VERSION 5.8 ;
BUSBITCHARS "[]" ;
DIVIDERCHAR "/" ;
UNITS
    DATABASE MICRONS 1000 ;
END UNITS

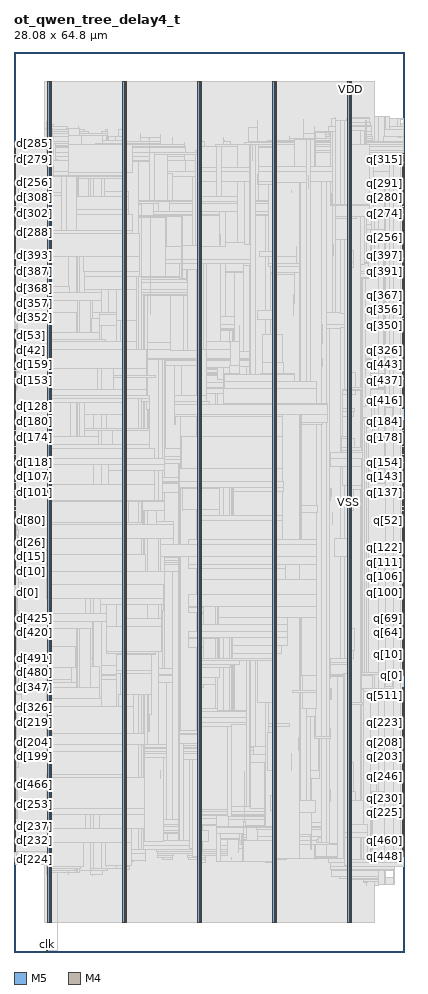
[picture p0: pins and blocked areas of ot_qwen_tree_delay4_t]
MACRO ot_qwen_tree_delay4_t
  FOREIGN ot_qwen_tree_delay4_t 0 0 ;
  CLASS BLOCK ;
  SIZE 28.08 BY 64.8 ;
  PIN clk
    DIRECTION INPUT ;
    USE SIGNAL ;
    PORT
      LAYER M5 ;
        RECT  2.352 0 2.376 0.084 ;
    END
    PORT
      LAYER M5 ;
        RECT  2.352 0.016 2.376 0.085 ;
    END
  END clk
  PIN d[0]
    DIRECTION INPUT ;
    USE SIGNAL ;
    PORT
      LAYER M4 ;
        RECT  0 26.448 0.084 26.472 ;
    END
  END d[0]
  PIN d[100]
    DIRECTION INPUT ;
    USE SIGNAL ;
    PORT
      LAYER M4 ;
        RECT  0 32.976 0.084 33 ;
    END
  END d[100]
  PIN d[101]
    DIRECTION INPUT ;
    USE SIGNAL ;
    PORT
      LAYER M4 ;
        RECT  0 33.072 0.084 33.096 ;
    END
  END d[101]
  PIN d[102]
    DIRECTION INPUT ;
    USE SIGNAL ;
    PORT
      LAYER M4 ;
        RECT  0 33.168 0.084 33.192 ;
    END
  END d[102]
  PIN d[103]
    DIRECTION INPUT ;
    USE SIGNAL ;
    PORT
      LAYER M4 ;
        RECT  0 33.264 0.084 33.288 ;
    END
  END d[103]
  PIN d[104]
    DIRECTION INPUT ;
    USE SIGNAL ;
    PORT
      LAYER M4 ;
        RECT  0 33.36 0.084 33.384 ;
    END
  END d[104]
  PIN d[105]
    DIRECTION INPUT ;
    USE SIGNAL ;
    PORT
      LAYER M4 ;
        RECT  0 33.456 0.084 33.48 ;
    END
  END d[105]
  PIN d[106]
    DIRECTION INPUT ;
    USE SIGNAL ;
    PORT
      LAYER M4 ;
        RECT  0 33.552 0.084 33.576 ;
    END
  END d[106]
  PIN d[107]
    DIRECTION INPUT ;
    USE SIGNAL ;
    PORT
      LAYER M4 ;
        RECT  0 33.648 0.084 33.672 ;
    END
  END d[107]
  PIN d[108]
    DIRECTION INPUT ;
    USE SIGNAL ;
    PORT
      LAYER M4 ;
        RECT  0 33.744 0.084 33.768 ;
    END
  END d[108]
  PIN d[109]
    DIRECTION INPUT ;
    USE SIGNAL ;
    PORT
      LAYER M4 ;
        RECT  0 33.84 0.084 33.864 ;
    END
  END d[109]
  PIN d[10]
    DIRECTION INPUT ;
    USE SIGNAL ;
    PORT
      LAYER M4 ;
        RECT  0 27.408 0.084 27.432 ;
    END
  END d[10]
  PIN d[110]
    DIRECTION INPUT ;
    USE SIGNAL ;
    PORT
      LAYER M4 ;
        RECT  0 33.936 0.084 33.96 ;
    END
  END d[110]
  PIN d[111]
    DIRECTION INPUT ;
    USE SIGNAL ;
    PORT
      LAYER M4 ;
        RECT  0 34.032 0.084 34.056 ;
    END
  END d[111]
  PIN d[112]
    DIRECTION INPUT ;
    USE SIGNAL ;
    PORT
      LAYER M4 ;
        RECT  0 34.128 0.084 34.152 ;
    END
  END d[112]
  PIN d[113]
    DIRECTION INPUT ;
    USE SIGNAL ;
    PORT
      LAYER M4 ;
        RECT  0 34.224 0.084 34.248 ;
    END
  END d[113]
  PIN d[114]
    DIRECTION INPUT ;
    USE SIGNAL ;
    PORT
      LAYER M4 ;
        RECT  0 34.32 0.084 34.344 ;
    END
  END d[114]
  PIN d[115]
    DIRECTION INPUT ;
    USE SIGNAL ;
    PORT
      LAYER M4 ;
        RECT  0 34.416 0.084 34.44 ;
    END
  END d[115]
  PIN d[116]
    DIRECTION INPUT ;
    USE SIGNAL ;
    PORT
      LAYER M4 ;
        RECT  0 34.512 0.084 34.536 ;
    END
  END d[116]
  PIN d[117]
    DIRECTION INPUT ;
    USE SIGNAL ;
    PORT
      LAYER M4 ;
        RECT  0 34.608 0.084 34.632 ;
    END
  END d[117]
  PIN d[118]
    DIRECTION INPUT ;
    USE SIGNAL ;
    PORT
      LAYER M4 ;
        RECT  0 34.704 0.084 34.728 ;
    END
  END d[118]
  PIN d[119]
    DIRECTION INPUT ;
    USE SIGNAL ;
    PORT
      LAYER M4 ;
        RECT  0 34.8 0.084 34.824 ;
    END
  END d[119]
  PIN d[11]
    DIRECTION INPUT ;
    USE SIGNAL ;
    PORT
      LAYER M4 ;
        RECT  0 27.504 0.084 27.528 ;
    END
  END d[11]
  PIN d[120]
    DIRECTION INPUT ;
    USE SIGNAL ;
    PORT
      LAYER M4 ;
        RECT  0 34.896 0.084 34.92 ;
    END
  END d[120]
  PIN d[121]
    DIRECTION INPUT ;
    USE SIGNAL ;
    PORT
      LAYER M4 ;
        RECT  0 34.992 0.084 35.016 ;
    END
  END d[121]
  PIN d[122]
    DIRECTION INPUT ;
    USE SIGNAL ;
    PORT
      LAYER M4 ;
        RECT  0 35.088 0.084 35.112 ;
    END
  END d[122]
  PIN d[123]
    DIRECTION INPUT ;
    USE SIGNAL ;
    PORT
      LAYER M4 ;
        RECT  0 35.184 0.084 35.208 ;
    END
  END d[123]
  PIN d[124]
    DIRECTION INPUT ;
    USE SIGNAL ;
    PORT
      LAYER M4 ;
        RECT  0 35.28 0.084 35.304 ;
    END
  END d[124]
  PIN d[125]
    DIRECTION INPUT ;
    USE SIGNAL ;
    PORT
      LAYER M4 ;
        RECT  0 35.376 0.084 35.4 ;
    END
  END d[125]
  PIN d[126]
    DIRECTION INPUT ;
    USE SIGNAL ;
    PORT
      LAYER M4 ;
        RECT  0 35.472 0.084 35.496 ;
    END
  END d[126]
  PIN d[127]
    DIRECTION INPUT ;
    USE SIGNAL ;
    PORT
      LAYER M4 ;
        RECT  0 35.568 0.084 35.592 ;
    END
  END d[127]
  PIN d[128]
    DIRECTION INPUT ;
    USE SIGNAL ;
    PORT
      LAYER M4 ;
        RECT  0 38.736 0.084 38.76 ;
    END
  END d[128]
  PIN d[129]
    DIRECTION INPUT ;
    USE SIGNAL ;
    PORT
      LAYER M4 ;
        RECT  0 38.832 0.084 38.856 ;
    END
  END d[129]
  PIN d[12]
    DIRECTION INPUT ;
    USE SIGNAL ;
    PORT
      LAYER M4 ;
        RECT  0 27.6 0.084 27.624 ;
    END
  END d[12]
  PIN d[130]
    DIRECTION INPUT ;
    USE SIGNAL ;
    PORT
      LAYER M4 ;
        RECT  0 38.928 0.084 38.952 ;
    END
  END d[130]
  PIN d[131]
    DIRECTION INPUT ;
    USE SIGNAL ;
    PORT
      LAYER M4 ;
        RECT  0 39.024 0.084 39.048 ;
    END
  END d[131]
  PIN d[132]
    DIRECTION INPUT ;
    USE SIGNAL ;
    PORT
      LAYER M4 ;
        RECT  0 39.12 0.084 39.144 ;
    END
  END d[132]
  PIN d[133]
    DIRECTION INPUT ;
    USE SIGNAL ;
    PORT
      LAYER M4 ;
        RECT  0 39.216 0.084 39.24 ;
    END
  END d[133]
  PIN d[134]
    DIRECTION INPUT ;
    USE SIGNAL ;
    PORT
      LAYER M4 ;
        RECT  0 39.312 0.084 39.336 ;
    END
  END d[134]
  PIN d[135]
    DIRECTION INPUT ;
    USE SIGNAL ;
    PORT
      LAYER M4 ;
        RECT  0 39.408 0.084 39.432 ;
    END
  END d[135]
  PIN d[136]
    DIRECTION INPUT ;
    USE SIGNAL ;
    PORT
      LAYER M4 ;
        RECT  0 39.504 0.084 39.528 ;
    END
  END d[136]
  PIN d[137]
    DIRECTION INPUT ;
    USE SIGNAL ;
    PORT
      LAYER M4 ;
        RECT  0 39.6 0.084 39.624 ;
    END
  END d[137]
  PIN d[138]
    DIRECTION INPUT ;
    USE SIGNAL ;
    PORT
      LAYER M4 ;
        RECT  0 39.696 0.084 39.72 ;
    END
  END d[138]
  PIN d[139]
    DIRECTION INPUT ;
    USE SIGNAL ;
    PORT
      LAYER M4 ;
        RECT  0 39.792 0.084 39.816 ;
    END
  END d[139]
  PIN d[13]
    DIRECTION INPUT ;
    USE SIGNAL ;
    PORT
      LAYER M4 ;
        RECT  0 27.696 0.084 27.72 ;
    END
  END d[13]
  PIN d[140]
    DIRECTION INPUT ;
    USE SIGNAL ;
    PORT
      LAYER M4 ;
        RECT  0 39.888 0.084 39.912 ;
    END
  END d[140]
  PIN d[141]
    DIRECTION INPUT ;
    USE SIGNAL ;
    PORT
      LAYER M4 ;
        RECT  0 39.984 0.084 40.008 ;
    END
  END d[141]
  PIN d[142]
    DIRECTION INPUT ;
    USE SIGNAL ;
    PORT
      LAYER M4 ;
        RECT  0 40.08 0.084 40.104 ;
    END
  END d[142]
  PIN d[143]
    DIRECTION INPUT ;
    USE SIGNAL ;
    PORT
      LAYER M4 ;
        RECT  0 40.176 0.084 40.2 ;
    END
  END d[143]
  PIN d[144]
    DIRECTION INPUT ;
    USE SIGNAL ;
    PORT
      LAYER M4 ;
        RECT  0 40.272 0.084 40.296 ;
    END
  END d[144]
  PIN d[145]
    DIRECTION INPUT ;
    USE SIGNAL ;
    PORT
      LAYER M4 ;
        RECT  0 40.368 0.084 40.392 ;
    END
  END d[145]
  PIN d[146]
    DIRECTION INPUT ;
    USE SIGNAL ;
    PORT
      LAYER M4 ;
        RECT  0 40.464 0.084 40.488 ;
    END
  END d[146]
  PIN d[147]
    DIRECTION INPUT ;
    USE SIGNAL ;
    PORT
      LAYER M4 ;
        RECT  0 40.56 0.084 40.584 ;
    END
  END d[147]
  PIN d[148]
    DIRECTION INPUT ;
    USE SIGNAL ;
    PORT
      LAYER M4 ;
        RECT  0 40.656 0.084 40.68 ;
    END
  END d[148]
  PIN d[149]
    DIRECTION INPUT ;
    USE SIGNAL ;
    PORT
      LAYER M4 ;
        RECT  0 40.752 0.084 40.776 ;
    END
  END d[149]
  PIN d[14]
    DIRECTION INPUT ;
    USE SIGNAL ;
    PORT
      LAYER M4 ;
        RECT  0 27.792 0.084 27.816 ;
    END
  END d[14]
  PIN d[150]
    DIRECTION INPUT ;
    USE SIGNAL ;
    PORT
      LAYER M4 ;
        RECT  0 40.848 0.084 40.872 ;
    END
  END d[150]
  PIN d[151]
    DIRECTION INPUT ;
    USE SIGNAL ;
    PORT
      LAYER M4 ;
        RECT  0 40.944 0.084 40.968 ;
    END
  END d[151]
  PIN d[152]
    DIRECTION INPUT ;
    USE SIGNAL ;
    PORT
      LAYER M4 ;
        RECT  0 41.04 0.084 41.064 ;
    END
  END d[152]
  PIN d[153]
    DIRECTION INPUT ;
    USE SIGNAL ;
    PORT
      LAYER M4 ;
        RECT  0 41.136 0.084 41.16 ;
    END
  END d[153]
  PIN d[154]
    DIRECTION INPUT ;
    USE SIGNAL ;
    PORT
      LAYER M4 ;
        RECT  0 41.232 0.084 41.256 ;
    END
  END d[154]
  PIN d[155]
    DIRECTION INPUT ;
    USE SIGNAL ;
    PORT
      LAYER M4 ;
        RECT  0 41.328 0.084 41.352 ;
    END
  END d[155]
  PIN d[156]
    DIRECTION INPUT ;
    USE SIGNAL ;
    PORT
      LAYER M4 ;
        RECT  0 41.424 0.084 41.448 ;
    END
  END d[156]
  PIN d[157]
    DIRECTION INPUT ;
    USE SIGNAL ;
    PORT
      LAYER M4 ;
        RECT  0 41.52 0.084 41.544 ;
    END
  END d[157]
  PIN d[158]
    DIRECTION INPUT ;
    USE SIGNAL ;
    PORT
      LAYER M4 ;
        RECT  0 41.616 0.084 41.64 ;
    END
  END d[158]
  PIN d[159]
    DIRECTION INPUT ;
    USE SIGNAL ;
    PORT
      LAYER M4 ;
        RECT  0 41.712 0.084 41.736 ;
    END
  END d[159]
  PIN d[15]
    DIRECTION INPUT ;
    USE SIGNAL ;
    PORT
      LAYER M4 ;
        RECT  0 27.888 0.084 27.912 ;
    END
  END d[15]
  PIN d[160]
    DIRECTION INPUT ;
    USE SIGNAL ;
    PORT
      LAYER M4 ;
        RECT  0 35.664 0.084 35.688 ;
    END
  END d[160]
  PIN d[161]
    DIRECTION INPUT ;
    USE SIGNAL ;
    PORT
      LAYER M4 ;
        RECT  0 35.76 0.084 35.784 ;
    END
  END d[161]
  PIN d[162]
    DIRECTION INPUT ;
    USE SIGNAL ;
    PORT
      LAYER M4 ;
        RECT  0 35.856 0.084 35.88 ;
    END
  END d[162]
  PIN d[163]
    DIRECTION INPUT ;
    USE SIGNAL ;
    PORT
      LAYER M4 ;
        RECT  0 35.952 0.084 35.976 ;
    END
  END d[163]
  PIN d[164]
    DIRECTION INPUT ;
    USE SIGNAL ;
    PORT
      LAYER M4 ;
        RECT  0 36.048 0.084 36.072 ;
    END
  END d[164]
  PIN d[165]
    DIRECTION INPUT ;
    USE SIGNAL ;
    PORT
      LAYER M4 ;
        RECT  0 36.144 0.084 36.168 ;
    END
  END d[165]
  PIN d[166]
    DIRECTION INPUT ;
    USE SIGNAL ;
    PORT
      LAYER M4 ;
        RECT  0 36.24 0.084 36.264 ;
    END
  END d[166]
  PIN d[167]
    DIRECTION INPUT ;
    USE SIGNAL ;
    PORT
      LAYER M4 ;
        RECT  0 36.336 0.084 36.36 ;
    END
  END d[167]
  PIN d[168]
    DIRECTION INPUT ;
    USE SIGNAL ;
    PORT
      LAYER M4 ;
        RECT  0 36.432 0.084 36.456 ;
    END
  END d[168]
  PIN d[169]
    DIRECTION INPUT ;
    USE SIGNAL ;
    PORT
      LAYER M4 ;
        RECT  0 36.528 0.084 36.552 ;
    END
  END d[169]
  PIN d[16]
    DIRECTION INPUT ;
    USE SIGNAL ;
    PORT
      LAYER M4 ;
        RECT  0 27.984 0.084 28.008 ;
    END
  END d[16]
  PIN d[170]
    DIRECTION INPUT ;
    USE SIGNAL ;
    PORT
      LAYER M4 ;
        RECT  0 36.624 0.084 36.648 ;
    END
  END d[170]
  PIN d[171]
    DIRECTION INPUT ;
    USE SIGNAL ;
    PORT
      LAYER M4 ;
        RECT  0 36.72 0.084 36.744 ;
    END
  END d[171]
  PIN d[172]
    DIRECTION INPUT ;
    USE SIGNAL ;
    PORT
      LAYER M4 ;
        RECT  0 36.816 0.084 36.84 ;
    END
  END d[172]
  PIN d[173]
    DIRECTION INPUT ;
    USE SIGNAL ;
    PORT
      LAYER M4 ;
        RECT  0 36.912 0.084 36.936 ;
    END
  END d[173]
  PIN d[174]
    DIRECTION INPUT ;
    USE SIGNAL ;
    PORT
      LAYER M4 ;
        RECT  0 37.008 0.084 37.032 ;
    END
  END d[174]
  PIN d[175]
    DIRECTION INPUT ;
    USE SIGNAL ;
    PORT
      LAYER M4 ;
        RECT  0 37.104 0.084 37.128 ;
    END
  END d[175]
  PIN d[176]
    DIRECTION INPUT ;
    USE SIGNAL ;
    PORT
      LAYER M4 ;
        RECT  0 37.2 0.084 37.224 ;
    END
  END d[176]
  PIN d[177]
    DIRECTION INPUT ;
    USE SIGNAL ;
    PORT
      LAYER M4 ;
        RECT  0 37.296 0.084 37.32 ;
    END
  END d[177]
  PIN d[178]
    DIRECTION INPUT ;
    USE SIGNAL ;
    PORT
      LAYER M4 ;
        RECT  0 37.392 0.084 37.416 ;
    END
  END d[178]
  PIN d[179]
    DIRECTION INPUT ;
    USE SIGNAL ;
    PORT
      LAYER M4 ;
        RECT  0 37.488 0.084 37.512 ;
    END
  END d[179]
  PIN d[17]
    DIRECTION INPUT ;
    USE SIGNAL ;
    PORT
      LAYER M4 ;
        RECT  0 28.08 0.084 28.104 ;
    END
  END d[17]
  PIN d[180]
    DIRECTION INPUT ;
    USE SIGNAL ;
    PORT
      LAYER M4 ;
        RECT  0 37.584 0.084 37.608 ;
    END
  END d[180]
  PIN d[181]
    DIRECTION INPUT ;
    USE SIGNAL ;
    PORT
      LAYER M4 ;
        RECT  0 37.68 0.084 37.704 ;
    END
  END d[181]
  PIN d[182]
    DIRECTION INPUT ;
    USE SIGNAL ;
    PORT
      LAYER M4 ;
        RECT  0 37.776 0.084 37.8 ;
    END
  END d[182]
  PIN d[183]
    DIRECTION INPUT ;
    USE SIGNAL ;
    PORT
      LAYER M4 ;
        RECT  0 37.872 0.084 37.896 ;
    END
  END d[183]
  PIN d[184]
    DIRECTION INPUT ;
    USE SIGNAL ;
    PORT
      LAYER M4 ;
        RECT  0 37.968 0.084 37.992 ;
    END
  END d[184]
  PIN d[185]
    DIRECTION INPUT ;
    USE SIGNAL ;
    PORT
      LAYER M4 ;
        RECT  0 38.064 0.084 38.088 ;
    END
  END d[185]
  PIN d[186]
    DIRECTION INPUT ;
    USE SIGNAL ;
    PORT
      LAYER M4 ;
        RECT  0 38.16 0.084 38.184 ;
    END
  END d[186]
  PIN d[187]
    DIRECTION INPUT ;
    USE SIGNAL ;
    PORT
      LAYER M4 ;
        RECT  0 38.256 0.084 38.28 ;
    END
  END d[187]
  PIN d[188]
    DIRECTION INPUT ;
    USE SIGNAL ;
    PORT
      LAYER M4 ;
        RECT  0 38.352 0.084 38.376 ;
    END
  END d[188]
  PIN d[189]
    DIRECTION INPUT ;
    USE SIGNAL ;
    PORT
      LAYER M4 ;
        RECT  0 38.448 0.084 38.472 ;
    END
  END d[189]
  PIN d[18]
    DIRECTION INPUT ;
    USE SIGNAL ;
    PORT
      LAYER M4 ;
        RECT  0 28.176 0.084 28.2 ;
    END
  END d[18]
  PIN d[190]
    DIRECTION INPUT ;
    USE SIGNAL ;
    PORT
      LAYER M4 ;
        RECT  0 38.544 0.084 38.568 ;
    END
  END d[190]
  PIN d[191]
    DIRECTION INPUT ;
    USE SIGNAL ;
    PORT
      LAYER M4 ;
        RECT  0 38.64 0.084 38.664 ;
    END
  END d[191]
  PIN d[192]
    DIRECTION INPUT ;
    USE SIGNAL ;
    PORT
      LAYER M4 ;
        RECT  0 13.392 0.084 13.416 ;
    END
  END d[192]
  PIN d[193]
    DIRECTION INPUT ;
    USE SIGNAL ;
    PORT
      LAYER M4 ;
        RECT  0 13.488 0.084 13.512 ;
    END
  END d[193]
  PIN d[194]
    DIRECTION INPUT ;
    USE SIGNAL ;
    PORT
      LAYER M4 ;
        RECT  0 13.584 0.084 13.608 ;
    END
  END d[194]
  PIN d[195]
    DIRECTION INPUT ;
    USE SIGNAL ;
    PORT
      LAYER M4 ;
        RECT  0 13.68 0.084 13.704 ;
    END
  END d[195]
  PIN d[196]
    DIRECTION INPUT ;
    USE SIGNAL ;
    PORT
      LAYER M4 ;
        RECT  0 13.776 0.084 13.8 ;
    END
  END d[196]
  PIN d[197]
    DIRECTION INPUT ;
    USE SIGNAL ;
    PORT
      LAYER M4 ;
        RECT  0 13.872 0.084 13.896 ;
    END
  END d[197]
  PIN d[198]
    DIRECTION INPUT ;
    USE SIGNAL ;
    PORT
      LAYER M4 ;
        RECT  0 13.968 0.084 13.992 ;
    END
  END d[198]
  PIN d[199]
    DIRECTION INPUT ;
    USE SIGNAL ;
    PORT
      LAYER M4 ;
        RECT  0 14.064 0.084 14.088 ;
    END
  END d[199]
  PIN d[19]
    DIRECTION INPUT ;
    USE SIGNAL ;
    PORT
      LAYER M4 ;
        RECT  0 28.272 0.084 28.296 ;
    END
  END d[19]
  PIN d[1]
    DIRECTION INPUT ;
    USE SIGNAL ;
    PORT
      LAYER M4 ;
        RECT  0 26.544 0.084 26.568 ;
    END
  END d[1]
  PIN d[200]
    DIRECTION INPUT ;
    USE SIGNAL ;
    PORT
      LAYER M4 ;
        RECT  0 14.16 0.084 14.184 ;
    END
  END d[200]
  PIN d[201]
    DIRECTION INPUT ;
    USE SIGNAL ;
    PORT
      LAYER M4 ;
        RECT  0 14.256 0.084 14.28 ;
    END
  END d[201]
  PIN d[202]
    DIRECTION INPUT ;
    USE SIGNAL ;
    PORT
      LAYER M4 ;
        RECT  0 14.352 0.084 14.376 ;
    END
  END d[202]
  PIN d[203]
    DIRECTION INPUT ;
    USE SIGNAL ;
    PORT
      LAYER M4 ;
        RECT  0 14.448 0.084 14.472 ;
    END
  END d[203]
  PIN d[204]
    DIRECTION INPUT ;
    USE SIGNAL ;
    PORT
      LAYER M4 ;
        RECT  0 14.544 0.084 14.568 ;
    END
  END d[204]
  PIN d[205]
    DIRECTION INPUT ;
    USE SIGNAL ;
    PORT
      LAYER M4 ;
        RECT  0 14.64 0.084 14.664 ;
    END
  END d[205]
  PIN d[206]
    DIRECTION INPUT ;
    USE SIGNAL ;
    PORT
      LAYER M4 ;
        RECT  0 14.736 0.084 14.76 ;
    END
  END d[206]
  PIN d[207]
    DIRECTION INPUT ;
    USE SIGNAL ;
    PORT
      LAYER M4 ;
        RECT  0 14.832 0.084 14.856 ;
    END
  END d[207]
  PIN d[208]
    DIRECTION INPUT ;
    USE SIGNAL ;
    PORT
      LAYER M4 ;
        RECT  0 14.928 0.084 14.952 ;
    END
  END d[208]
  PIN d[209]
    DIRECTION INPUT ;
    USE SIGNAL ;
    PORT
      LAYER M4 ;
        RECT  0 15.024 0.084 15.048 ;
    END
  END d[209]
  PIN d[20]
    DIRECTION INPUT ;
    USE SIGNAL ;
    PORT
      LAYER M4 ;
        RECT  0 28.368 0.084 28.392 ;
    END
  END d[20]
  PIN d[210]
    DIRECTION INPUT ;
    USE SIGNAL ;
    PORT
      LAYER M4 ;
        RECT  0 15.12 0.084 15.144 ;
    END
  END d[210]
  PIN d[211]
    DIRECTION INPUT ;
    USE SIGNAL ;
    PORT
      LAYER M4 ;
        RECT  0 15.216 0.084 15.24 ;
    END
  END d[211]
  PIN d[212]
    DIRECTION INPUT ;
    USE SIGNAL ;
    PORT
      LAYER M4 ;
        RECT  0 15.312 0.084 15.336 ;
    END
  END d[212]
  PIN d[213]
    DIRECTION INPUT ;
    USE SIGNAL ;
    PORT
      LAYER M4 ;
        RECT  0 15.408 0.084 15.432 ;
    END
  END d[213]
  PIN d[214]
    DIRECTION INPUT ;
    USE SIGNAL ;
    PORT
      LAYER M4 ;
        RECT  0 15.504 0.084 15.528 ;
    END
  END d[214]
  PIN d[215]
    DIRECTION INPUT ;
    USE SIGNAL ;
    PORT
      LAYER M4 ;
        RECT  0 15.6 0.084 15.624 ;
    END
  END d[215]
  PIN d[216]
    DIRECTION INPUT ;
    USE SIGNAL ;
    PORT
      LAYER M4 ;
        RECT  0 15.696 0.084 15.72 ;
    END
  END d[216]
  PIN d[217]
    DIRECTION INPUT ;
    USE SIGNAL ;
    PORT
      LAYER M4 ;
        RECT  0 15.792 0.084 15.816 ;
    END
  END d[217]
  PIN d[218]
    DIRECTION INPUT ;
    USE SIGNAL ;
    PORT
      LAYER M4 ;
        RECT  0 15.888 0.084 15.912 ;
    END
  END d[218]
  PIN d[219]
    DIRECTION INPUT ;
    USE SIGNAL ;
    PORT
      LAYER M4 ;
        RECT  0 15.984 0.084 16.008 ;
    END
  END d[219]
  PIN d[21]
    DIRECTION INPUT ;
    USE SIGNAL ;
    PORT
      LAYER M4 ;
        RECT  0 28.464 0.084 28.488 ;
    END
  END d[21]
  PIN d[220]
    DIRECTION INPUT ;
    USE SIGNAL ;
    PORT
      LAYER M4 ;
        RECT  0 16.08 0.084 16.104 ;
    END
  END d[220]
  PIN d[221]
    DIRECTION INPUT ;
    USE SIGNAL ;
    PORT
      LAYER M4 ;
        RECT  0 16.176 0.084 16.2 ;
    END
  END d[221]
  PIN d[222]
    DIRECTION INPUT ;
    USE SIGNAL ;
    PORT
      LAYER M4 ;
        RECT  0 16.272 0.084 16.296 ;
    END
  END d[222]
  PIN d[223]
    DIRECTION INPUT ;
    USE SIGNAL ;
    PORT
      LAYER M4 ;
        RECT  0 16.368 0.084 16.392 ;
    END
  END d[223]
  PIN d[224]
    DIRECTION INPUT ;
    USE SIGNAL ;
    PORT
      LAYER M4 ;
        RECT  0 7.248 0.084 7.272 ;
    END
  END d[224]
  PIN d[225]
    DIRECTION INPUT ;
    USE SIGNAL ;
    PORT
      LAYER M4 ;
        RECT  0 7.344 0.084 7.368 ;
    END
  END d[225]
  PIN d[226]
    DIRECTION INPUT ;
    USE SIGNAL ;
    PORT
      LAYER M4 ;
        RECT  0 7.44 0.084 7.464 ;
    END
  END d[226]
  PIN d[227]
    DIRECTION INPUT ;
    USE SIGNAL ;
    PORT
      LAYER M4 ;
        RECT  0 7.536 0.084 7.56 ;
    END
  END d[227]
  PIN d[228]
    DIRECTION INPUT ;
    USE SIGNAL ;
    PORT
      LAYER M4 ;
        RECT  0 7.632 0.084 7.656 ;
    END
  END d[228]
  PIN d[229]
    DIRECTION INPUT ;
    USE SIGNAL ;
    PORT
      LAYER M4 ;
        RECT  0 7.728 0.084 7.752 ;
    END
  END d[229]
  PIN d[22]
    DIRECTION INPUT ;
    USE SIGNAL ;
    PORT
      LAYER M4 ;
        RECT  0 28.56 0.084 28.584 ;
    END
  END d[22]
  PIN d[230]
    DIRECTION INPUT ;
    USE SIGNAL ;
    PORT
      LAYER M4 ;
        RECT  0 7.824 0.084 7.848 ;
    END
  END d[230]
  PIN d[231]
    DIRECTION INPUT ;
    USE SIGNAL ;
    PORT
      LAYER M4 ;
        RECT  0 7.92 0.084 7.944 ;
    END
  END d[231]
  PIN d[232]
    DIRECTION INPUT ;
    USE SIGNAL ;
    PORT
      LAYER M4 ;
        RECT  0 8.016 0.084 8.04 ;
    END
  END d[232]
  PIN d[233]
    DIRECTION INPUT ;
    USE SIGNAL ;
    PORT
      LAYER M4 ;
        RECT  0 8.112 0.084 8.136 ;
    END
  END d[233]
  PIN d[234]
    DIRECTION INPUT ;
    USE SIGNAL ;
    PORT
      LAYER M4 ;
        RECT  0 8.208 0.084 8.232 ;
    END
  END d[234]
  PIN d[235]
    DIRECTION INPUT ;
    USE SIGNAL ;
    PORT
      LAYER M4 ;
        RECT  0 8.304 0.084 8.328 ;
    END
  END d[235]
  PIN d[236]
    DIRECTION INPUT ;
    USE SIGNAL ;
    PORT
      LAYER M4 ;
        RECT  0 8.4 0.084 8.424 ;
    END
  END d[236]
  PIN d[237]
    DIRECTION INPUT ;
    USE SIGNAL ;
    PORT
      LAYER M4 ;
        RECT  0 8.496 0.084 8.52 ;
    END
  END d[237]
  PIN d[238]
    DIRECTION INPUT ;
    USE SIGNAL ;
    PORT
      LAYER M4 ;
        RECT  0 8.592 0.084 8.616 ;
    END
  END d[238]
  PIN d[239]
    DIRECTION INPUT ;
    USE SIGNAL ;
    PORT
      LAYER M4 ;
        RECT  0 8.688 0.084 8.712 ;
    END
  END d[239]
  PIN d[23]
    DIRECTION INPUT ;
    USE SIGNAL ;
    PORT
      LAYER M4 ;
        RECT  0 28.656 0.084 28.68 ;
    END
  END d[23]
  PIN d[240]
    DIRECTION INPUT ;
    USE SIGNAL ;
    PORT
      LAYER M4 ;
        RECT  0 8.784 0.084 8.808 ;
    END
  END d[240]
  PIN d[241]
    DIRECTION INPUT ;
    USE SIGNAL ;
    PORT
      LAYER M4 ;
        RECT  0 8.88 0.084 8.904 ;
    END
  END d[241]
  PIN d[242]
    DIRECTION INPUT ;
    USE SIGNAL ;
    PORT
      LAYER M4 ;
        RECT  0 8.976 0.084 9 ;
    END
  END d[242]
  PIN d[243]
    DIRECTION INPUT ;
    USE SIGNAL ;
    PORT
      LAYER M4 ;
        RECT  0 9.072 0.084 9.096 ;
    END
  END d[243]
  PIN d[244]
    DIRECTION INPUT ;
    USE SIGNAL ;
    PORT
      LAYER M4 ;
        RECT  0 9.168 0.084 9.192 ;
    END
  END d[244]
  PIN d[245]
    DIRECTION INPUT ;
    USE SIGNAL ;
    PORT
      LAYER M4 ;
        RECT  0 9.264 0.084 9.288 ;
    END
  END d[245]
  PIN d[246]
    DIRECTION INPUT ;
    USE SIGNAL ;
    PORT
      LAYER M4 ;
        RECT  0 9.36 0.084 9.384 ;
    END
  END d[246]
  PIN d[247]
    DIRECTION INPUT ;
    USE SIGNAL ;
    PORT
      LAYER M4 ;
        RECT  0 9.456 0.084 9.48 ;
    END
  END d[247]
  PIN d[248]
    DIRECTION INPUT ;
    USE SIGNAL ;
    PORT
      LAYER M4 ;
        RECT  0 9.552 0.084 9.576 ;
    END
  END d[248]
  PIN d[249]
    DIRECTION INPUT ;
    USE SIGNAL ;
    PORT
      LAYER M4 ;
        RECT  0 9.648 0.084 9.672 ;
    END
  END d[249]
  PIN d[24]
    DIRECTION INPUT ;
    USE SIGNAL ;
    PORT
      LAYER M4 ;
        RECT  0 28.752 0.084 28.776 ;
    END
  END d[24]
  PIN d[250]
    DIRECTION INPUT ;
    USE SIGNAL ;
    PORT
      LAYER M4 ;
        RECT  0 9.744 0.084 9.768 ;
    END
  END d[250]
  PIN d[251]
    DIRECTION INPUT ;
    USE SIGNAL ;
    PORT
      LAYER M4 ;
        RECT  0 9.84 0.084 9.864 ;
    END
  END d[251]
  PIN d[252]
    DIRECTION INPUT ;
    USE SIGNAL ;
    PORT
      LAYER M4 ;
        RECT  0 9.936 0.084 9.96 ;
    END
  END d[252]
  PIN d[253]
    DIRECTION INPUT ;
    USE SIGNAL ;
    PORT
      LAYER M4 ;
        RECT  0 10.032 0.084 10.056 ;
    END
  END d[253]
  PIN d[254]
    DIRECTION INPUT ;
    USE SIGNAL ;
    PORT
      LAYER M4 ;
        RECT  0 10.128 0.084 10.152 ;
    END
  END d[254]
  PIN d[255]
    DIRECTION INPUT ;
    USE SIGNAL ;
    PORT
      LAYER M4 ;
        RECT  0 10.224 0.084 10.248 ;
    END
  END d[255]
  PIN d[256]
    DIRECTION INPUT ;
    USE SIGNAL ;
    PORT
      LAYER M4 ;
        RECT  0 54.864 0.084 54.888 ;
    END
  END d[256]
  PIN d[257]
    DIRECTION INPUT ;
    USE SIGNAL ;
    PORT
      LAYER M4 ;
        RECT  0 54.96 0.084 54.984 ;
    END
  END d[257]
  PIN d[258]
    DIRECTION INPUT ;
    USE SIGNAL ;
    PORT
      LAYER M4 ;
        RECT  0 55.056 0.084 55.08 ;
    END
  END d[258]
  PIN d[259]
    DIRECTION INPUT ;
    USE SIGNAL ;
    PORT
      LAYER M4 ;
        RECT  0 55.152 0.084 55.176 ;
    END
  END d[259]
  PIN d[25]
    DIRECTION INPUT ;
    USE SIGNAL ;
    PORT
      LAYER M4 ;
        RECT  0 28.848 0.084 28.872 ;
    END
  END d[25]
  PIN d[260]
    DIRECTION INPUT ;
    USE SIGNAL ;
    PORT
      LAYER M4 ;
        RECT  0 55.248 0.084 55.272 ;
    END
  END d[260]
  PIN d[261]
    DIRECTION INPUT ;
    USE SIGNAL ;
    PORT
      LAYER M4 ;
        RECT  0 55.344 0.084 55.368 ;
    END
  END d[261]
  PIN d[262]
    DIRECTION INPUT ;
    USE SIGNAL ;
    PORT
      LAYER M4 ;
        RECT  0 55.44 0.084 55.464 ;
    END
  END d[262]
  PIN d[263]
    DIRECTION INPUT ;
    USE SIGNAL ;
    PORT
      LAYER M4 ;
        RECT  0 55.536 0.084 55.56 ;
    END
  END d[263]
  PIN d[264]
    DIRECTION INPUT ;
    USE SIGNAL ;
    PORT
      LAYER M4 ;
        RECT  0 55.632 0.084 55.656 ;
    END
  END d[264]
  PIN d[265]
    DIRECTION INPUT ;
    USE SIGNAL ;
    PORT
      LAYER M4 ;
        RECT  0 55.728 0.084 55.752 ;
    END
  END d[265]
  PIN d[266]
    DIRECTION INPUT ;
    USE SIGNAL ;
    PORT
      LAYER M4 ;
        RECT  0 55.824 0.084 55.848 ;
    END
  END d[266]
  PIN d[267]
    DIRECTION INPUT ;
    USE SIGNAL ;
    PORT
      LAYER M4 ;
        RECT  0 55.92 0.084 55.944 ;
    END
  END d[267]
  PIN d[268]
    DIRECTION INPUT ;
    USE SIGNAL ;
    PORT
      LAYER M4 ;
        RECT  0 56.016 0.084 56.04 ;
    END
  END d[268]
  PIN d[269]
    DIRECTION INPUT ;
    USE SIGNAL ;
    PORT
      LAYER M4 ;
        RECT  0 56.112 0.084 56.136 ;
    END
  END d[269]
  PIN d[26]
    DIRECTION INPUT ;
    USE SIGNAL ;
    PORT
      LAYER M4 ;
        RECT  0 28.944 0.084 28.968 ;
    END
  END d[26]
  PIN d[270]
    DIRECTION INPUT ;
    USE SIGNAL ;
    PORT
      LAYER M4 ;
        RECT  0 56.208 0.084 56.232 ;
    END
  END d[270]
  PIN d[271]
    DIRECTION INPUT ;
    USE SIGNAL ;
    PORT
      LAYER M4 ;
        RECT  0 56.304 0.084 56.328 ;
    END
  END d[271]
  PIN d[272]
    DIRECTION INPUT ;
    USE SIGNAL ;
    PORT
      LAYER M4 ;
        RECT  0 56.4 0.084 56.424 ;
    END
  END d[272]
  PIN d[273]
    DIRECTION INPUT ;
    USE SIGNAL ;
    PORT
      LAYER M4 ;
        RECT  0 56.496 0.084 56.52 ;
    END
  END d[273]
  PIN d[274]
    DIRECTION INPUT ;
    USE SIGNAL ;
    PORT
      LAYER M4 ;
        RECT  0 56.592 0.084 56.616 ;
    END
  END d[274]
  PIN d[275]
    DIRECTION INPUT ;
    USE SIGNAL ;
    PORT
      LAYER M4 ;
        RECT  0 56.688 0.084 56.712 ;
    END
  END d[275]
  PIN d[276]
    DIRECTION INPUT ;
    USE SIGNAL ;
    PORT
      LAYER M4 ;
        RECT  0 56.784 0.084 56.808 ;
    END
  END d[276]
  PIN d[277]
    DIRECTION INPUT ;
    USE SIGNAL ;
    PORT
      LAYER M4 ;
        RECT  0 56.88 0.084 56.904 ;
    END
  END d[277]
  PIN d[278]
    DIRECTION INPUT ;
    USE SIGNAL ;
    PORT
      LAYER M4 ;
        RECT  0 56.976 0.084 57 ;
    END
  END d[278]
  PIN d[279]
    DIRECTION INPUT ;
    USE SIGNAL ;
    PORT
      LAYER M4 ;
        RECT  0 57.072 0.084 57.096 ;
    END
  END d[279]
  PIN d[27]
    DIRECTION INPUT ;
    USE SIGNAL ;
    PORT
      LAYER M4 ;
        RECT  0 29.04 0.084 29.064 ;
    END
  END d[27]
  PIN d[280]
    DIRECTION INPUT ;
    USE SIGNAL ;
    PORT
      LAYER M4 ;
        RECT  0 57.168 0.084 57.192 ;
    END
  END d[280]
  PIN d[281]
    DIRECTION INPUT ;
    USE SIGNAL ;
    PORT
      LAYER M4 ;
        RECT  0 57.264 0.084 57.288 ;
    END
  END d[281]
  PIN d[282]
    DIRECTION INPUT ;
    USE SIGNAL ;
    PORT
      LAYER M4 ;
        RECT  0 57.36 0.084 57.384 ;
    END
  END d[282]
  PIN d[283]
    DIRECTION INPUT ;
    USE SIGNAL ;
    PORT
      LAYER M4 ;
        RECT  0 57.456 0.084 57.48 ;
    END
  END d[283]
  PIN d[284]
    DIRECTION INPUT ;
    USE SIGNAL ;
    PORT
      LAYER M4 ;
        RECT  0 57.552 0.084 57.576 ;
    END
  END d[284]
  PIN d[285]
    DIRECTION INPUT ;
    USE SIGNAL ;
    PORT
      LAYER M4 ;
        RECT  0 57.648 0.084 57.672 ;
    END
  END d[285]
  PIN d[286]
    DIRECTION INPUT ;
    USE SIGNAL ;
    PORT
      LAYER M4 ;
        RECT  0 57.744 0.084 57.768 ;
    END
  END d[286]
  PIN d[287]
    DIRECTION INPUT ;
    USE SIGNAL ;
    PORT
      LAYER M4 ;
        RECT  0 57.84 0.084 57.864 ;
    END
  END d[287]
  PIN d[288]
    DIRECTION INPUT ;
    USE SIGNAL ;
    PORT
      LAYER M4 ;
        RECT  0 51.792 0.084 51.816 ;
    END
  END d[288]
  PIN d[289]
    DIRECTION INPUT ;
    USE SIGNAL ;
    PORT
      LAYER M4 ;
        RECT  0 51.888 0.084 51.912 ;
    END
  END d[289]
  PIN d[28]
    DIRECTION INPUT ;
    USE SIGNAL ;
    PORT
      LAYER M4 ;
        RECT  0 29.136 0.084 29.16 ;
    END
  END d[28]
  PIN d[290]
    DIRECTION INPUT ;
    USE SIGNAL ;
    PORT
      LAYER M4 ;
        RECT  0 51.984 0.084 52.008 ;
    END
  END d[290]
  PIN d[291]
    DIRECTION INPUT ;
    USE SIGNAL ;
    PORT
      LAYER M4 ;
        RECT  0 52.08 0.084 52.104 ;
    END
  END d[291]
  PIN d[292]
    DIRECTION INPUT ;
    USE SIGNAL ;
    PORT
      LAYER M4 ;
        RECT  0 52.176 0.084 52.2 ;
    END
  END d[292]
  PIN d[293]
    DIRECTION INPUT ;
    USE SIGNAL ;
    PORT
      LAYER M4 ;
        RECT  0 52.272 0.084 52.296 ;
    END
  END d[293]
  PIN d[294]
    DIRECTION INPUT ;
    USE SIGNAL ;
    PORT
      LAYER M4 ;
        RECT  0 52.368 0.084 52.392 ;
    END
  END d[294]
  PIN d[295]
    DIRECTION INPUT ;
    USE SIGNAL ;
    PORT
      LAYER M4 ;
        RECT  0 52.464 0.084 52.488 ;
    END
  END d[295]
  PIN d[296]
    DIRECTION INPUT ;
    USE SIGNAL ;
    PORT
      LAYER M4 ;
        RECT  0 52.56 0.084 52.584 ;
    END
  END d[296]
  PIN d[297]
    DIRECTION INPUT ;
    USE SIGNAL ;
    PORT
      LAYER M4 ;
        RECT  0 52.656 0.084 52.68 ;
    END
  END d[297]
  PIN d[298]
    DIRECTION INPUT ;
    USE SIGNAL ;
    PORT
      LAYER M4 ;
        RECT  0 52.752 0.084 52.776 ;
    END
  END d[298]
  PIN d[299]
    DIRECTION INPUT ;
    USE SIGNAL ;
    PORT
      LAYER M4 ;
        RECT  0 52.848 0.084 52.872 ;
    END
  END d[299]
  PIN d[29]
    DIRECTION INPUT ;
    USE SIGNAL ;
    PORT
      LAYER M4 ;
        RECT  0 29.232 0.084 29.256 ;
    END
  END d[29]
  PIN d[2]
    DIRECTION INPUT ;
    USE SIGNAL ;
    PORT
      LAYER M4 ;
        RECT  0 26.64 0.084 26.664 ;
    END
  END d[2]
  PIN d[300]
    DIRECTION INPUT ;
    USE SIGNAL ;
    PORT
      LAYER M4 ;
        RECT  0 52.944 0.084 52.968 ;
    END
  END d[300]
  PIN d[301]
    DIRECTION INPUT ;
    USE SIGNAL ;
    PORT
      LAYER M4 ;
        RECT  0 53.04 0.084 53.064 ;
    END
  END d[301]
  PIN d[302]
    DIRECTION INPUT ;
    USE SIGNAL ;
    PORT
      LAYER M4 ;
        RECT  0 53.136 0.084 53.16 ;
    END
  END d[302]
  PIN d[303]
    DIRECTION INPUT ;
    USE SIGNAL ;
    PORT
      LAYER M4 ;
        RECT  0 53.232 0.084 53.256 ;
    END
  END d[303]
  PIN d[304]
    DIRECTION INPUT ;
    USE SIGNAL ;
    PORT
      LAYER M4 ;
        RECT  0 53.328 0.084 53.352 ;
    END
  END d[304]
  PIN d[305]
    DIRECTION INPUT ;
    USE SIGNAL ;
    PORT
      LAYER M4 ;
        RECT  0 53.424 0.084 53.448 ;
    END
  END d[305]
  PIN d[306]
    DIRECTION INPUT ;
    USE SIGNAL ;
    PORT
      LAYER M4 ;
        RECT  0 53.52 0.084 53.544 ;
    END
  END d[306]
  PIN d[307]
    DIRECTION INPUT ;
    USE SIGNAL ;
    PORT
      LAYER M4 ;
        RECT  0 53.616 0.084 53.64 ;
    END
  END d[307]
  PIN d[308]
    DIRECTION INPUT ;
    USE SIGNAL ;
    PORT
      LAYER M4 ;
        RECT  0 53.712 0.084 53.736 ;
    END
  END d[308]
  PIN d[309]
    DIRECTION INPUT ;
    USE SIGNAL ;
    PORT
      LAYER M4 ;
        RECT  0 53.808 0.084 53.832 ;
    END
  END d[309]
  PIN d[30]
    DIRECTION INPUT ;
    USE SIGNAL ;
    PORT
      LAYER M4 ;
        RECT  0 29.328 0.084 29.352 ;
    END
  END d[30]
  PIN d[310]
    DIRECTION INPUT ;
    USE SIGNAL ;
    PORT
      LAYER M4 ;
        RECT  0 53.904 0.084 53.928 ;
    END
  END d[310]
  PIN d[311]
    DIRECTION INPUT ;
    USE SIGNAL ;
    PORT
      LAYER M4 ;
        RECT  0 54 0.084 54.024 ;
    END
  END d[311]
  PIN d[312]
    DIRECTION INPUT ;
    USE SIGNAL ;
    PORT
      LAYER M4 ;
        RECT  0 54.096 0.084 54.12 ;
    END
  END d[312]
  PIN d[313]
    DIRECTION INPUT ;
    USE SIGNAL ;
    PORT
      LAYER M4 ;
        RECT  0 54.192 0.084 54.216 ;
    END
  END d[313]
  PIN d[314]
    DIRECTION INPUT ;
    USE SIGNAL ;
    PORT
      LAYER M4 ;
        RECT  0 54.288 0.084 54.312 ;
    END
  END d[314]
  PIN d[315]
    DIRECTION INPUT ;
    USE SIGNAL ;
    PORT
      LAYER M4 ;
        RECT  0 54.384 0.084 54.408 ;
    END
  END d[315]
  PIN d[316]
    DIRECTION INPUT ;
    USE SIGNAL ;
    PORT
      LAYER M4 ;
        RECT  0 54.48 0.084 54.504 ;
    END
  END d[316]
  PIN d[317]
    DIRECTION INPUT ;
    USE SIGNAL ;
    PORT
      LAYER M4 ;
        RECT  0 54.576 0.084 54.6 ;
    END
  END d[317]
  PIN d[318]
    DIRECTION INPUT ;
    USE SIGNAL ;
    PORT
      LAYER M4 ;
        RECT  0 54.672 0.084 54.696 ;
    END
  END d[318]
  PIN d[319]
    DIRECTION INPUT ;
    USE SIGNAL ;
    PORT
      LAYER M4 ;
        RECT  0 54.768 0.084 54.792 ;
    END
  END d[319]
  PIN d[31]
    DIRECTION INPUT ;
    USE SIGNAL ;
    PORT
      LAYER M4 ;
        RECT  0 29.424 0.084 29.448 ;
    END
  END d[31]
  PIN d[320]
    DIRECTION INPUT ;
    USE SIGNAL ;
    PORT
      LAYER M4 ;
        RECT  0 16.464 0.084 16.488 ;
    END
  END d[320]
  PIN d[321]
    DIRECTION INPUT ;
    USE SIGNAL ;
    PORT
      LAYER M4 ;
        RECT  0 16.56 0.084 16.584 ;
    END
  END d[321]
  PIN d[322]
    DIRECTION INPUT ;
    USE SIGNAL ;
    PORT
      LAYER M4 ;
        RECT  0 16.656 0.084 16.68 ;
    END
  END d[322]
  PIN d[323]
    DIRECTION INPUT ;
    USE SIGNAL ;
    PORT
      LAYER M4 ;
        RECT  0 16.752 0.084 16.776 ;
    END
  END d[323]
  PIN d[324]
    DIRECTION INPUT ;
    USE SIGNAL ;
    PORT
      LAYER M4 ;
        RECT  0 16.848 0.084 16.872 ;
    END
  END d[324]
  PIN d[325]
    DIRECTION INPUT ;
    USE SIGNAL ;
    PORT
      LAYER M4 ;
        RECT  0 16.944 0.084 16.968 ;
    END
  END d[325]
  PIN d[326]
    DIRECTION INPUT ;
    USE SIGNAL ;
    PORT
      LAYER M4 ;
        RECT  0 17.04 0.084 17.064 ;
    END
  END d[326]
  PIN d[327]
    DIRECTION INPUT ;
    USE SIGNAL ;
    PORT
      LAYER M4 ;
        RECT  0 17.136 0.084 17.16 ;
    END
  END d[327]
  PIN d[328]
    DIRECTION INPUT ;
    USE SIGNAL ;
    PORT
      LAYER M4 ;
        RECT  0 17.232 0.084 17.256 ;
    END
  END d[328]
  PIN d[329]
    DIRECTION INPUT ;
    USE SIGNAL ;
    PORT
      LAYER M4 ;
        RECT  0 17.328 0.084 17.352 ;
    END
  END d[329]
  PIN d[32]
    DIRECTION INPUT ;
    USE SIGNAL ;
    PORT
      LAYER M4 ;
        RECT  0 41.808 0.084 41.832 ;
    END
  END d[32]
  PIN d[330]
    DIRECTION INPUT ;
    USE SIGNAL ;
    PORT
      LAYER M4 ;
        RECT  0 17.424 0.084 17.448 ;
    END
  END d[330]
  PIN d[331]
    DIRECTION INPUT ;
    USE SIGNAL ;
    PORT
      LAYER M4 ;
        RECT  0 17.52 0.084 17.544 ;
    END
  END d[331]
  PIN d[332]
    DIRECTION INPUT ;
    USE SIGNAL ;
    PORT
      LAYER M4 ;
        RECT  0 17.616 0.084 17.64 ;
    END
  END d[332]
  PIN d[333]
    DIRECTION INPUT ;
    USE SIGNAL ;
    PORT
      LAYER M4 ;
        RECT  0 17.712 0.084 17.736 ;
    END
  END d[333]
  PIN d[334]
    DIRECTION INPUT ;
    USE SIGNAL ;
    PORT
      LAYER M4 ;
        RECT  0 17.808 0.084 17.832 ;
    END
  END d[334]
  PIN d[335]
    DIRECTION INPUT ;
    USE SIGNAL ;
    PORT
      LAYER M4 ;
        RECT  0 17.904 0.084 17.928 ;
    END
  END d[335]
  PIN d[336]
    DIRECTION INPUT ;
    USE SIGNAL ;
    PORT
      LAYER M4 ;
        RECT  0 18 0.084 18.024 ;
    END
  END d[336]
  PIN d[337]
    DIRECTION INPUT ;
    USE SIGNAL ;
    PORT
      LAYER M4 ;
        RECT  0 18.096 0.084 18.12 ;
    END
  END d[337]
  PIN d[338]
    DIRECTION INPUT ;
    USE SIGNAL ;
    PORT
      LAYER M4 ;
        RECT  0 18.192 0.084 18.216 ;
    END
  END d[338]
  PIN d[339]
    DIRECTION INPUT ;
    USE SIGNAL ;
    PORT
      LAYER M4 ;
        RECT  0 18.288 0.084 18.312 ;
    END
  END d[339]
  PIN d[33]
    DIRECTION INPUT ;
    USE SIGNAL ;
    PORT
      LAYER M4 ;
        RECT  0 41.904 0.084 41.928 ;
    END
  END d[33]
  PIN d[340]
    DIRECTION INPUT ;
    USE SIGNAL ;
    PORT
      LAYER M4 ;
        RECT  0 18.384 0.084 18.408 ;
    END
  END d[340]
  PIN d[341]
    DIRECTION INPUT ;
    USE SIGNAL ;
    PORT
      LAYER M4 ;
        RECT  0 18.48 0.084 18.504 ;
    END
  END d[341]
  PIN d[342]
    DIRECTION INPUT ;
    USE SIGNAL ;
    PORT
      LAYER M4 ;
        RECT  0 18.576 0.084 18.6 ;
    END
  END d[342]
  PIN d[343]
    DIRECTION INPUT ;
    USE SIGNAL ;
    PORT
      LAYER M4 ;
        RECT  0 18.672 0.084 18.696 ;
    END
  END d[343]
  PIN d[344]
    DIRECTION INPUT ;
    USE SIGNAL ;
    PORT
      LAYER M4 ;
        RECT  0 18.768 0.084 18.792 ;
    END
  END d[344]
  PIN d[345]
    DIRECTION INPUT ;
    USE SIGNAL ;
    PORT
      LAYER M4 ;
        RECT  0 18.864 0.084 18.888 ;
    END
  END d[345]
  PIN d[346]
    DIRECTION INPUT ;
    USE SIGNAL ;
    PORT
      LAYER M4 ;
        RECT  0 18.96 0.084 18.984 ;
    END
  END d[346]
  PIN d[347]
    DIRECTION INPUT ;
    USE SIGNAL ;
    PORT
      LAYER M4 ;
        RECT  0 19.056 0.084 19.08 ;
    END
  END d[347]
  PIN d[348]
    DIRECTION INPUT ;
    USE SIGNAL ;
    PORT
      LAYER M4 ;
        RECT  0 19.152 0.084 19.176 ;
    END
  END d[348]
  PIN d[349]
    DIRECTION INPUT ;
    USE SIGNAL ;
    PORT
      LAYER M4 ;
        RECT  0 19.248 0.084 19.272 ;
    END
  END d[349]
  PIN d[34]
    DIRECTION INPUT ;
    USE SIGNAL ;
    PORT
      LAYER M4 ;
        RECT  0 42 0.084 42.024 ;
    END
  END d[34]
  PIN d[350]
    DIRECTION INPUT ;
    USE SIGNAL ;
    PORT
      LAYER M4 ;
        RECT  0 19.344 0.084 19.368 ;
    END
  END d[350]
  PIN d[351]
    DIRECTION INPUT ;
    USE SIGNAL ;
    PORT
      LAYER M4 ;
        RECT  0 19.44 0.084 19.464 ;
    END
  END d[351]
  PIN d[352]
    DIRECTION INPUT ;
    USE SIGNAL ;
    PORT
      LAYER M4 ;
        RECT  0 45.648 0.084 45.672 ;
    END
  END d[352]
  PIN d[353]
    DIRECTION INPUT ;
    USE SIGNAL ;
    PORT
      LAYER M4 ;
        RECT  0 45.744 0.084 45.768 ;
    END
  END d[353]
  PIN d[354]
    DIRECTION INPUT ;
    USE SIGNAL ;
    PORT
      LAYER M4 ;
        RECT  0 45.84 0.084 45.864 ;
    END
  END d[354]
  PIN d[355]
    DIRECTION INPUT ;
    USE SIGNAL ;
    PORT
      LAYER M4 ;
        RECT  0 45.936 0.084 45.96 ;
    END
  END d[355]
  PIN d[356]
    DIRECTION INPUT ;
    USE SIGNAL ;
    PORT
      LAYER M4 ;
        RECT  0 46.032 0.084 46.056 ;
    END
  END d[356]
  PIN d[357]
    DIRECTION INPUT ;
    USE SIGNAL ;
    PORT
      LAYER M4 ;
        RECT  0 46.128 0.084 46.152 ;
    END
  END d[357]
  PIN d[358]
    DIRECTION INPUT ;
    USE SIGNAL ;
    PORT
      LAYER M4 ;
        RECT  0 46.224 0.084 46.248 ;
    END
  END d[358]
  PIN d[359]
    DIRECTION INPUT ;
    USE SIGNAL ;
    PORT
      LAYER M4 ;
        RECT  0 46.32 0.084 46.344 ;
    END
  END d[359]
  PIN d[35]
    DIRECTION INPUT ;
    USE SIGNAL ;
    PORT
      LAYER M4 ;
        RECT  0 42.096 0.084 42.12 ;
    END
  END d[35]
  PIN d[360]
    DIRECTION INPUT ;
    USE SIGNAL ;
    PORT
      LAYER M4 ;
        RECT  0 46.416 0.084 46.44 ;
    END
  END d[360]
  PIN d[361]
    DIRECTION INPUT ;
    USE SIGNAL ;
    PORT
      LAYER M4 ;
        RECT  0 46.512 0.084 46.536 ;
    END
  END d[361]
  PIN d[362]
    DIRECTION INPUT ;
    USE SIGNAL ;
    PORT
      LAYER M4 ;
        RECT  0 46.608 0.084 46.632 ;
    END
  END d[362]
  PIN d[363]
    DIRECTION INPUT ;
    USE SIGNAL ;
    PORT
      LAYER M4 ;
        RECT  0 46.704 0.084 46.728 ;
    END
  END d[363]
  PIN d[364]
    DIRECTION INPUT ;
    USE SIGNAL ;
    PORT
      LAYER M4 ;
        RECT  0 46.8 0.084 46.824 ;
    END
  END d[364]
  PIN d[365]
    DIRECTION INPUT ;
    USE SIGNAL ;
    PORT
      LAYER M4 ;
        RECT  0 46.896 0.084 46.92 ;
    END
  END d[365]
  PIN d[366]
    DIRECTION INPUT ;
    USE SIGNAL ;
    PORT
      LAYER M4 ;
        RECT  0 46.992 0.084 47.016 ;
    END
  END d[366]
  PIN d[367]
    DIRECTION INPUT ;
    USE SIGNAL ;
    PORT
      LAYER M4 ;
        RECT  0 47.088 0.084 47.112 ;
    END
  END d[367]
  PIN d[368]
    DIRECTION INPUT ;
    USE SIGNAL ;
    PORT
      LAYER M4 ;
        RECT  0 47.184 0.084 47.208 ;
    END
  END d[368]
  PIN d[369]
    DIRECTION INPUT ;
    USE SIGNAL ;
    PORT
      LAYER M4 ;
        RECT  0 47.28 0.084 47.304 ;
    END
  END d[369]
  PIN d[36]
    DIRECTION INPUT ;
    USE SIGNAL ;
    PORT
      LAYER M4 ;
        RECT  0 42.192 0.084 42.216 ;
    END
  END d[36]
  PIN d[370]
    DIRECTION INPUT ;
    USE SIGNAL ;
    PORT
      LAYER M4 ;
        RECT  0 47.376 0.084 47.4 ;
    END
  END d[370]
  PIN d[371]
    DIRECTION INPUT ;
    USE SIGNAL ;
    PORT
      LAYER M4 ;
        RECT  0 47.472 0.084 47.496 ;
    END
  END d[371]
  PIN d[372]
    DIRECTION INPUT ;
    USE SIGNAL ;
    PORT
      LAYER M4 ;
        RECT  0 47.568 0.084 47.592 ;
    END
  END d[372]
  PIN d[373]
    DIRECTION INPUT ;
    USE SIGNAL ;
    PORT
      LAYER M4 ;
        RECT  0 47.664 0.084 47.688 ;
    END
  END d[373]
  PIN d[374]
    DIRECTION INPUT ;
    USE SIGNAL ;
    PORT
      LAYER M4 ;
        RECT  0 47.76 0.084 47.784 ;
    END
  END d[374]
  PIN d[375]
    DIRECTION INPUT ;
    USE SIGNAL ;
    PORT
      LAYER M4 ;
        RECT  0 47.856 0.084 47.88 ;
    END
  END d[375]
  PIN d[376]
    DIRECTION INPUT ;
    USE SIGNAL ;
    PORT
      LAYER M4 ;
        RECT  0 47.952 0.084 47.976 ;
    END
  END d[376]
  PIN d[377]
    DIRECTION INPUT ;
    USE SIGNAL ;
    PORT
      LAYER M4 ;
        RECT  0 48.048 0.084 48.072 ;
    END
  END d[377]
  PIN d[378]
    DIRECTION INPUT ;
    USE SIGNAL ;
    PORT
      LAYER M4 ;
        RECT  0 48.144 0.084 48.168 ;
    END
  END d[378]
  PIN d[379]
    DIRECTION INPUT ;
    USE SIGNAL ;
    PORT
      LAYER M4 ;
        RECT  0 48.24 0.084 48.264 ;
    END
  END d[379]
  PIN d[37]
    DIRECTION INPUT ;
    USE SIGNAL ;
    PORT
      LAYER M4 ;
        RECT  0 42.288 0.084 42.312 ;
    END
  END d[37]
  PIN d[380]
    DIRECTION INPUT ;
    USE SIGNAL ;
    PORT
      LAYER M4 ;
        RECT  0 48.336 0.084 48.36 ;
    END
  END d[380]
  PIN d[381]
    DIRECTION INPUT ;
    USE SIGNAL ;
    PORT
      LAYER M4 ;
        RECT  0 48.432 0.084 48.456 ;
    END
  END d[381]
  PIN d[382]
    DIRECTION INPUT ;
    USE SIGNAL ;
    PORT
      LAYER M4 ;
        RECT  0 48.528 0.084 48.552 ;
    END
  END d[382]
  PIN d[383]
    DIRECTION INPUT ;
    USE SIGNAL ;
    PORT
      LAYER M4 ;
        RECT  0 48.624 0.084 48.648 ;
    END
  END d[383]
  PIN d[384]
    DIRECTION INPUT ;
    USE SIGNAL ;
    PORT
      LAYER M4 ;
        RECT  0 48.72 0.084 48.744 ;
    END
  END d[384]
  PIN d[385]
    DIRECTION INPUT ;
    USE SIGNAL ;
    PORT
      LAYER M4 ;
        RECT  0 48.816 0.084 48.84 ;
    END
  END d[385]
  PIN d[386]
    DIRECTION INPUT ;
    USE SIGNAL ;
    PORT
      LAYER M4 ;
        RECT  0 48.912 0.084 48.936 ;
    END
  END d[386]
  PIN d[387]
    DIRECTION INPUT ;
    USE SIGNAL ;
    PORT
      LAYER M4 ;
        RECT  0 49.008 0.084 49.032 ;
    END
  END d[387]
  PIN d[388]
    DIRECTION INPUT ;
    USE SIGNAL ;
    PORT
      LAYER M4 ;
        RECT  0 49.104 0.084 49.128 ;
    END
  END d[388]
  PIN d[389]
    DIRECTION INPUT ;
    USE SIGNAL ;
    PORT
      LAYER M4 ;
        RECT  0 49.2 0.084 49.224 ;
    END
  END d[389]
  PIN d[38]
    DIRECTION INPUT ;
    USE SIGNAL ;
    PORT
      LAYER M4 ;
        RECT  0 42.384 0.084 42.408 ;
    END
  END d[38]
  PIN d[390]
    DIRECTION INPUT ;
    USE SIGNAL ;
    PORT
      LAYER M4 ;
        RECT  0 49.296 0.084 49.32 ;
    END
  END d[390]
  PIN d[391]
    DIRECTION INPUT ;
    USE SIGNAL ;
    PORT
      LAYER M4 ;
        RECT  0 49.392 0.084 49.416 ;
    END
  END d[391]
  PIN d[392]
    DIRECTION INPUT ;
    USE SIGNAL ;
    PORT
      LAYER M4 ;
        RECT  0 49.488 0.084 49.512 ;
    END
  END d[392]
  PIN d[393]
    DIRECTION INPUT ;
    USE SIGNAL ;
    PORT
      LAYER M4 ;
        RECT  0 49.584 0.084 49.608 ;
    END
  END d[393]
  PIN d[394]
    DIRECTION INPUT ;
    USE SIGNAL ;
    PORT
      LAYER M4 ;
        RECT  0 49.68 0.084 49.704 ;
    END
  END d[394]
  PIN d[395]
    DIRECTION INPUT ;
    USE SIGNAL ;
    PORT
      LAYER M4 ;
        RECT  0 49.776 0.084 49.8 ;
    END
  END d[395]
  PIN d[396]
    DIRECTION INPUT ;
    USE SIGNAL ;
    PORT
      LAYER M4 ;
        RECT  0 49.872 0.084 49.896 ;
    END
  END d[396]
  PIN d[397]
    DIRECTION INPUT ;
    USE SIGNAL ;
    PORT
      LAYER M4 ;
        RECT  0 49.968 0.084 49.992 ;
    END
  END d[397]
  PIN d[398]
    DIRECTION INPUT ;
    USE SIGNAL ;
    PORT
      LAYER M4 ;
        RECT  0 50.064 0.084 50.088 ;
    END
  END d[398]
  PIN d[399]
    DIRECTION INPUT ;
    USE SIGNAL ;
    PORT
      LAYER M4 ;
        RECT  0 50.16 0.084 50.184 ;
    END
  END d[399]
  PIN d[39]
    DIRECTION INPUT ;
    USE SIGNAL ;
    PORT
      LAYER M4 ;
        RECT  0 42.48 0.084 42.504 ;
    END
  END d[39]
  PIN d[3]
    DIRECTION INPUT ;
    USE SIGNAL ;
    PORT
      LAYER M4 ;
        RECT  0 26.736 0.084 26.76 ;
    END
  END d[3]
  PIN d[400]
    DIRECTION INPUT ;
    USE SIGNAL ;
    PORT
      LAYER M4 ;
        RECT  0 50.256 0.084 50.28 ;
    END
  END d[400]
  PIN d[401]
    DIRECTION INPUT ;
    USE SIGNAL ;
    PORT
      LAYER M4 ;
        RECT  0 50.352 0.084 50.376 ;
    END
  END d[401]
  PIN d[402]
    DIRECTION INPUT ;
    USE SIGNAL ;
    PORT
      LAYER M4 ;
        RECT  0 50.448 0.084 50.472 ;
    END
  END d[402]
  PIN d[403]
    DIRECTION INPUT ;
    USE SIGNAL ;
    PORT
      LAYER M4 ;
        RECT  0 50.544 0.084 50.568 ;
    END
  END d[403]
  PIN d[404]
    DIRECTION INPUT ;
    USE SIGNAL ;
    PORT
      LAYER M4 ;
        RECT  0 50.64 0.084 50.664 ;
    END
  END d[404]
  PIN d[405]
    DIRECTION INPUT ;
    USE SIGNAL ;
    PORT
      LAYER M4 ;
        RECT  0 50.736 0.084 50.76 ;
    END
  END d[405]
  PIN d[406]
    DIRECTION INPUT ;
    USE SIGNAL ;
    PORT
      LAYER M4 ;
        RECT  0 50.832 0.084 50.856 ;
    END
  END d[406]
  PIN d[407]
    DIRECTION INPUT ;
    USE SIGNAL ;
    PORT
      LAYER M4 ;
        RECT  0 50.928 0.084 50.952 ;
    END
  END d[407]
  PIN d[408]
    DIRECTION INPUT ;
    USE SIGNAL ;
    PORT
      LAYER M4 ;
        RECT  0 51.024 0.084 51.048 ;
    END
  END d[408]
  PIN d[409]
    DIRECTION INPUT ;
    USE SIGNAL ;
    PORT
      LAYER M4 ;
        RECT  0 51.12 0.084 51.144 ;
    END
  END d[409]
  PIN d[40]
    DIRECTION INPUT ;
    USE SIGNAL ;
    PORT
      LAYER M4 ;
        RECT  0 42.576 0.084 42.6 ;
    END
  END d[40]
  PIN d[410]
    DIRECTION INPUT ;
    USE SIGNAL ;
    PORT
      LAYER M4 ;
        RECT  0 51.216 0.084 51.24 ;
    END
  END d[410]
  PIN d[411]
    DIRECTION INPUT ;
    USE SIGNAL ;
    PORT
      LAYER M4 ;
        RECT  0 51.312 0.084 51.336 ;
    END
  END d[411]
  PIN d[412]
    DIRECTION INPUT ;
    USE SIGNAL ;
    PORT
      LAYER M4 ;
        RECT  0 51.408 0.084 51.432 ;
    END
  END d[412]
  PIN d[413]
    DIRECTION INPUT ;
    USE SIGNAL ;
    PORT
      LAYER M4 ;
        RECT  0 51.504 0.084 51.528 ;
    END
  END d[413]
  PIN d[414]
    DIRECTION INPUT ;
    USE SIGNAL ;
    PORT
      LAYER M4 ;
        RECT  0 51.6 0.084 51.624 ;
    END
  END d[414]
  PIN d[415]
    DIRECTION INPUT ;
    USE SIGNAL ;
    PORT
      LAYER M4 ;
        RECT  0 51.696 0.084 51.72 ;
    END
  END d[415]
  PIN d[416]
    DIRECTION INPUT ;
    USE SIGNAL ;
    PORT
      LAYER M4 ;
        RECT  0 22.608 0.084 22.632 ;
    END
  END d[416]
  PIN d[417]
    DIRECTION INPUT ;
    USE SIGNAL ;
    PORT
      LAYER M4 ;
        RECT  0 22.704 0.084 22.728 ;
    END
  END d[417]
  PIN d[418]
    DIRECTION INPUT ;
    USE SIGNAL ;
    PORT
      LAYER M4 ;
        RECT  0 22.8 0.084 22.824 ;
    END
  END d[418]
  PIN d[419]
    DIRECTION INPUT ;
    USE SIGNAL ;
    PORT
      LAYER M4 ;
        RECT  0 22.896 0.084 22.92 ;
    END
  END d[419]
  PIN d[41]
    DIRECTION INPUT ;
    USE SIGNAL ;
    PORT
      LAYER M4 ;
        RECT  0 42.672 0.084 42.696 ;
    END
  END d[41]
  PIN d[420]
    DIRECTION INPUT ;
    USE SIGNAL ;
    PORT
      LAYER M4 ;
        RECT  0 22.992 0.084 23.016 ;
    END
  END d[420]
  PIN d[421]
    DIRECTION INPUT ;
    USE SIGNAL ;
    PORT
      LAYER M4 ;
        RECT  0 23.088 0.084 23.112 ;
    END
  END d[421]
  PIN d[422]
    DIRECTION INPUT ;
    USE SIGNAL ;
    PORT
      LAYER M4 ;
        RECT  0 23.184 0.084 23.208 ;
    END
  END d[422]
  PIN d[423]
    DIRECTION INPUT ;
    USE SIGNAL ;
    PORT
      LAYER M4 ;
        RECT  0 23.28 0.084 23.304 ;
    END
  END d[423]
  PIN d[424]
    DIRECTION INPUT ;
    USE SIGNAL ;
    PORT
      LAYER M4 ;
        RECT  0 23.376 0.084 23.4 ;
    END
  END d[424]
  PIN d[425]
    DIRECTION INPUT ;
    USE SIGNAL ;
    PORT
      LAYER M4 ;
        RECT  0 23.472 0.084 23.496 ;
    END
  END d[425]
  PIN d[426]
    DIRECTION INPUT ;
    USE SIGNAL ;
    PORT
      LAYER M4 ;
        RECT  0 23.568 0.084 23.592 ;
    END
  END d[426]
  PIN d[427]
    DIRECTION INPUT ;
    USE SIGNAL ;
    PORT
      LAYER M4 ;
        RECT  0 23.664 0.084 23.688 ;
    END
  END d[427]
  PIN d[428]
    DIRECTION INPUT ;
    USE SIGNAL ;
    PORT
      LAYER M4 ;
        RECT  0 23.76 0.084 23.784 ;
    END
  END d[428]
  PIN d[429]
    DIRECTION INPUT ;
    USE SIGNAL ;
    PORT
      LAYER M4 ;
        RECT  0 23.856 0.084 23.88 ;
    END
  END d[429]
  PIN d[42]
    DIRECTION INPUT ;
    USE SIGNAL ;
    PORT
      LAYER M4 ;
        RECT  0 42.768 0.084 42.792 ;
    END
  END d[42]
  PIN d[430]
    DIRECTION INPUT ;
    USE SIGNAL ;
    PORT
      LAYER M4 ;
        RECT  0 23.952 0.084 23.976 ;
    END
  END d[430]
  PIN d[431]
    DIRECTION INPUT ;
    USE SIGNAL ;
    PORT
      LAYER M4 ;
        RECT  0 24.048 0.084 24.072 ;
    END
  END d[431]
  PIN d[432]
    DIRECTION INPUT ;
    USE SIGNAL ;
    PORT
      LAYER M4 ;
        RECT  0 24.144 0.084 24.168 ;
    END
  END d[432]
  PIN d[433]
    DIRECTION INPUT ;
    USE SIGNAL ;
    PORT
      LAYER M4 ;
        RECT  0 24.24 0.084 24.264 ;
    END
  END d[433]
  PIN d[434]
    DIRECTION INPUT ;
    USE SIGNAL ;
    PORT
      LAYER M4 ;
        RECT  0 24.336 0.084 24.36 ;
    END
  END d[434]
  PIN d[435]
    DIRECTION INPUT ;
    USE SIGNAL ;
    PORT
      LAYER M4 ;
        RECT  0 24.432 0.084 24.456 ;
    END
  END d[435]
  PIN d[436]
    DIRECTION INPUT ;
    USE SIGNAL ;
    PORT
      LAYER M4 ;
        RECT  0 24.528 0.084 24.552 ;
    END
  END d[436]
  PIN d[437]
    DIRECTION INPUT ;
    USE SIGNAL ;
    PORT
      LAYER M4 ;
        RECT  0 24.624 0.084 24.648 ;
    END
  END d[437]
  PIN d[438]
    DIRECTION INPUT ;
    USE SIGNAL ;
    PORT
      LAYER M4 ;
        RECT  0 24.72 0.084 24.744 ;
    END
  END d[438]
  PIN d[439]
    DIRECTION INPUT ;
    USE SIGNAL ;
    PORT
      LAYER M4 ;
        RECT  0 24.816 0.084 24.84 ;
    END
  END d[439]
  PIN d[43]
    DIRECTION INPUT ;
    USE SIGNAL ;
    PORT
      LAYER M4 ;
        RECT  0 42.864 0.084 42.888 ;
    END
  END d[43]
  PIN d[440]
    DIRECTION INPUT ;
    USE SIGNAL ;
    PORT
      LAYER M4 ;
        RECT  0 24.912 0.084 24.936 ;
    END
  END d[440]
  PIN d[441]
    DIRECTION INPUT ;
    USE SIGNAL ;
    PORT
      LAYER M4 ;
        RECT  0 25.008 0.084 25.032 ;
    END
  END d[441]
  PIN d[442]
    DIRECTION INPUT ;
    USE SIGNAL ;
    PORT
      LAYER M4 ;
        RECT  0 25.104 0.084 25.128 ;
    END
  END d[442]
  PIN d[443]
    DIRECTION INPUT ;
    USE SIGNAL ;
    PORT
      LAYER M4 ;
        RECT  0 25.2 0.084 25.224 ;
    END
  END d[443]
  PIN d[444]
    DIRECTION INPUT ;
    USE SIGNAL ;
    PORT
      LAYER M4 ;
        RECT  0 25.296 0.084 25.32 ;
    END
  END d[444]
  PIN d[445]
    DIRECTION INPUT ;
    USE SIGNAL ;
    PORT
      LAYER M4 ;
        RECT  0 25.392 0.084 25.416 ;
    END
  END d[445]
  PIN d[446]
    DIRECTION INPUT ;
    USE SIGNAL ;
    PORT
      LAYER M4 ;
        RECT  0 25.488 0.084 25.512 ;
    END
  END d[446]
  PIN d[447]
    DIRECTION INPUT ;
    USE SIGNAL ;
    PORT
      LAYER M4 ;
        RECT  0 25.584 0.084 25.608 ;
    END
  END d[447]
  PIN d[448]
    DIRECTION INPUT ;
    USE SIGNAL ;
    PORT
      LAYER M4 ;
        RECT  0 10.32 0.084 10.344 ;
    END
  END d[448]
  PIN d[449]
    DIRECTION INPUT ;
    USE SIGNAL ;
    PORT
      LAYER M4 ;
        RECT  0 10.416 0.084 10.44 ;
    END
  END d[449]
  PIN d[44]
    DIRECTION INPUT ;
    USE SIGNAL ;
    PORT
      LAYER M4 ;
        RECT  0 42.96 0.084 42.984 ;
    END
  END d[44]
  PIN d[450]
    DIRECTION INPUT ;
    USE SIGNAL ;
    PORT
      LAYER M4 ;
        RECT  0 10.512 0.084 10.536 ;
    END
  END d[450]
  PIN d[451]
    DIRECTION INPUT ;
    USE SIGNAL ;
    PORT
      LAYER M4 ;
        RECT  0 10.608 0.084 10.632 ;
    END
  END d[451]
  PIN d[452]
    DIRECTION INPUT ;
    USE SIGNAL ;
    PORT
      LAYER M4 ;
        RECT  0 10.704 0.084 10.728 ;
    END
  END d[452]
  PIN d[453]
    DIRECTION INPUT ;
    USE SIGNAL ;
    PORT
      LAYER M4 ;
        RECT  0 10.8 0.084 10.824 ;
    END
  END d[453]
  PIN d[454]
    DIRECTION INPUT ;
    USE SIGNAL ;
    PORT
      LAYER M4 ;
        RECT  0 10.896 0.084 10.92 ;
    END
  END d[454]
  PIN d[455]
    DIRECTION INPUT ;
    USE SIGNAL ;
    PORT
      LAYER M4 ;
        RECT  0 10.992 0.084 11.016 ;
    END
  END d[455]
  PIN d[456]
    DIRECTION INPUT ;
    USE SIGNAL ;
    PORT
      LAYER M4 ;
        RECT  0 11.088 0.084 11.112 ;
    END
  END d[456]
  PIN d[457]
    DIRECTION INPUT ;
    USE SIGNAL ;
    PORT
      LAYER M4 ;
        RECT  0 11.184 0.084 11.208 ;
    END
  END d[457]
  PIN d[458]
    DIRECTION INPUT ;
    USE SIGNAL ;
    PORT
      LAYER M4 ;
        RECT  0 11.28 0.084 11.304 ;
    END
  END d[458]
  PIN d[459]
    DIRECTION INPUT ;
    USE SIGNAL ;
    PORT
      LAYER M4 ;
        RECT  0 11.376 0.084 11.4 ;
    END
  END d[459]
  PIN d[45]
    DIRECTION INPUT ;
    USE SIGNAL ;
    PORT
      LAYER M4 ;
        RECT  0 43.056 0.084 43.08 ;
    END
  END d[45]
  PIN d[460]
    DIRECTION INPUT ;
    USE SIGNAL ;
    PORT
      LAYER M4 ;
        RECT  0 11.472 0.084 11.496 ;
    END
  END d[460]
  PIN d[461]
    DIRECTION INPUT ;
    USE SIGNAL ;
    PORT
      LAYER M4 ;
        RECT  0 11.568 0.084 11.592 ;
    END
  END d[461]
  PIN d[462]
    DIRECTION INPUT ;
    USE SIGNAL ;
    PORT
      LAYER M4 ;
        RECT  0 11.664 0.084 11.688 ;
    END
  END d[462]
  PIN d[463]
    DIRECTION INPUT ;
    USE SIGNAL ;
    PORT
      LAYER M4 ;
        RECT  0 11.76 0.084 11.784 ;
    END
  END d[463]
  PIN d[464]
    DIRECTION INPUT ;
    USE SIGNAL ;
    PORT
      LAYER M4 ;
        RECT  0 11.856 0.084 11.88 ;
    END
  END d[464]
  PIN d[465]
    DIRECTION INPUT ;
    USE SIGNAL ;
    PORT
      LAYER M4 ;
        RECT  0 11.952 0.084 11.976 ;
    END
  END d[465]
  PIN d[466]
    DIRECTION INPUT ;
    USE SIGNAL ;
    PORT
      LAYER M4 ;
        RECT  0 12.048 0.084 12.072 ;
    END
  END d[466]
  PIN d[467]
    DIRECTION INPUT ;
    USE SIGNAL ;
    PORT
      LAYER M4 ;
        RECT  0 12.144 0.084 12.168 ;
    END
  END d[467]
  PIN d[468]
    DIRECTION INPUT ;
    USE SIGNAL ;
    PORT
      LAYER M4 ;
        RECT  0 12.24 0.084 12.264 ;
    END
  END d[468]
  PIN d[469]
    DIRECTION INPUT ;
    USE SIGNAL ;
    PORT
      LAYER M4 ;
        RECT  0 12.336 0.084 12.36 ;
    END
  END d[469]
  PIN d[46]
    DIRECTION INPUT ;
    USE SIGNAL ;
    PORT
      LAYER M4 ;
        RECT  0 43.152 0.084 43.176 ;
    END
  END d[46]
  PIN d[470]
    DIRECTION INPUT ;
    USE SIGNAL ;
    PORT
      LAYER M4 ;
        RECT  0 12.432 0.084 12.456 ;
    END
  END d[470]
  PIN d[471]
    DIRECTION INPUT ;
    USE SIGNAL ;
    PORT
      LAYER M4 ;
        RECT  0 12.528 0.084 12.552 ;
    END
  END d[471]
  PIN d[472]
    DIRECTION INPUT ;
    USE SIGNAL ;
    PORT
      LAYER M4 ;
        RECT  0 12.624 0.084 12.648 ;
    END
  END d[472]
  PIN d[473]
    DIRECTION INPUT ;
    USE SIGNAL ;
    PORT
      LAYER M4 ;
        RECT  0 12.72 0.084 12.744 ;
    END
  END d[473]
  PIN d[474]
    DIRECTION INPUT ;
    USE SIGNAL ;
    PORT
      LAYER M4 ;
        RECT  0 12.816 0.084 12.84 ;
    END
  END d[474]
  PIN d[475]
    DIRECTION INPUT ;
    USE SIGNAL ;
    PORT
      LAYER M4 ;
        RECT  0 12.912 0.084 12.936 ;
    END
  END d[475]
  PIN d[476]
    DIRECTION INPUT ;
    USE SIGNAL ;
    PORT
      LAYER M4 ;
        RECT  0 13.008 0.084 13.032 ;
    END
  END d[476]
  PIN d[477]
    DIRECTION INPUT ;
    USE SIGNAL ;
    PORT
      LAYER M4 ;
        RECT  0 13.104 0.084 13.128 ;
    END
  END d[477]
  PIN d[478]
    DIRECTION INPUT ;
    USE SIGNAL ;
    PORT
      LAYER M4 ;
        RECT  0 13.2 0.084 13.224 ;
    END
  END d[478]
  PIN d[479]
    DIRECTION INPUT ;
    USE SIGNAL ;
    PORT
      LAYER M4 ;
        RECT  0 13.296 0.084 13.32 ;
    END
  END d[479]
  PIN d[47]
    DIRECTION INPUT ;
    USE SIGNAL ;
    PORT
      LAYER M4 ;
        RECT  0 43.248 0.084 43.272 ;
    END
  END d[47]
  PIN d[480]
    DIRECTION INPUT ;
    USE SIGNAL ;
    PORT
      LAYER M4 ;
        RECT  0 19.536 0.084 19.56 ;
    END
  END d[480]
  PIN d[481]
    DIRECTION INPUT ;
    USE SIGNAL ;
    PORT
      LAYER M4 ;
        RECT  0 19.632 0.084 19.656 ;
    END
  END d[481]
  PIN d[482]
    DIRECTION INPUT ;
    USE SIGNAL ;
    PORT
      LAYER M4 ;
        RECT  0 19.728 0.084 19.752 ;
    END
  END d[482]
  PIN d[483]
    DIRECTION INPUT ;
    USE SIGNAL ;
    PORT
      LAYER M4 ;
        RECT  0 19.824 0.084 19.848 ;
    END
  END d[483]
  PIN d[484]
    DIRECTION INPUT ;
    USE SIGNAL ;
    PORT
      LAYER M4 ;
        RECT  0 19.92 0.084 19.944 ;
    END
  END d[484]
  PIN d[485]
    DIRECTION INPUT ;
    USE SIGNAL ;
    PORT
      LAYER M4 ;
        RECT  0 20.016 0.084 20.04 ;
    END
  END d[485]
  PIN d[486]
    DIRECTION INPUT ;
    USE SIGNAL ;
    PORT
      LAYER M4 ;
        RECT  0 20.112 0.084 20.136 ;
    END
  END d[486]
  PIN d[487]
    DIRECTION INPUT ;
    USE SIGNAL ;
    PORT
      LAYER M4 ;
        RECT  0 20.208 0.084 20.232 ;
    END
  END d[487]
  PIN d[488]
    DIRECTION INPUT ;
    USE SIGNAL ;
    PORT
      LAYER M4 ;
        RECT  0 20.304 0.084 20.328 ;
    END
  END d[488]
  PIN d[489]
    DIRECTION INPUT ;
    USE SIGNAL ;
    PORT
      LAYER M4 ;
        RECT  0 20.4 0.084 20.424 ;
    END
  END d[489]
  PIN d[48]
    DIRECTION INPUT ;
    USE SIGNAL ;
    PORT
      LAYER M4 ;
        RECT  0 43.344 0.084 43.368 ;
    END
  END d[48]
  PIN d[490]
    DIRECTION INPUT ;
    USE SIGNAL ;
    PORT
      LAYER M4 ;
        RECT  0 20.496 0.084 20.52 ;
    END
  END d[490]
  PIN d[491]
    DIRECTION INPUT ;
    USE SIGNAL ;
    PORT
      LAYER M4 ;
        RECT  0 20.592 0.084 20.616 ;
    END
  END d[491]
  PIN d[492]
    DIRECTION INPUT ;
    USE SIGNAL ;
    PORT
      LAYER M4 ;
        RECT  0 20.688 0.084 20.712 ;
    END
  END d[492]
  PIN d[493]
    DIRECTION INPUT ;
    USE SIGNAL ;
    PORT
      LAYER M4 ;
        RECT  0 20.784 0.084 20.808 ;
    END
  END d[493]
  PIN d[494]
    DIRECTION INPUT ;
    USE SIGNAL ;
    PORT
      LAYER M4 ;
        RECT  0 20.88 0.084 20.904 ;
    END
  END d[494]
  PIN d[495]
    DIRECTION INPUT ;
    USE SIGNAL ;
    PORT
      LAYER M4 ;
        RECT  0 20.976 0.084 21 ;
    END
  END d[495]
  PIN d[496]
    DIRECTION INPUT ;
    USE SIGNAL ;
    PORT
      LAYER M4 ;
        RECT  0 21.072 0.084 21.096 ;
    END
  END d[496]
  PIN d[497]
    DIRECTION INPUT ;
    USE SIGNAL ;
    PORT
      LAYER M4 ;
        RECT  0 21.168 0.084 21.192 ;
    END
  END d[497]
  PIN d[498]
    DIRECTION INPUT ;
    USE SIGNAL ;
    PORT
      LAYER M4 ;
        RECT  0 21.264 0.084 21.288 ;
    END
  END d[498]
  PIN d[499]
    DIRECTION INPUT ;
    USE SIGNAL ;
    PORT
      LAYER M4 ;
        RECT  0 21.36 0.084 21.384 ;
    END
  END d[499]
  PIN d[49]
    DIRECTION INPUT ;
    USE SIGNAL ;
    PORT
      LAYER M4 ;
        RECT  0 43.44 0.084 43.464 ;
    END
  END d[49]
  PIN d[4]
    DIRECTION INPUT ;
    USE SIGNAL ;
    PORT
      LAYER M4 ;
        RECT  0 26.832 0.084 26.856 ;
    END
  END d[4]
  PIN d[500]
    DIRECTION INPUT ;
    USE SIGNAL ;
    PORT
      LAYER M4 ;
        RECT  0 21.456 0.084 21.48 ;
    END
  END d[500]
  PIN d[501]
    DIRECTION INPUT ;
    USE SIGNAL ;
    PORT
      LAYER M4 ;
        RECT  0 21.552 0.084 21.576 ;
    END
  END d[501]
  PIN d[502]
    DIRECTION INPUT ;
    USE SIGNAL ;
    PORT
      LAYER M4 ;
        RECT  0 21.648 0.084 21.672 ;
    END
  END d[502]
  PIN d[503]
    DIRECTION INPUT ;
    USE SIGNAL ;
    PORT
      LAYER M4 ;
        RECT  0 21.744 0.084 21.768 ;
    END
  END d[503]
  PIN d[504]
    DIRECTION INPUT ;
    USE SIGNAL ;
    PORT
      LAYER M4 ;
        RECT  0 21.84 0.084 21.864 ;
    END
  END d[504]
  PIN d[505]
    DIRECTION INPUT ;
    USE SIGNAL ;
    PORT
      LAYER M4 ;
        RECT  0 21.936 0.084 21.96 ;
    END
  END d[505]
  PIN d[506]
    DIRECTION INPUT ;
    USE SIGNAL ;
    PORT
      LAYER M4 ;
        RECT  0 22.032 0.084 22.056 ;
    END
  END d[506]
  PIN d[507]
    DIRECTION INPUT ;
    USE SIGNAL ;
    PORT
      LAYER M4 ;
        RECT  0 22.128 0.084 22.152 ;
    END
  END d[507]
  PIN d[508]
    DIRECTION INPUT ;
    USE SIGNAL ;
    PORT
      LAYER M4 ;
        RECT  0 22.224 0.084 22.248 ;
    END
  END d[508]
  PIN d[509]
    DIRECTION INPUT ;
    USE SIGNAL ;
    PORT
      LAYER M4 ;
        RECT  0 22.32 0.084 22.344 ;
    END
  END d[509]
  PIN d[50]
    DIRECTION INPUT ;
    USE SIGNAL ;
    PORT
      LAYER M4 ;
        RECT  0 43.536 0.084 43.56 ;
    END
  END d[50]
  PIN d[510]
    DIRECTION INPUT ;
    USE SIGNAL ;
    PORT
      LAYER M4 ;
        RECT  0 22.416 0.084 22.44 ;
    END
  END d[510]
  PIN d[511]
    DIRECTION INPUT ;
    USE SIGNAL ;
    PORT
      LAYER M4 ;
        RECT  0 22.512 0.084 22.536 ;
    END
  END d[511]
  PIN d[51]
    DIRECTION INPUT ;
    USE SIGNAL ;
    PORT
      LAYER M4 ;
        RECT  0 43.632 0.084 43.656 ;
    END
  END d[51]
  PIN d[52]
    DIRECTION INPUT ;
    USE SIGNAL ;
    PORT
      LAYER M4 ;
        RECT  0 43.728 0.084 43.752 ;
    END
  END d[52]
  PIN d[53]
    DIRECTION INPUT ;
    USE SIGNAL ;
    PORT
      LAYER M4 ;
        RECT  0 43.824 0.084 43.848 ;
    END
  END d[53]
  PIN d[54]
    DIRECTION INPUT ;
    USE SIGNAL ;
    PORT
      LAYER M4 ;
        RECT  0 43.92 0.084 43.944 ;
    END
  END d[54]
  PIN d[55]
    DIRECTION INPUT ;
    USE SIGNAL ;
    PORT
      LAYER M4 ;
        RECT  0 44.016 0.084 44.04 ;
    END
  END d[55]
  PIN d[56]
    DIRECTION INPUT ;
    USE SIGNAL ;
    PORT
      LAYER M4 ;
        RECT  0 44.112 0.084 44.136 ;
    END
  END d[56]
  PIN d[57]
    DIRECTION INPUT ;
    USE SIGNAL ;
    PORT
      LAYER M4 ;
        RECT  0 44.208 0.084 44.232 ;
    END
  END d[57]
  PIN d[58]
    DIRECTION INPUT ;
    USE SIGNAL ;
    PORT
      LAYER M4 ;
        RECT  0 44.304 0.084 44.328 ;
    END
  END d[58]
  PIN d[59]
    DIRECTION INPUT ;
    USE SIGNAL ;
    PORT
      LAYER M4 ;
        RECT  0 44.4 0.084 44.424 ;
    END
  END d[59]
  PIN d[5]
    DIRECTION INPUT ;
    USE SIGNAL ;
    PORT
      LAYER M4 ;
        RECT  0 26.928 0.084 26.952 ;
    END
  END d[5]
  PIN d[60]
    DIRECTION INPUT ;
    USE SIGNAL ;
    PORT
      LAYER M4 ;
        RECT  0 44.496 0.084 44.52 ;
    END
  END d[60]
  PIN d[61]
    DIRECTION INPUT ;
    USE SIGNAL ;
    PORT
      LAYER M4 ;
        RECT  0 44.592 0.084 44.616 ;
    END
  END d[61]
  PIN d[62]
    DIRECTION INPUT ;
    USE SIGNAL ;
    PORT
      LAYER M4 ;
        RECT  0 44.688 0.084 44.712 ;
    END
  END d[62]
  PIN d[63]
    DIRECTION INPUT ;
    USE SIGNAL ;
    PORT
      LAYER M4 ;
        RECT  0 44.784 0.084 44.808 ;
    END
  END d[63]
  PIN d[64]
    DIRECTION INPUT ;
    USE SIGNAL ;
    PORT
      LAYER M4 ;
        RECT  0 29.52 0.084 29.544 ;
    END
  END d[64]
  PIN d[65]
    DIRECTION INPUT ;
    USE SIGNAL ;
    PORT
      LAYER M4 ;
        RECT  0 29.616 0.084 29.64 ;
    END
  END d[65]
  PIN d[66]
    DIRECTION INPUT ;
    USE SIGNAL ;
    PORT
      LAYER M4 ;
        RECT  0 29.712 0.084 29.736 ;
    END
  END d[66]
  PIN d[67]
    DIRECTION INPUT ;
    USE SIGNAL ;
    PORT
      LAYER M4 ;
        RECT  0 29.808 0.084 29.832 ;
    END
  END d[67]
  PIN d[68]
    DIRECTION INPUT ;
    USE SIGNAL ;
    PORT
      LAYER M4 ;
        RECT  0 29.904 0.084 29.928 ;
    END
  END d[68]
  PIN d[69]
    DIRECTION INPUT ;
    USE SIGNAL ;
    PORT
      LAYER M4 ;
        RECT  0 30 0.084 30.024 ;
    END
  END d[69]
  PIN d[6]
    DIRECTION INPUT ;
    USE SIGNAL ;
    PORT
      LAYER M4 ;
        RECT  0 27.024 0.084 27.048 ;
    END
  END d[6]
  PIN d[70]
    DIRECTION INPUT ;
    USE SIGNAL ;
    PORT
      LAYER M4 ;
        RECT  0 30.096 0.084 30.12 ;
    END
  END d[70]
  PIN d[71]
    DIRECTION INPUT ;
    USE SIGNAL ;
    PORT
      LAYER M4 ;
        RECT  0 30.192 0.084 30.216 ;
    END
  END d[71]
  PIN d[72]
    DIRECTION INPUT ;
    USE SIGNAL ;
    PORT
      LAYER M4 ;
        RECT  0 30.288 0.084 30.312 ;
    END
  END d[72]
  PIN d[73]
    DIRECTION INPUT ;
    USE SIGNAL ;
    PORT
      LAYER M4 ;
        RECT  0 30.384 0.084 30.408 ;
    END
  END d[73]
  PIN d[74]
    DIRECTION INPUT ;
    USE SIGNAL ;
    PORT
      LAYER M4 ;
        RECT  0 30.48 0.084 30.504 ;
    END
  END d[74]
  PIN d[75]
    DIRECTION INPUT ;
    USE SIGNAL ;
    PORT
      LAYER M4 ;
        RECT  0 30.576 0.084 30.6 ;
    END
  END d[75]
  PIN d[76]
    DIRECTION INPUT ;
    USE SIGNAL ;
    PORT
      LAYER M4 ;
        RECT  0 30.672 0.084 30.696 ;
    END
  END d[76]
  PIN d[77]
    DIRECTION INPUT ;
    USE SIGNAL ;
    PORT
      LAYER M4 ;
        RECT  0 30.768 0.084 30.792 ;
    END
  END d[77]
  PIN d[78]
    DIRECTION INPUT ;
    USE SIGNAL ;
    PORT
      LAYER M4 ;
        RECT  0 30.864 0.084 30.888 ;
    END
  END d[78]
  PIN d[79]
    DIRECTION INPUT ;
    USE SIGNAL ;
    PORT
      LAYER M4 ;
        RECT  0 30.96 0.084 30.984 ;
    END
  END d[79]
  PIN d[7]
    DIRECTION INPUT ;
    USE SIGNAL ;
    PORT
      LAYER M4 ;
        RECT  0 27.12 0.084 27.144 ;
    END
  END d[7]
  PIN d[80]
    DIRECTION INPUT ;
    USE SIGNAL ;
    PORT
      LAYER M4 ;
        RECT  0 31.056 0.084 31.08 ;
    END
  END d[80]
  PIN d[81]
    DIRECTION INPUT ;
    USE SIGNAL ;
    PORT
      LAYER M4 ;
        RECT  0 31.152 0.084 31.176 ;
    END
  END d[81]
  PIN d[82]
    DIRECTION INPUT ;
    USE SIGNAL ;
    PORT
      LAYER M4 ;
        RECT  0 31.248 0.084 31.272 ;
    END
  END d[82]
  PIN d[83]
    DIRECTION INPUT ;
    USE SIGNAL ;
    PORT
      LAYER M4 ;
        RECT  0 31.344 0.084 31.368 ;
    END
  END d[83]
  PIN d[84]
    DIRECTION INPUT ;
    USE SIGNAL ;
    PORT
      LAYER M4 ;
        RECT  0 31.44 0.084 31.464 ;
    END
  END d[84]
  PIN d[85]
    DIRECTION INPUT ;
    USE SIGNAL ;
    PORT
      LAYER M4 ;
        RECT  0 31.536 0.084 31.56 ;
    END
  END d[85]
  PIN d[86]
    DIRECTION INPUT ;
    USE SIGNAL ;
    PORT
      LAYER M4 ;
        RECT  0 31.632 0.084 31.656 ;
    END
  END d[86]
  PIN d[87]
    DIRECTION INPUT ;
    USE SIGNAL ;
    PORT
      LAYER M4 ;
        RECT  0 31.728 0.084 31.752 ;
    END
  END d[87]
  PIN d[88]
    DIRECTION INPUT ;
    USE SIGNAL ;
    PORT
      LAYER M4 ;
        RECT  0 31.824 0.084 31.848 ;
    END
  END d[88]
  PIN d[89]
    DIRECTION INPUT ;
    USE SIGNAL ;
    PORT
      LAYER M4 ;
        RECT  0 31.92 0.084 31.944 ;
    END
  END d[89]
  PIN d[8]
    DIRECTION INPUT ;
    USE SIGNAL ;
    PORT
      LAYER M4 ;
        RECT  0 27.216 0.084 27.24 ;
    END
  END d[8]
  PIN d[90]
    DIRECTION INPUT ;
    USE SIGNAL ;
    PORT
      LAYER M4 ;
        RECT  0 32.016 0.084 32.04 ;
    END
  END d[90]
  PIN d[91]
    DIRECTION INPUT ;
    USE SIGNAL ;
    PORT
      LAYER M4 ;
        RECT  0 32.112 0.084 32.136 ;
    END
  END d[91]
  PIN d[92]
    DIRECTION INPUT ;
    USE SIGNAL ;
    PORT
      LAYER M4 ;
        RECT  0 32.208 0.084 32.232 ;
    END
  END d[92]
  PIN d[93]
    DIRECTION INPUT ;
    USE SIGNAL ;
    PORT
      LAYER M4 ;
        RECT  0 32.304 0.084 32.328 ;
    END
  END d[93]
  PIN d[94]
    DIRECTION INPUT ;
    USE SIGNAL ;
    PORT
      LAYER M4 ;
        RECT  0 32.4 0.084 32.424 ;
    END
  END d[94]
  PIN d[95]
    DIRECTION INPUT ;
    USE SIGNAL ;
    PORT
      LAYER M4 ;
        RECT  0 32.496 0.084 32.52 ;
    END
  END d[95]
  PIN d[96]
    DIRECTION INPUT ;
    USE SIGNAL ;
    PORT
      LAYER M4 ;
        RECT  0 32.592 0.084 32.616 ;
    END
  END d[96]
  PIN d[97]
    DIRECTION INPUT ;
    USE SIGNAL ;
    PORT
      LAYER M4 ;
        RECT  0 32.688 0.084 32.712 ;
    END
  END d[97]
  PIN d[98]
    DIRECTION INPUT ;
    USE SIGNAL ;
    PORT
      LAYER M4 ;
        RECT  0 32.784 0.084 32.808 ;
    END
  END d[98]
  PIN d[99]
    DIRECTION INPUT ;
    USE SIGNAL ;
    PORT
      LAYER M4 ;
        RECT  0 32.88 0.084 32.904 ;
    END
  END d[99]
  PIN d[9]
    DIRECTION INPUT ;
    USE SIGNAL ;
    PORT
      LAYER M4 ;
        RECT  0 27.312 0.084 27.336 ;
    END
  END d[9]
  PIN q[0]
    DIRECTION OUTPUT ;
    USE SIGNAL ;
    PORT
      LAYER M4 ;
        RECT  27.996 19.92 28.08 19.944 ;
    END
  END q[0]
  PIN q[100]
    DIRECTION OUTPUT ;
    USE SIGNAL ;
    PORT
      LAYER M4 ;
        RECT  27.996 26.448 28.08 26.472 ;
    END
  END q[100]
  PIN q[101]
    DIRECTION OUTPUT ;
    USE SIGNAL ;
    PORT
      LAYER M4 ;
        RECT  27.996 26.544 28.08 26.568 ;
    END
  END q[101]
  PIN q[102]
    DIRECTION OUTPUT ;
    USE SIGNAL ;
    PORT
      LAYER M4 ;
        RECT  27.996 26.64 28.08 26.664 ;
    END
  END q[102]
  PIN q[103]
    DIRECTION OUTPUT ;
    USE SIGNAL ;
    PORT
      LAYER M4 ;
        RECT  27.996 26.736 28.08 26.76 ;
    END
  END q[103]
  PIN q[104]
    DIRECTION OUTPUT ;
    USE SIGNAL ;
    PORT
      LAYER M4 ;
        RECT  27.996 26.832 28.08 26.856 ;
    END
  END q[104]
  PIN q[105]
    DIRECTION OUTPUT ;
    USE SIGNAL ;
    PORT
      LAYER M4 ;
        RECT  27.996 26.928 28.08 26.952 ;
    END
  END q[105]
  PIN q[106]
    DIRECTION OUTPUT ;
    USE SIGNAL ;
    PORT
      LAYER M4 ;
        RECT  27.996 27.024 28.08 27.048 ;
    END
  END q[106]
  PIN q[107]
    DIRECTION OUTPUT ;
    USE SIGNAL ;
    PORT
      LAYER M4 ;
        RECT  27.996 27.12 28.08 27.144 ;
    END
  END q[107]
  PIN q[108]
    DIRECTION OUTPUT ;
    USE SIGNAL ;
    PORT
      LAYER M4 ;
        RECT  27.996 27.216 28.08 27.24 ;
    END
  END q[108]
  PIN q[109]
    DIRECTION OUTPUT ;
    USE SIGNAL ;
    PORT
      LAYER M4 ;
        RECT  27.996 27.312 28.08 27.336 ;
    END
  END q[109]
  PIN q[10]
    DIRECTION OUTPUT ;
    USE SIGNAL ;
    PORT
      LAYER M4 ;
        RECT  27.996 20.88 28.08 20.904 ;
    END
  END q[10]
  PIN q[110]
    DIRECTION OUTPUT ;
    USE SIGNAL ;
    PORT
      LAYER M4 ;
        RECT  27.996 27.408 28.08 27.432 ;
    END
  END q[110]
  PIN q[111]
    DIRECTION OUTPUT ;
    USE SIGNAL ;
    PORT
      LAYER M4 ;
        RECT  27.996 27.504 28.08 27.528 ;
    END
  END q[111]
  PIN q[112]
    DIRECTION OUTPUT ;
    USE SIGNAL ;
    PORT
      LAYER M4 ;
        RECT  27.996 27.6 28.08 27.624 ;
    END
  END q[112]
  PIN q[113]
    DIRECTION OUTPUT ;
    USE SIGNAL ;
    PORT
      LAYER M4 ;
        RECT  27.996 27.696 28.08 27.72 ;
    END
  END q[113]
  PIN q[114]
    DIRECTION OUTPUT ;
    USE SIGNAL ;
    PORT
      LAYER M4 ;
        RECT  27.996 27.792 28.08 27.816 ;
    END
  END q[114]
  PIN q[115]
    DIRECTION OUTPUT ;
    USE SIGNAL ;
    PORT
      LAYER M4 ;
        RECT  27.996 27.888 28.08 27.912 ;
    END
  END q[115]
  PIN q[116]
    DIRECTION OUTPUT ;
    USE SIGNAL ;
    PORT
      LAYER M4 ;
        RECT  27.996 27.984 28.08 28.008 ;
    END
  END q[116]
  PIN q[117]
    DIRECTION OUTPUT ;
    USE SIGNAL ;
    PORT
      LAYER M4 ;
        RECT  27.996 28.08 28.08 28.104 ;
    END
  END q[117]
  PIN q[118]
    DIRECTION OUTPUT ;
    USE SIGNAL ;
    PORT
      LAYER M4 ;
        RECT  27.996 28.176 28.08 28.2 ;
    END
  END q[118]
  PIN q[119]
    DIRECTION OUTPUT ;
    USE SIGNAL ;
    PORT
      LAYER M4 ;
        RECT  27.996 28.272 28.08 28.296 ;
    END
  END q[119]
  PIN q[11]
    DIRECTION OUTPUT ;
    USE SIGNAL ;
    PORT
      LAYER M4 ;
        RECT  27.996 20.976 28.08 21 ;
    END
  END q[11]
  PIN q[120]
    DIRECTION OUTPUT ;
    USE SIGNAL ;
    PORT
      LAYER M4 ;
        RECT  27.996 28.368 28.08 28.392 ;
    END
  END q[120]
  PIN q[121]
    DIRECTION OUTPUT ;
    USE SIGNAL ;
    PORT
      LAYER M4 ;
        RECT  27.996 28.464 28.08 28.488 ;
    END
  END q[121]
  PIN q[122]
    DIRECTION OUTPUT ;
    USE SIGNAL ;
    PORT
      LAYER M4 ;
        RECT  27.996 28.56 28.08 28.584 ;
    END
  END q[122]
  PIN q[123]
    DIRECTION OUTPUT ;
    USE SIGNAL ;
    PORT
      LAYER M4 ;
        RECT  27.996 28.656 28.08 28.68 ;
    END
  END q[123]
  PIN q[124]
    DIRECTION OUTPUT ;
    USE SIGNAL ;
    PORT
      LAYER M4 ;
        RECT  27.996 28.752 28.08 28.776 ;
    END
  END q[124]
  PIN q[125]
    DIRECTION OUTPUT ;
    USE SIGNAL ;
    PORT
      LAYER M4 ;
        RECT  27.996 28.848 28.08 28.872 ;
    END
  END q[125]
  PIN q[126]
    DIRECTION OUTPUT ;
    USE SIGNAL ;
    PORT
      LAYER M4 ;
        RECT  27.996 28.944 28.08 28.968 ;
    END
  END q[126]
  PIN q[127]
    DIRECTION OUTPUT ;
    USE SIGNAL ;
    PORT
      LAYER M4 ;
        RECT  27.996 29.04 28.08 29.064 ;
    END
  END q[127]
  PIN q[128]
    DIRECTION OUTPUT ;
    USE SIGNAL ;
    PORT
      LAYER M4 ;
        RECT  27.996 32.208 28.08 32.232 ;
    END
  END q[128]
  PIN q[129]
    DIRECTION OUTPUT ;
    USE SIGNAL ;
    PORT
      LAYER M4 ;
        RECT  27.996 32.304 28.08 32.328 ;
    END
  END q[129]
  PIN q[12]
    DIRECTION OUTPUT ;
    USE SIGNAL ;
    PORT
      LAYER M4 ;
        RECT  27.996 21.072 28.08 21.096 ;
    END
  END q[12]
  PIN q[130]
    DIRECTION OUTPUT ;
    USE SIGNAL ;
    PORT
      LAYER M4 ;
        RECT  27.996 32.4 28.08 32.424 ;
    END
  END q[130]
  PIN q[131]
    DIRECTION OUTPUT ;
    USE SIGNAL ;
    PORT
      LAYER M4 ;
        RECT  27.996 32.496 28.08 32.52 ;
    END
  END q[131]
  PIN q[132]
    DIRECTION OUTPUT ;
    USE SIGNAL ;
    PORT
      LAYER M4 ;
        RECT  27.996 32.592 28.08 32.616 ;
    END
  END q[132]
  PIN q[133]
    DIRECTION OUTPUT ;
    USE SIGNAL ;
    PORT
      LAYER M4 ;
        RECT  27.996 32.688 28.08 32.712 ;
    END
  END q[133]
  PIN q[134]
    DIRECTION OUTPUT ;
    USE SIGNAL ;
    PORT
      LAYER M4 ;
        RECT  27.996 32.784 28.08 32.808 ;
    END
  END q[134]
  PIN q[135]
    DIRECTION OUTPUT ;
    USE SIGNAL ;
    PORT
      LAYER M4 ;
        RECT  27.996 32.88 28.08 32.904 ;
    END
  END q[135]
  PIN q[136]
    DIRECTION OUTPUT ;
    USE SIGNAL ;
    PORT
      LAYER M4 ;
        RECT  27.996 32.976 28.08 33 ;
    END
  END q[136]
  PIN q[137]
    DIRECTION OUTPUT ;
    USE SIGNAL ;
    PORT
      LAYER M4 ;
        RECT  27.996 33.072 28.08 33.096 ;
    END
  END q[137]
  PIN q[138]
    DIRECTION OUTPUT ;
    USE SIGNAL ;
    PORT
      LAYER M4 ;
        RECT  27.996 33.168 28.08 33.192 ;
    END
  END q[138]
  PIN q[139]
    DIRECTION OUTPUT ;
    USE SIGNAL ;
    PORT
      LAYER M4 ;
        RECT  27.996 33.264 28.08 33.288 ;
    END
  END q[139]
  PIN q[13]
    DIRECTION OUTPUT ;
    USE SIGNAL ;
    PORT
      LAYER M4 ;
        RECT  27.996 21.168 28.08 21.192 ;
    END
  END q[13]
  PIN q[140]
    DIRECTION OUTPUT ;
    USE SIGNAL ;
    PORT
      LAYER M4 ;
        RECT  27.996 33.36 28.08 33.384 ;
    END
  END q[140]
  PIN q[141]
    DIRECTION OUTPUT ;
    USE SIGNAL ;
    PORT
      LAYER M4 ;
        RECT  27.996 33.456 28.08 33.48 ;
    END
  END q[141]
  PIN q[142]
    DIRECTION OUTPUT ;
    USE SIGNAL ;
    PORT
      LAYER M4 ;
        RECT  27.996 33.552 28.08 33.576 ;
    END
  END q[142]
  PIN q[143]
    DIRECTION OUTPUT ;
    USE SIGNAL ;
    PORT
      LAYER M4 ;
        RECT  27.996 33.648 28.08 33.672 ;
    END
  END q[143]
  PIN q[144]
    DIRECTION OUTPUT ;
    USE SIGNAL ;
    PORT
      LAYER M4 ;
        RECT  27.996 33.744 28.08 33.768 ;
    END
  END q[144]
  PIN q[145]
    DIRECTION OUTPUT ;
    USE SIGNAL ;
    PORT
      LAYER M4 ;
        RECT  27.996 33.84 28.08 33.864 ;
    END
  END q[145]
  PIN q[146]
    DIRECTION OUTPUT ;
    USE SIGNAL ;
    PORT
      LAYER M4 ;
        RECT  27.996 33.936 28.08 33.96 ;
    END
  END q[146]
  PIN q[147]
    DIRECTION OUTPUT ;
    USE SIGNAL ;
    PORT
      LAYER M4 ;
        RECT  27.996 34.032 28.08 34.056 ;
    END
  END q[147]
  PIN q[148]
    DIRECTION OUTPUT ;
    USE SIGNAL ;
    PORT
      LAYER M4 ;
        RECT  27.996 34.128 28.08 34.152 ;
    END
  END q[148]
  PIN q[149]
    DIRECTION OUTPUT ;
    USE SIGNAL ;
    PORT
      LAYER M4 ;
        RECT  27.996 34.224 28.08 34.248 ;
    END
  END q[149]
  PIN q[14]
    DIRECTION OUTPUT ;
    USE SIGNAL ;
    PORT
      LAYER M4 ;
        RECT  27.996 21.264 28.08 21.288 ;
    END
  END q[14]
  PIN q[150]
    DIRECTION OUTPUT ;
    USE SIGNAL ;
    PORT
      LAYER M4 ;
        RECT  27.996 34.32 28.08 34.344 ;
    END
  END q[150]
  PIN q[151]
    DIRECTION OUTPUT ;
    USE SIGNAL ;
    PORT
      LAYER M4 ;
        RECT  27.996 34.416 28.08 34.44 ;
    END
  END q[151]
  PIN q[152]
    DIRECTION OUTPUT ;
    USE SIGNAL ;
    PORT
      LAYER M4 ;
        RECT  27.996 34.512 28.08 34.536 ;
    END
  END q[152]
  PIN q[153]
    DIRECTION OUTPUT ;
    USE SIGNAL ;
    PORT
      LAYER M4 ;
        RECT  27.996 34.608 28.08 34.632 ;
    END
  END q[153]
  PIN q[154]
    DIRECTION OUTPUT ;
    USE SIGNAL ;
    PORT
      LAYER M4 ;
        RECT  27.996 34.704 28.08 34.728 ;
    END
  END q[154]
  PIN q[155]
    DIRECTION OUTPUT ;
    USE SIGNAL ;
    PORT
      LAYER M4 ;
        RECT  27.996 34.8 28.08 34.824 ;
    END
  END q[155]
  PIN q[156]
    DIRECTION OUTPUT ;
    USE SIGNAL ;
    PORT
      LAYER M4 ;
        RECT  27.996 34.896 28.08 34.92 ;
    END
  END q[156]
  PIN q[157]
    DIRECTION OUTPUT ;
    USE SIGNAL ;
    PORT
      LAYER M4 ;
        RECT  27.996 34.992 28.08 35.016 ;
    END
  END q[157]
  PIN q[158]
    DIRECTION OUTPUT ;
    USE SIGNAL ;
    PORT
      LAYER M4 ;
        RECT  27.996 35.088 28.08 35.112 ;
    END
  END q[158]
  PIN q[159]
    DIRECTION OUTPUT ;
    USE SIGNAL ;
    PORT
      LAYER M4 ;
        RECT  27.996 35.184 28.08 35.208 ;
    END
  END q[159]
  PIN q[15]
    DIRECTION OUTPUT ;
    USE SIGNAL ;
    PORT
      LAYER M4 ;
        RECT  27.996 21.36 28.08 21.384 ;
    END
  END q[15]
  PIN q[160]
    DIRECTION OUTPUT ;
    USE SIGNAL ;
    PORT
      LAYER M4 ;
        RECT  27.996 35.28 28.08 35.304 ;
    END
  END q[160]
  PIN q[161]
    DIRECTION OUTPUT ;
    USE SIGNAL ;
    PORT
      LAYER M4 ;
        RECT  27.996 35.376 28.08 35.4 ;
    END
  END q[161]
  PIN q[162]
    DIRECTION OUTPUT ;
    USE SIGNAL ;
    PORT
      LAYER M4 ;
        RECT  27.996 35.472 28.08 35.496 ;
    END
  END q[162]
  PIN q[163]
    DIRECTION OUTPUT ;
    USE SIGNAL ;
    PORT
      LAYER M4 ;
        RECT  27.996 35.568 28.08 35.592 ;
    END
  END q[163]
  PIN q[164]
    DIRECTION OUTPUT ;
    USE SIGNAL ;
    PORT
      LAYER M4 ;
        RECT  27.996 35.664 28.08 35.688 ;
    END
  END q[164]
  PIN q[165]
    DIRECTION OUTPUT ;
    USE SIGNAL ;
    PORT
      LAYER M4 ;
        RECT  27.996 35.76 28.08 35.784 ;
    END
  END q[165]
  PIN q[166]
    DIRECTION OUTPUT ;
    USE SIGNAL ;
    PORT
      LAYER M4 ;
        RECT  27.996 35.856 28.08 35.88 ;
    END
  END q[166]
  PIN q[167]
    DIRECTION OUTPUT ;
    USE SIGNAL ;
    PORT
      LAYER M4 ;
        RECT  27.996 35.952 28.08 35.976 ;
    END
  END q[167]
  PIN q[168]
    DIRECTION OUTPUT ;
    USE SIGNAL ;
    PORT
      LAYER M4 ;
        RECT  27.996 36.048 28.08 36.072 ;
    END
  END q[168]
  PIN q[169]
    DIRECTION OUTPUT ;
    USE SIGNAL ;
    PORT
      LAYER M4 ;
        RECT  27.996 36.144 28.08 36.168 ;
    END
  END q[169]
  PIN q[16]
    DIRECTION OUTPUT ;
    USE SIGNAL ;
    PORT
      LAYER M4 ;
        RECT  27.996 21.456 28.08 21.48 ;
    END
  END q[16]
  PIN q[170]
    DIRECTION OUTPUT ;
    USE SIGNAL ;
    PORT
      LAYER M4 ;
        RECT  27.996 36.24 28.08 36.264 ;
    END
  END q[170]
  PIN q[171]
    DIRECTION OUTPUT ;
    USE SIGNAL ;
    PORT
      LAYER M4 ;
        RECT  27.996 36.336 28.08 36.36 ;
    END
  END q[171]
  PIN q[172]
    DIRECTION OUTPUT ;
    USE SIGNAL ;
    PORT
      LAYER M4 ;
        RECT  27.996 36.432 28.08 36.456 ;
    END
  END q[172]
  PIN q[173]
    DIRECTION OUTPUT ;
    USE SIGNAL ;
    PORT
      LAYER M4 ;
        RECT  27.996 36.528 28.08 36.552 ;
    END
  END q[173]
  PIN q[174]
    DIRECTION OUTPUT ;
    USE SIGNAL ;
    PORT
      LAYER M4 ;
        RECT  27.996 36.624 28.08 36.648 ;
    END
  END q[174]
  PIN q[175]
    DIRECTION OUTPUT ;
    USE SIGNAL ;
    PORT
      LAYER M4 ;
        RECT  27.996 36.72 28.08 36.744 ;
    END
  END q[175]
  PIN q[176]
    DIRECTION OUTPUT ;
    USE SIGNAL ;
    PORT
      LAYER M4 ;
        RECT  27.996 36.816 28.08 36.84 ;
    END
  END q[176]
  PIN q[177]
    DIRECTION OUTPUT ;
    USE SIGNAL ;
    PORT
      LAYER M4 ;
        RECT  27.996 36.912 28.08 36.936 ;
    END
  END q[177]
  PIN q[178]
    DIRECTION OUTPUT ;
    USE SIGNAL ;
    PORT
      LAYER M4 ;
        RECT  27.996 37.008 28.08 37.032 ;
    END
  END q[178]
  PIN q[179]
    DIRECTION OUTPUT ;
    USE SIGNAL ;
    PORT
      LAYER M4 ;
        RECT  27.996 37.104 28.08 37.128 ;
    END
  END q[179]
  PIN q[17]
    DIRECTION OUTPUT ;
    USE SIGNAL ;
    PORT
      LAYER M4 ;
        RECT  27.996 21.552 28.08 21.576 ;
    END
  END q[17]
  PIN q[180]
    DIRECTION OUTPUT ;
    USE SIGNAL ;
    PORT
      LAYER M4 ;
        RECT  27.996 37.2 28.08 37.224 ;
    END
  END q[180]
  PIN q[181]
    DIRECTION OUTPUT ;
    USE SIGNAL ;
    PORT
      LAYER M4 ;
        RECT  27.996 37.296 28.08 37.32 ;
    END
  END q[181]
  PIN q[182]
    DIRECTION OUTPUT ;
    USE SIGNAL ;
    PORT
      LAYER M4 ;
        RECT  27.996 37.392 28.08 37.416 ;
    END
  END q[182]
  PIN q[183]
    DIRECTION OUTPUT ;
    USE SIGNAL ;
    PORT
      LAYER M4 ;
        RECT  27.996 37.488 28.08 37.512 ;
    END
  END q[183]
  PIN q[184]
    DIRECTION OUTPUT ;
    USE SIGNAL ;
    PORT
      LAYER M4 ;
        RECT  27.996 37.584 28.08 37.608 ;
    END
  END q[184]
  PIN q[185]
    DIRECTION OUTPUT ;
    USE SIGNAL ;
    PORT
      LAYER M4 ;
        RECT  27.996 37.68 28.08 37.704 ;
    END
  END q[185]
  PIN q[186]
    DIRECTION OUTPUT ;
    USE SIGNAL ;
    PORT
      LAYER M4 ;
        RECT  27.996 37.776 28.08 37.8 ;
    END
  END q[186]
  PIN q[187]
    DIRECTION OUTPUT ;
    USE SIGNAL ;
    PORT
      LAYER M4 ;
        RECT  27.996 37.872 28.08 37.896 ;
    END
  END q[187]
  PIN q[188]
    DIRECTION OUTPUT ;
    USE SIGNAL ;
    PORT
      LAYER M4 ;
        RECT  27.996 37.968 28.08 37.992 ;
    END
  END q[188]
  PIN q[189]
    DIRECTION OUTPUT ;
    USE SIGNAL ;
    PORT
      LAYER M4 ;
        RECT  27.996 38.064 28.08 38.088 ;
    END
  END q[189]
  PIN q[18]
    DIRECTION OUTPUT ;
    USE SIGNAL ;
    PORT
      LAYER M4 ;
        RECT  27.996 21.648 28.08 21.672 ;
    END
  END q[18]
  PIN q[190]
    DIRECTION OUTPUT ;
    USE SIGNAL ;
    PORT
      LAYER M4 ;
        RECT  27.996 38.16 28.08 38.184 ;
    END
  END q[190]
  PIN q[191]
    DIRECTION OUTPUT ;
    USE SIGNAL ;
    PORT
      LAYER M4 ;
        RECT  27.996 38.256 28.08 38.28 ;
    END
  END q[191]
  PIN q[192]
    DIRECTION OUTPUT ;
    USE SIGNAL ;
    PORT
      LAYER M4 ;
        RECT  27.996 13.008 28.08 13.032 ;
    END
  END q[192]
  PIN q[193]
    DIRECTION OUTPUT ;
    USE SIGNAL ;
    PORT
      LAYER M4 ;
        RECT  27.996 13.104 28.08 13.128 ;
    END
  END q[193]
  PIN q[194]
    DIRECTION OUTPUT ;
    USE SIGNAL ;
    PORT
      LAYER M4 ;
        RECT  27.996 13.2 28.08 13.224 ;
    END
  END q[194]
  PIN q[195]
    DIRECTION OUTPUT ;
    USE SIGNAL ;
    PORT
      LAYER M4 ;
        RECT  27.996 13.296 28.08 13.32 ;
    END
  END q[195]
  PIN q[196]
    DIRECTION OUTPUT ;
    USE SIGNAL ;
    PORT
      LAYER M4 ;
        RECT  27.996 13.392 28.08 13.416 ;
    END
  END q[196]
  PIN q[197]
    DIRECTION OUTPUT ;
    USE SIGNAL ;
    PORT
      LAYER M4 ;
        RECT  27.996 13.488 28.08 13.512 ;
    END
  END q[197]
  PIN q[198]
    DIRECTION OUTPUT ;
    USE SIGNAL ;
    PORT
      LAYER M4 ;
        RECT  27.996 13.584 28.08 13.608 ;
    END
  END q[198]
  PIN q[199]
    DIRECTION OUTPUT ;
    USE SIGNAL ;
    PORT
      LAYER M4 ;
        RECT  27.996 13.68 28.08 13.704 ;
    END
  END q[199]
  PIN q[19]
    DIRECTION OUTPUT ;
    USE SIGNAL ;
    PORT
      LAYER M4 ;
        RECT  27.996 21.744 28.08 21.768 ;
    END
  END q[19]
  PIN q[1]
    DIRECTION OUTPUT ;
    USE SIGNAL ;
    PORT
      LAYER M4 ;
        RECT  27.996 20.016 28.08 20.04 ;
    END
  END q[1]
  PIN q[200]
    DIRECTION OUTPUT ;
    USE SIGNAL ;
    PORT
      LAYER M4 ;
        RECT  27.996 13.776 28.08 13.8 ;
    END
  END q[200]
  PIN q[201]
    DIRECTION OUTPUT ;
    USE SIGNAL ;
    PORT
      LAYER M4 ;
        RECT  27.996 13.872 28.08 13.896 ;
    END
  END q[201]
  PIN q[202]
    DIRECTION OUTPUT ;
    USE SIGNAL ;
    PORT
      LAYER M4 ;
        RECT  27.996 13.968 28.08 13.992 ;
    END
  END q[202]
  PIN q[203]
    DIRECTION OUTPUT ;
    USE SIGNAL ;
    PORT
      LAYER M4 ;
        RECT  27.996 14.064 28.08 14.088 ;
    END
  END q[203]
  PIN q[204]
    DIRECTION OUTPUT ;
    USE SIGNAL ;
    PORT
      LAYER M4 ;
        RECT  27.996 14.16 28.08 14.184 ;
    END
  END q[204]
  PIN q[205]
    DIRECTION OUTPUT ;
    USE SIGNAL ;
    PORT
      LAYER M4 ;
        RECT  27.996 14.256 28.08 14.28 ;
    END
  END q[205]
  PIN q[206]
    DIRECTION OUTPUT ;
    USE SIGNAL ;
    PORT
      LAYER M4 ;
        RECT  27.996 14.352 28.08 14.376 ;
    END
  END q[206]
  PIN q[207]
    DIRECTION OUTPUT ;
    USE SIGNAL ;
    PORT
      LAYER M4 ;
        RECT  27.996 14.448 28.08 14.472 ;
    END
  END q[207]
  PIN q[208]
    DIRECTION OUTPUT ;
    USE SIGNAL ;
    PORT
      LAYER M4 ;
        RECT  27.996 14.544 28.08 14.568 ;
    END
  END q[208]
  PIN q[209]
    DIRECTION OUTPUT ;
    USE SIGNAL ;
    PORT
      LAYER M4 ;
        RECT  27.996 14.64 28.08 14.664 ;
    END
  END q[209]
  PIN q[20]
    DIRECTION OUTPUT ;
    USE SIGNAL ;
    PORT
      LAYER M4 ;
        RECT  27.996 21.84 28.08 21.864 ;
    END
  END q[20]
  PIN q[210]
    DIRECTION OUTPUT ;
    USE SIGNAL ;
    PORT
      LAYER M4 ;
        RECT  27.996 14.736 28.08 14.76 ;
    END
  END q[210]
  PIN q[211]
    DIRECTION OUTPUT ;
    USE SIGNAL ;
    PORT
      LAYER M4 ;
        RECT  27.996 14.832 28.08 14.856 ;
    END
  END q[211]
  PIN q[212]
    DIRECTION OUTPUT ;
    USE SIGNAL ;
    PORT
      LAYER M4 ;
        RECT  27.996 14.928 28.08 14.952 ;
    END
  END q[212]
  PIN q[213]
    DIRECTION OUTPUT ;
    USE SIGNAL ;
    PORT
      LAYER M4 ;
        RECT  27.996 15.024 28.08 15.048 ;
    END
  END q[213]
  PIN q[214]
    DIRECTION OUTPUT ;
    USE SIGNAL ;
    PORT
      LAYER M4 ;
        RECT  27.996 15.12 28.08 15.144 ;
    END
  END q[214]
  PIN q[215]
    DIRECTION OUTPUT ;
    USE SIGNAL ;
    PORT
      LAYER M4 ;
        RECT  27.996 15.216 28.08 15.24 ;
    END
  END q[215]
  PIN q[216]
    DIRECTION OUTPUT ;
    USE SIGNAL ;
    PORT
      LAYER M4 ;
        RECT  27.996 15.312 28.08 15.336 ;
    END
  END q[216]
  PIN q[217]
    DIRECTION OUTPUT ;
    USE SIGNAL ;
    PORT
      LAYER M4 ;
        RECT  27.996 15.408 28.08 15.432 ;
    END
  END q[217]
  PIN q[218]
    DIRECTION OUTPUT ;
    USE SIGNAL ;
    PORT
      LAYER M4 ;
        RECT  27.996 15.504 28.08 15.528 ;
    END
  END q[218]
  PIN q[219]
    DIRECTION OUTPUT ;
    USE SIGNAL ;
    PORT
      LAYER M4 ;
        RECT  27.996 15.6 28.08 15.624 ;
    END
  END q[219]
  PIN q[21]
    DIRECTION OUTPUT ;
    USE SIGNAL ;
    PORT
      LAYER M4 ;
        RECT  27.996 21.936 28.08 21.96 ;
    END
  END q[21]
  PIN q[220]
    DIRECTION OUTPUT ;
    USE SIGNAL ;
    PORT
      LAYER M4 ;
        RECT  27.996 15.696 28.08 15.72 ;
    END
  END q[220]
  PIN q[221]
    DIRECTION OUTPUT ;
    USE SIGNAL ;
    PORT
      LAYER M4 ;
        RECT  27.996 15.792 28.08 15.816 ;
    END
  END q[221]
  PIN q[222]
    DIRECTION OUTPUT ;
    USE SIGNAL ;
    PORT
      LAYER M4 ;
        RECT  27.996 15.888 28.08 15.912 ;
    END
  END q[222]
  PIN q[223]
    DIRECTION OUTPUT ;
    USE SIGNAL ;
    PORT
      LAYER M4 ;
        RECT  27.996 15.984 28.08 16.008 ;
    END
  END q[223]
  PIN q[224]
    DIRECTION OUTPUT ;
    USE SIGNAL ;
    PORT
      LAYER M4 ;
        RECT  27.996 9.936 28.08 9.96 ;
    END
  END q[224]
  PIN q[225]
    DIRECTION OUTPUT ;
    USE SIGNAL ;
    PORT
      LAYER M4 ;
        RECT  27.996 10.032 28.08 10.056 ;
    END
  END q[225]
  PIN q[226]
    DIRECTION OUTPUT ;
    USE SIGNAL ;
    PORT
      LAYER M4 ;
        RECT  27.996 10.128 28.08 10.152 ;
    END
  END q[226]
  PIN q[227]
    DIRECTION OUTPUT ;
    USE SIGNAL ;
    PORT
      LAYER M4 ;
        RECT  27.996 10.224 28.08 10.248 ;
    END
  END q[227]
  PIN q[228]
    DIRECTION OUTPUT ;
    USE SIGNAL ;
    PORT
      LAYER M4 ;
        RECT  27.996 10.32 28.08 10.344 ;
    END
  END q[228]
  PIN q[229]
    DIRECTION OUTPUT ;
    USE SIGNAL ;
    PORT
      LAYER M4 ;
        RECT  27.996 10.416 28.08 10.44 ;
    END
  END q[229]
  PIN q[22]
    DIRECTION OUTPUT ;
    USE SIGNAL ;
    PORT
      LAYER M4 ;
        RECT  27.996 22.032 28.08 22.056 ;
    END
  END q[22]
  PIN q[230]
    DIRECTION OUTPUT ;
    USE SIGNAL ;
    PORT
      LAYER M4 ;
        RECT  27.996 10.512 28.08 10.536 ;
    END
  END q[230]
  PIN q[231]
    DIRECTION OUTPUT ;
    USE SIGNAL ;
    PORT
      LAYER M4 ;
        RECT  27.996 10.608 28.08 10.632 ;
    END
  END q[231]
  PIN q[232]
    DIRECTION OUTPUT ;
    USE SIGNAL ;
    PORT
      LAYER M4 ;
        RECT  27.996 10.704 28.08 10.728 ;
    END
  END q[232]
  PIN q[233]
    DIRECTION OUTPUT ;
    USE SIGNAL ;
    PORT
      LAYER M4 ;
        RECT  27.996 10.8 28.08 10.824 ;
    END
  END q[233]
  PIN q[234]
    DIRECTION OUTPUT ;
    USE SIGNAL ;
    PORT
      LAYER M4 ;
        RECT  27.996 10.896 28.08 10.92 ;
    END
  END q[234]
  PIN q[235]
    DIRECTION OUTPUT ;
    USE SIGNAL ;
    PORT
      LAYER M4 ;
        RECT  27.996 10.992 28.08 11.016 ;
    END
  END q[235]
  PIN q[236]
    DIRECTION OUTPUT ;
    USE SIGNAL ;
    PORT
      LAYER M4 ;
        RECT  27.996 11.088 28.08 11.112 ;
    END
  END q[236]
  PIN q[237]
    DIRECTION OUTPUT ;
    USE SIGNAL ;
    PORT
      LAYER M4 ;
        RECT  27.996 11.184 28.08 11.208 ;
    END
  END q[237]
  PIN q[238]
    DIRECTION OUTPUT ;
    USE SIGNAL ;
    PORT
      LAYER M4 ;
        RECT  27.996 11.28 28.08 11.304 ;
    END
  END q[238]
  PIN q[239]
    DIRECTION OUTPUT ;
    USE SIGNAL ;
    PORT
      LAYER M4 ;
        RECT  27.996 11.376 28.08 11.4 ;
    END
  END q[239]
  PIN q[23]
    DIRECTION OUTPUT ;
    USE SIGNAL ;
    PORT
      LAYER M4 ;
        RECT  27.996 22.128 28.08 22.152 ;
    END
  END q[23]
  PIN q[240]
    DIRECTION OUTPUT ;
    USE SIGNAL ;
    PORT
      LAYER M4 ;
        RECT  27.996 11.472 28.08 11.496 ;
    END
  END q[240]
  PIN q[241]
    DIRECTION OUTPUT ;
    USE SIGNAL ;
    PORT
      LAYER M4 ;
        RECT  27.996 11.568 28.08 11.592 ;
    END
  END q[241]
  PIN q[242]
    DIRECTION OUTPUT ;
    USE SIGNAL ;
    PORT
      LAYER M4 ;
        RECT  27.996 11.664 28.08 11.688 ;
    END
  END q[242]
  PIN q[243]
    DIRECTION OUTPUT ;
    USE SIGNAL ;
    PORT
      LAYER M4 ;
        RECT  27.996 11.76 28.08 11.784 ;
    END
  END q[243]
  PIN q[244]
    DIRECTION OUTPUT ;
    USE SIGNAL ;
    PORT
      LAYER M4 ;
        RECT  27.996 11.856 28.08 11.88 ;
    END
  END q[244]
  PIN q[245]
    DIRECTION OUTPUT ;
    USE SIGNAL ;
    PORT
      LAYER M4 ;
        RECT  27.996 11.952 28.08 11.976 ;
    END
  END q[245]
  PIN q[246]
    DIRECTION OUTPUT ;
    USE SIGNAL ;
    PORT
      LAYER M4 ;
        RECT  27.996 12.048 28.08 12.072 ;
    END
  END q[246]
  PIN q[247]
    DIRECTION OUTPUT ;
    USE SIGNAL ;
    PORT
      LAYER M4 ;
        RECT  27.996 12.144 28.08 12.168 ;
    END
  END q[247]
  PIN q[248]
    DIRECTION OUTPUT ;
    USE SIGNAL ;
    PORT
      LAYER M4 ;
        RECT  27.996 12.24 28.08 12.264 ;
    END
  END q[248]
  PIN q[249]
    DIRECTION OUTPUT ;
    USE SIGNAL ;
    PORT
      LAYER M4 ;
        RECT  27.996 12.336 28.08 12.36 ;
    END
  END q[249]
  PIN q[24]
    DIRECTION OUTPUT ;
    USE SIGNAL ;
    PORT
      LAYER M4 ;
        RECT  27.996 22.224 28.08 22.248 ;
    END
  END q[24]
  PIN q[250]
    DIRECTION OUTPUT ;
    USE SIGNAL ;
    PORT
      LAYER M4 ;
        RECT  27.996 12.432 28.08 12.456 ;
    END
  END q[250]
  PIN q[251]
    DIRECTION OUTPUT ;
    USE SIGNAL ;
    PORT
      LAYER M4 ;
        RECT  27.996 12.528 28.08 12.552 ;
    END
  END q[251]
  PIN q[252]
    DIRECTION OUTPUT ;
    USE SIGNAL ;
    PORT
      LAYER M4 ;
        RECT  27.996 12.624 28.08 12.648 ;
    END
  END q[252]
  PIN q[253]
    DIRECTION OUTPUT ;
    USE SIGNAL ;
    PORT
      LAYER M4 ;
        RECT  27.996 12.72 28.08 12.744 ;
    END
  END q[253]
  PIN q[254]
    DIRECTION OUTPUT ;
    USE SIGNAL ;
    PORT
      LAYER M4 ;
        RECT  27.996 12.816 28.08 12.84 ;
    END
  END q[254]
  PIN q[255]
    DIRECTION OUTPUT ;
    USE SIGNAL ;
    PORT
      LAYER M4 ;
        RECT  27.996 12.912 28.08 12.936 ;
    END
  END q[255]
  PIN q[256]
    DIRECTION OUTPUT ;
    USE SIGNAL ;
    PORT
      LAYER M4 ;
        RECT  27.996 51.408 28.08 51.432 ;
    END
  END q[256]
  PIN q[257]
    DIRECTION OUTPUT ;
    USE SIGNAL ;
    PORT
      LAYER M4 ;
        RECT  27.996 51.504 28.08 51.528 ;
    END
  END q[257]
  PIN q[258]
    DIRECTION OUTPUT ;
    USE SIGNAL ;
    PORT
      LAYER M4 ;
        RECT  27.996 51.6 28.08 51.624 ;
    END
  END q[258]
  PIN q[259]
    DIRECTION OUTPUT ;
    USE SIGNAL ;
    PORT
      LAYER M4 ;
        RECT  27.996 51.696 28.08 51.72 ;
    END
  END q[259]
  PIN q[25]
    DIRECTION OUTPUT ;
    USE SIGNAL ;
    PORT
      LAYER M4 ;
        RECT  27.996 22.32 28.08 22.344 ;
    END
  END q[25]
  PIN q[260]
    DIRECTION OUTPUT ;
    USE SIGNAL ;
    PORT
      LAYER M4 ;
        RECT  27.996 51.792 28.08 51.816 ;
    END
  END q[260]
  PIN q[261]
    DIRECTION OUTPUT ;
    USE SIGNAL ;
    PORT
      LAYER M4 ;
        RECT  27.996 51.888 28.08 51.912 ;
    END
  END q[261]
  PIN q[262]
    DIRECTION OUTPUT ;
    USE SIGNAL ;
    PORT
      LAYER M4 ;
        RECT  27.996 51.984 28.08 52.008 ;
    END
  END q[262]
  PIN q[263]
    DIRECTION OUTPUT ;
    USE SIGNAL ;
    PORT
      LAYER M4 ;
        RECT  27.996 52.08 28.08 52.104 ;
    END
  END q[263]
  PIN q[264]
    DIRECTION OUTPUT ;
    USE SIGNAL ;
    PORT
      LAYER M4 ;
        RECT  27.996 52.176 28.08 52.2 ;
    END
  END q[264]
  PIN q[265]
    DIRECTION OUTPUT ;
    USE SIGNAL ;
    PORT
      LAYER M4 ;
        RECT  27.996 52.272 28.08 52.296 ;
    END
  END q[265]
  PIN q[266]
    DIRECTION OUTPUT ;
    USE SIGNAL ;
    PORT
      LAYER M4 ;
        RECT  27.996 52.368 28.08 52.392 ;
    END
  END q[266]
  PIN q[267]
    DIRECTION OUTPUT ;
    USE SIGNAL ;
    PORT
      LAYER M4 ;
        RECT  27.996 52.464 28.08 52.488 ;
    END
  END q[267]
  PIN q[268]
    DIRECTION OUTPUT ;
    USE SIGNAL ;
    PORT
      LAYER M4 ;
        RECT  27.996 52.56 28.08 52.584 ;
    END
  END q[268]
  PIN q[269]
    DIRECTION OUTPUT ;
    USE SIGNAL ;
    PORT
      LAYER M4 ;
        RECT  27.996 52.656 28.08 52.68 ;
    END
  END q[269]
  PIN q[26]
    DIRECTION OUTPUT ;
    USE SIGNAL ;
    PORT
      LAYER M4 ;
        RECT  27.996 22.416 28.08 22.44 ;
    END
  END q[26]
  PIN q[270]
    DIRECTION OUTPUT ;
    USE SIGNAL ;
    PORT
      LAYER M4 ;
        RECT  27.996 52.752 28.08 52.776 ;
    END
  END q[270]
  PIN q[271]
    DIRECTION OUTPUT ;
    USE SIGNAL ;
    PORT
      LAYER M4 ;
        RECT  27.996 52.848 28.08 52.872 ;
    END
  END q[271]
  PIN q[272]
    DIRECTION OUTPUT ;
    USE SIGNAL ;
    PORT
      LAYER M4 ;
        RECT  27.996 52.944 28.08 52.968 ;
    END
  END q[272]
  PIN q[273]
    DIRECTION OUTPUT ;
    USE SIGNAL ;
    PORT
      LAYER M4 ;
        RECT  27.996 53.04 28.08 53.064 ;
    END
  END q[273]
  PIN q[274]
    DIRECTION OUTPUT ;
    USE SIGNAL ;
    PORT
      LAYER M4 ;
        RECT  27.996 53.136 28.08 53.16 ;
    END
  END q[274]
  PIN q[275]
    DIRECTION OUTPUT ;
    USE SIGNAL ;
    PORT
      LAYER M4 ;
        RECT  27.996 53.232 28.08 53.256 ;
    END
  END q[275]
  PIN q[276]
    DIRECTION OUTPUT ;
    USE SIGNAL ;
    PORT
      LAYER M4 ;
        RECT  27.996 53.328 28.08 53.352 ;
    END
  END q[276]
  PIN q[277]
    DIRECTION OUTPUT ;
    USE SIGNAL ;
    PORT
      LAYER M4 ;
        RECT  27.996 53.424 28.08 53.448 ;
    END
  END q[277]
  PIN q[278]
    DIRECTION OUTPUT ;
    USE SIGNAL ;
    PORT
      LAYER M4 ;
        RECT  27.996 53.52 28.08 53.544 ;
    END
  END q[278]
  PIN q[279]
    DIRECTION OUTPUT ;
    USE SIGNAL ;
    PORT
      LAYER M4 ;
        RECT  27.996 53.616 28.08 53.64 ;
    END
  END q[279]
  PIN q[27]
    DIRECTION OUTPUT ;
    USE SIGNAL ;
    PORT
      LAYER M4 ;
        RECT  27.996 22.512 28.08 22.536 ;
    END
  END q[27]
  PIN q[280]
    DIRECTION OUTPUT ;
    USE SIGNAL ;
    PORT
      LAYER M4 ;
        RECT  27.996 53.712 28.08 53.736 ;
    END
  END q[280]
  PIN q[281]
    DIRECTION OUTPUT ;
    USE SIGNAL ;
    PORT
      LAYER M4 ;
        RECT  27.996 53.808 28.08 53.832 ;
    END
  END q[281]
  PIN q[282]
    DIRECTION OUTPUT ;
    USE SIGNAL ;
    PORT
      LAYER M4 ;
        RECT  27.996 53.904 28.08 53.928 ;
    END
  END q[282]
  PIN q[283]
    DIRECTION OUTPUT ;
    USE SIGNAL ;
    PORT
      LAYER M4 ;
        RECT  27.996 54 28.08 54.024 ;
    END
  END q[283]
  PIN q[284]
    DIRECTION OUTPUT ;
    USE SIGNAL ;
    PORT
      LAYER M4 ;
        RECT  27.996 54.096 28.08 54.12 ;
    END
  END q[284]
  PIN q[285]
    DIRECTION OUTPUT ;
    USE SIGNAL ;
    PORT
      LAYER M4 ;
        RECT  27.996 54.192 28.08 54.216 ;
    END
  END q[285]
  PIN q[286]
    DIRECTION OUTPUT ;
    USE SIGNAL ;
    PORT
      LAYER M4 ;
        RECT  27.996 54.288 28.08 54.312 ;
    END
  END q[286]
  PIN q[287]
    DIRECTION OUTPUT ;
    USE SIGNAL ;
    PORT
      LAYER M4 ;
        RECT  27.996 54.384 28.08 54.408 ;
    END
  END q[287]
  PIN q[288]
    DIRECTION OUTPUT ;
    USE SIGNAL ;
    PORT
      LAYER M4 ;
        RECT  27.996 54.48 28.08 54.504 ;
    END
  END q[288]
  PIN q[289]
    DIRECTION OUTPUT ;
    USE SIGNAL ;
    PORT
      LAYER M4 ;
        RECT  27.996 54.576 28.08 54.6 ;
    END
  END q[289]
  PIN q[28]
    DIRECTION OUTPUT ;
    USE SIGNAL ;
    PORT
      LAYER M4 ;
        RECT  27.996 22.608 28.08 22.632 ;
    END
  END q[28]
  PIN q[290]
    DIRECTION OUTPUT ;
    USE SIGNAL ;
    PORT
      LAYER M4 ;
        RECT  27.996 54.672 28.08 54.696 ;
    END
  END q[290]
  PIN q[291]
    DIRECTION OUTPUT ;
    USE SIGNAL ;
    PORT
      LAYER M4 ;
        RECT  27.996 54.768 28.08 54.792 ;
    END
  END q[291]
  PIN q[292]
    DIRECTION OUTPUT ;
    USE SIGNAL ;
    PORT
      LAYER M4 ;
        RECT  27.996 54.864 28.08 54.888 ;
    END
  END q[292]
  PIN q[293]
    DIRECTION OUTPUT ;
    USE SIGNAL ;
    PORT
      LAYER M4 ;
        RECT  27.996 54.96 28.08 54.984 ;
    END
  END q[293]
  PIN q[294]
    DIRECTION OUTPUT ;
    USE SIGNAL ;
    PORT
      LAYER M4 ;
        RECT  27.996 55.056 28.08 55.08 ;
    END
  END q[294]
  PIN q[295]
    DIRECTION OUTPUT ;
    USE SIGNAL ;
    PORT
      LAYER M4 ;
        RECT  27.996 55.152 28.08 55.176 ;
    END
  END q[295]
  PIN q[296]
    DIRECTION OUTPUT ;
    USE SIGNAL ;
    PORT
      LAYER M4 ;
        RECT  27.996 55.248 28.08 55.272 ;
    END
  END q[296]
  PIN q[297]
    DIRECTION OUTPUT ;
    USE SIGNAL ;
    PORT
      LAYER M4 ;
        RECT  27.996 55.344 28.08 55.368 ;
    END
  END q[297]
  PIN q[298]
    DIRECTION OUTPUT ;
    USE SIGNAL ;
    PORT
      LAYER M4 ;
        RECT  27.996 55.44 28.08 55.464 ;
    END
  END q[298]
  PIN q[299]
    DIRECTION OUTPUT ;
    USE SIGNAL ;
    PORT
      LAYER M4 ;
        RECT  27.996 55.536 28.08 55.56 ;
    END
  END q[299]
  PIN q[29]
    DIRECTION OUTPUT ;
    USE SIGNAL ;
    PORT
      LAYER M4 ;
        RECT  27.996 22.704 28.08 22.728 ;
    END
  END q[29]
  PIN q[2]
    DIRECTION OUTPUT ;
    USE SIGNAL ;
    PORT
      LAYER M4 ;
        RECT  27.996 20.112 28.08 20.136 ;
    END
  END q[2]
  PIN q[300]
    DIRECTION OUTPUT ;
    USE SIGNAL ;
    PORT
      LAYER M4 ;
        RECT  27.996 55.632 28.08 55.656 ;
    END
  END q[300]
  PIN q[301]
    DIRECTION OUTPUT ;
    USE SIGNAL ;
    PORT
      LAYER M4 ;
        RECT  27.996 55.728 28.08 55.752 ;
    END
  END q[301]
  PIN q[302]
    DIRECTION OUTPUT ;
    USE SIGNAL ;
    PORT
      LAYER M4 ;
        RECT  27.996 55.824 28.08 55.848 ;
    END
  END q[302]
  PIN q[303]
    DIRECTION OUTPUT ;
    USE SIGNAL ;
    PORT
      LAYER M4 ;
        RECT  27.996 55.92 28.08 55.944 ;
    END
  END q[303]
  PIN q[304]
    DIRECTION OUTPUT ;
    USE SIGNAL ;
    PORT
      LAYER M4 ;
        RECT  27.996 56.016 28.08 56.04 ;
    END
  END q[304]
  PIN q[305]
    DIRECTION OUTPUT ;
    USE SIGNAL ;
    PORT
      LAYER M4 ;
        RECT  27.996 56.112 28.08 56.136 ;
    END
  END q[305]
  PIN q[306]
    DIRECTION OUTPUT ;
    USE SIGNAL ;
    PORT
      LAYER M4 ;
        RECT  27.996 56.208 28.08 56.232 ;
    END
  END q[306]
  PIN q[307]
    DIRECTION OUTPUT ;
    USE SIGNAL ;
    PORT
      LAYER M4 ;
        RECT  27.996 56.304 28.08 56.328 ;
    END
  END q[307]
  PIN q[308]
    DIRECTION OUTPUT ;
    USE SIGNAL ;
    PORT
      LAYER M4 ;
        RECT  27.996 56.4 28.08 56.424 ;
    END
  END q[308]
  PIN q[309]
    DIRECTION OUTPUT ;
    USE SIGNAL ;
    PORT
      LAYER M4 ;
        RECT  27.996 56.496 28.08 56.52 ;
    END
  END q[309]
  PIN q[30]
    DIRECTION OUTPUT ;
    USE SIGNAL ;
    PORT
      LAYER M4 ;
        RECT  27.996 22.8 28.08 22.824 ;
    END
  END q[30]
  PIN q[310]
    DIRECTION OUTPUT ;
    USE SIGNAL ;
    PORT
      LAYER M4 ;
        RECT  27.996 56.592 28.08 56.616 ;
    END
  END q[310]
  PIN q[311]
    DIRECTION OUTPUT ;
    USE SIGNAL ;
    PORT
      LAYER M4 ;
        RECT  27.996 56.688 28.08 56.712 ;
    END
  END q[311]
  PIN q[312]
    DIRECTION OUTPUT ;
    USE SIGNAL ;
    PORT
      LAYER M4 ;
        RECT  27.996 56.784 28.08 56.808 ;
    END
  END q[312]
  PIN q[313]
    DIRECTION OUTPUT ;
    USE SIGNAL ;
    PORT
      LAYER M4 ;
        RECT  27.996 56.88 28.08 56.904 ;
    END
  END q[313]
  PIN q[314]
    DIRECTION OUTPUT ;
    USE SIGNAL ;
    PORT
      LAYER M4 ;
        RECT  27.996 56.976 28.08 57 ;
    END
  END q[314]
  PIN q[315]
    DIRECTION OUTPUT ;
    USE SIGNAL ;
    PORT
      LAYER M4 ;
        RECT  27.996 57.072 28.08 57.096 ;
    END
  END q[315]
  PIN q[316]
    DIRECTION OUTPUT ;
    USE SIGNAL ;
    PORT
      LAYER M4 ;
        RECT  27.996 57.168 28.08 57.192 ;
    END
  END q[316]
  PIN q[317]
    DIRECTION OUTPUT ;
    USE SIGNAL ;
    PORT
      LAYER M4 ;
        RECT  27.996 57.264 28.08 57.288 ;
    END
  END q[317]
  PIN q[318]
    DIRECTION OUTPUT ;
    USE SIGNAL ;
    PORT
      LAYER M4 ;
        RECT  27.996 57.36 28.08 57.384 ;
    END
  END q[318]
  PIN q[319]
    DIRECTION OUTPUT ;
    USE SIGNAL ;
    PORT
      LAYER M4 ;
        RECT  27.996 57.456 28.08 57.48 ;
    END
  END q[319]
  PIN q[31]
    DIRECTION OUTPUT ;
    USE SIGNAL ;
    PORT
      LAYER M4 ;
        RECT  27.996 22.896 28.08 22.92 ;
    END
  END q[31]
  PIN q[320]
    DIRECTION OUTPUT ;
    USE SIGNAL ;
    PORT
      LAYER M4 ;
        RECT  27.996 42.192 28.08 42.216 ;
    END
  END q[320]
  PIN q[321]
    DIRECTION OUTPUT ;
    USE SIGNAL ;
    PORT
      LAYER M4 ;
        RECT  27.996 42.288 28.08 42.312 ;
    END
  END q[321]
  PIN q[322]
    DIRECTION OUTPUT ;
    USE SIGNAL ;
    PORT
      LAYER M4 ;
        RECT  27.996 42.384 28.08 42.408 ;
    END
  END q[322]
  PIN q[323]
    DIRECTION OUTPUT ;
    USE SIGNAL ;
    PORT
      LAYER M4 ;
        RECT  27.996 42.48 28.08 42.504 ;
    END
  END q[323]
  PIN q[324]
    DIRECTION OUTPUT ;
    USE SIGNAL ;
    PORT
      LAYER M4 ;
        RECT  27.996 42.576 28.08 42.6 ;
    END
  END q[324]
  PIN q[325]
    DIRECTION OUTPUT ;
    USE SIGNAL ;
    PORT
      LAYER M4 ;
        RECT  27.996 42.672 28.08 42.696 ;
    END
  END q[325]
  PIN q[326]
    DIRECTION OUTPUT ;
    USE SIGNAL ;
    PORT
      LAYER M4 ;
        RECT  27.996 42.768 28.08 42.792 ;
    END
  END q[326]
  PIN q[327]
    DIRECTION OUTPUT ;
    USE SIGNAL ;
    PORT
      LAYER M4 ;
        RECT  27.996 42.864 28.08 42.888 ;
    END
  END q[327]
  PIN q[328]
    DIRECTION OUTPUT ;
    USE SIGNAL ;
    PORT
      LAYER M4 ;
        RECT  27.996 42.96 28.08 42.984 ;
    END
  END q[328]
  PIN q[329]
    DIRECTION OUTPUT ;
    USE SIGNAL ;
    PORT
      LAYER M4 ;
        RECT  27.996 43.056 28.08 43.08 ;
    END
  END q[329]
  PIN q[32]
    DIRECTION OUTPUT ;
    USE SIGNAL ;
    PORT
      LAYER M4 ;
        RECT  27.996 29.136 28.08 29.16 ;
    END
  END q[32]
  PIN q[330]
    DIRECTION OUTPUT ;
    USE SIGNAL ;
    PORT
      LAYER M4 ;
        RECT  27.996 43.152 28.08 43.176 ;
    END
  END q[330]
  PIN q[331]
    DIRECTION OUTPUT ;
    USE SIGNAL ;
    PORT
      LAYER M4 ;
        RECT  27.996 43.248 28.08 43.272 ;
    END
  END q[331]
  PIN q[332]
    DIRECTION OUTPUT ;
    USE SIGNAL ;
    PORT
      LAYER M4 ;
        RECT  27.996 43.344 28.08 43.368 ;
    END
  END q[332]
  PIN q[333]
    DIRECTION OUTPUT ;
    USE SIGNAL ;
    PORT
      LAYER M4 ;
        RECT  27.996 43.44 28.08 43.464 ;
    END
  END q[333]
  PIN q[334]
    DIRECTION OUTPUT ;
    USE SIGNAL ;
    PORT
      LAYER M4 ;
        RECT  27.996 43.536 28.08 43.56 ;
    END
  END q[334]
  PIN q[335]
    DIRECTION OUTPUT ;
    USE SIGNAL ;
    PORT
      LAYER M4 ;
        RECT  27.996 43.632 28.08 43.656 ;
    END
  END q[335]
  PIN q[336]
    DIRECTION OUTPUT ;
    USE SIGNAL ;
    PORT
      LAYER M4 ;
        RECT  27.996 43.728 28.08 43.752 ;
    END
  END q[336]
  PIN q[337]
    DIRECTION OUTPUT ;
    USE SIGNAL ;
    PORT
      LAYER M4 ;
        RECT  27.996 43.824 28.08 43.848 ;
    END
  END q[337]
  PIN q[338]
    DIRECTION OUTPUT ;
    USE SIGNAL ;
    PORT
      LAYER M4 ;
        RECT  27.996 43.92 28.08 43.944 ;
    END
  END q[338]
  PIN q[339]
    DIRECTION OUTPUT ;
    USE SIGNAL ;
    PORT
      LAYER M4 ;
        RECT  27.996 44.016 28.08 44.04 ;
    END
  END q[339]
  PIN q[33]
    DIRECTION OUTPUT ;
    USE SIGNAL ;
    PORT
      LAYER M4 ;
        RECT  27.996 29.232 28.08 29.256 ;
    END
  END q[33]
  PIN q[340]
    DIRECTION OUTPUT ;
    USE SIGNAL ;
    PORT
      LAYER M4 ;
        RECT  27.996 44.112 28.08 44.136 ;
    END
  END q[340]
  PIN q[341]
    DIRECTION OUTPUT ;
    USE SIGNAL ;
    PORT
      LAYER M4 ;
        RECT  27.996 44.208 28.08 44.232 ;
    END
  END q[341]
  PIN q[342]
    DIRECTION OUTPUT ;
    USE SIGNAL ;
    PORT
      LAYER M4 ;
        RECT  27.996 44.304 28.08 44.328 ;
    END
  END q[342]
  PIN q[343]
    DIRECTION OUTPUT ;
    USE SIGNAL ;
    PORT
      LAYER M4 ;
        RECT  27.996 44.4 28.08 44.424 ;
    END
  END q[343]
  PIN q[344]
    DIRECTION OUTPUT ;
    USE SIGNAL ;
    PORT
      LAYER M4 ;
        RECT  27.996 44.496 28.08 44.52 ;
    END
  END q[344]
  PIN q[345]
    DIRECTION OUTPUT ;
    USE SIGNAL ;
    PORT
      LAYER M4 ;
        RECT  27.996 44.592 28.08 44.616 ;
    END
  END q[345]
  PIN q[346]
    DIRECTION OUTPUT ;
    USE SIGNAL ;
    PORT
      LAYER M4 ;
        RECT  27.996 44.688 28.08 44.712 ;
    END
  END q[346]
  PIN q[347]
    DIRECTION OUTPUT ;
    USE SIGNAL ;
    PORT
      LAYER M4 ;
        RECT  27.996 44.784 28.08 44.808 ;
    END
  END q[347]
  PIN q[348]
    DIRECTION OUTPUT ;
    USE SIGNAL ;
    PORT
      LAYER M4 ;
        RECT  27.996 44.88 28.08 44.904 ;
    END
  END q[348]
  PIN q[349]
    DIRECTION OUTPUT ;
    USE SIGNAL ;
    PORT
      LAYER M4 ;
        RECT  27.996 44.976 28.08 45 ;
    END
  END q[349]
  PIN q[34]
    DIRECTION OUTPUT ;
    USE SIGNAL ;
    PORT
      LAYER M4 ;
        RECT  27.996 29.328 28.08 29.352 ;
    END
  END q[34]
  PIN q[350]
    DIRECTION OUTPUT ;
    USE SIGNAL ;
    PORT
      LAYER M4 ;
        RECT  27.996 45.072 28.08 45.096 ;
    END
  END q[350]
  PIN q[351]
    DIRECTION OUTPUT ;
    USE SIGNAL ;
    PORT
      LAYER M4 ;
        RECT  27.996 45.168 28.08 45.192 ;
    END
  END q[351]
  PIN q[352]
    DIRECTION OUTPUT ;
    USE SIGNAL ;
    PORT
      LAYER M4 ;
        RECT  27.996 45.264 28.08 45.288 ;
    END
  END q[352]
  PIN q[353]
    DIRECTION OUTPUT ;
    USE SIGNAL ;
    PORT
      LAYER M4 ;
        RECT  27.996 45.36 28.08 45.384 ;
    END
  END q[353]
  PIN q[354]
    DIRECTION OUTPUT ;
    USE SIGNAL ;
    PORT
      LAYER M4 ;
        RECT  27.996 45.456 28.08 45.48 ;
    END
  END q[354]
  PIN q[355]
    DIRECTION OUTPUT ;
    USE SIGNAL ;
    PORT
      LAYER M4 ;
        RECT  27.996 45.552 28.08 45.576 ;
    END
  END q[355]
  PIN q[356]
    DIRECTION OUTPUT ;
    USE SIGNAL ;
    PORT
      LAYER M4 ;
        RECT  27.996 45.648 28.08 45.672 ;
    END
  END q[356]
  PIN q[357]
    DIRECTION OUTPUT ;
    USE SIGNAL ;
    PORT
      LAYER M4 ;
        RECT  27.996 45.744 28.08 45.768 ;
    END
  END q[357]
  PIN q[358]
    DIRECTION OUTPUT ;
    USE SIGNAL ;
    PORT
      LAYER M4 ;
        RECT  27.996 45.84 28.08 45.864 ;
    END
  END q[358]
  PIN q[359]
    DIRECTION OUTPUT ;
    USE SIGNAL ;
    PORT
      LAYER M4 ;
        RECT  27.996 45.936 28.08 45.96 ;
    END
  END q[359]
  PIN q[35]
    DIRECTION OUTPUT ;
    USE SIGNAL ;
    PORT
      LAYER M4 ;
        RECT  27.996 29.424 28.08 29.448 ;
    END
  END q[35]
  PIN q[360]
    DIRECTION OUTPUT ;
    USE SIGNAL ;
    PORT
      LAYER M4 ;
        RECT  27.996 46.032 28.08 46.056 ;
    END
  END q[360]
  PIN q[361]
    DIRECTION OUTPUT ;
    USE SIGNAL ;
    PORT
      LAYER M4 ;
        RECT  27.996 46.128 28.08 46.152 ;
    END
  END q[361]
  PIN q[362]
    DIRECTION OUTPUT ;
    USE SIGNAL ;
    PORT
      LAYER M4 ;
        RECT  27.996 46.224 28.08 46.248 ;
    END
  END q[362]
  PIN q[363]
    DIRECTION OUTPUT ;
    USE SIGNAL ;
    PORT
      LAYER M4 ;
        RECT  27.996 46.32 28.08 46.344 ;
    END
  END q[363]
  PIN q[364]
    DIRECTION OUTPUT ;
    USE SIGNAL ;
    PORT
      LAYER M4 ;
        RECT  27.996 46.416 28.08 46.44 ;
    END
  END q[364]
  PIN q[365]
    DIRECTION OUTPUT ;
    USE SIGNAL ;
    PORT
      LAYER M4 ;
        RECT  27.996 46.512 28.08 46.536 ;
    END
  END q[365]
  PIN q[366]
    DIRECTION OUTPUT ;
    USE SIGNAL ;
    PORT
      LAYER M4 ;
        RECT  27.996 46.608 28.08 46.632 ;
    END
  END q[366]
  PIN q[367]
    DIRECTION OUTPUT ;
    USE SIGNAL ;
    PORT
      LAYER M4 ;
        RECT  27.996 46.704 28.08 46.728 ;
    END
  END q[367]
  PIN q[368]
    DIRECTION OUTPUT ;
    USE SIGNAL ;
    PORT
      LAYER M4 ;
        RECT  27.996 46.8 28.08 46.824 ;
    END
  END q[368]
  PIN q[369]
    DIRECTION OUTPUT ;
    USE SIGNAL ;
    PORT
      LAYER M4 ;
        RECT  27.996 46.896 28.08 46.92 ;
    END
  END q[369]
  PIN q[36]
    DIRECTION OUTPUT ;
    USE SIGNAL ;
    PORT
      LAYER M4 ;
        RECT  27.996 29.52 28.08 29.544 ;
    END
  END q[36]
  PIN q[370]
    DIRECTION OUTPUT ;
    USE SIGNAL ;
    PORT
      LAYER M4 ;
        RECT  27.996 46.992 28.08 47.016 ;
    END
  END q[370]
  PIN q[371]
    DIRECTION OUTPUT ;
    USE SIGNAL ;
    PORT
      LAYER M4 ;
        RECT  27.996 47.088 28.08 47.112 ;
    END
  END q[371]
  PIN q[372]
    DIRECTION OUTPUT ;
    USE SIGNAL ;
    PORT
      LAYER M4 ;
        RECT  27.996 47.184 28.08 47.208 ;
    END
  END q[372]
  PIN q[373]
    DIRECTION OUTPUT ;
    USE SIGNAL ;
    PORT
      LAYER M4 ;
        RECT  27.996 47.28 28.08 47.304 ;
    END
  END q[373]
  PIN q[374]
    DIRECTION OUTPUT ;
    USE SIGNAL ;
    PORT
      LAYER M4 ;
        RECT  27.996 47.376 28.08 47.4 ;
    END
  END q[374]
  PIN q[375]
    DIRECTION OUTPUT ;
    USE SIGNAL ;
    PORT
      LAYER M4 ;
        RECT  27.996 47.472 28.08 47.496 ;
    END
  END q[375]
  PIN q[376]
    DIRECTION OUTPUT ;
    USE SIGNAL ;
    PORT
      LAYER M4 ;
        RECT  27.996 47.568 28.08 47.592 ;
    END
  END q[376]
  PIN q[377]
    DIRECTION OUTPUT ;
    USE SIGNAL ;
    PORT
      LAYER M4 ;
        RECT  27.996 47.664 28.08 47.688 ;
    END
  END q[377]
  PIN q[378]
    DIRECTION OUTPUT ;
    USE SIGNAL ;
    PORT
      LAYER M4 ;
        RECT  27.996 47.76 28.08 47.784 ;
    END
  END q[378]
  PIN q[379]
    DIRECTION OUTPUT ;
    USE SIGNAL ;
    PORT
      LAYER M4 ;
        RECT  27.996 47.856 28.08 47.88 ;
    END
  END q[379]
  PIN q[37]
    DIRECTION OUTPUT ;
    USE SIGNAL ;
    PORT
      LAYER M4 ;
        RECT  27.996 29.616 28.08 29.64 ;
    END
  END q[37]
  PIN q[380]
    DIRECTION OUTPUT ;
    USE SIGNAL ;
    PORT
      LAYER M4 ;
        RECT  27.996 47.952 28.08 47.976 ;
    END
  END q[380]
  PIN q[381]
    DIRECTION OUTPUT ;
    USE SIGNAL ;
    PORT
      LAYER M4 ;
        RECT  27.996 48.048 28.08 48.072 ;
    END
  END q[381]
  PIN q[382]
    DIRECTION OUTPUT ;
    USE SIGNAL ;
    PORT
      LAYER M4 ;
        RECT  27.996 48.144 28.08 48.168 ;
    END
  END q[382]
  PIN q[383]
    DIRECTION OUTPUT ;
    USE SIGNAL ;
    PORT
      LAYER M4 ;
        RECT  27.996 48.24 28.08 48.264 ;
    END
  END q[383]
  PIN q[384]
    DIRECTION OUTPUT ;
    USE SIGNAL ;
    PORT
      LAYER M4 ;
        RECT  27.996 48.336 28.08 48.36 ;
    END
  END q[384]
  PIN q[385]
    DIRECTION OUTPUT ;
    USE SIGNAL ;
    PORT
      LAYER M4 ;
        RECT  27.996 48.432 28.08 48.456 ;
    END
  END q[385]
  PIN q[386]
    DIRECTION OUTPUT ;
    USE SIGNAL ;
    PORT
      LAYER M4 ;
        RECT  27.996 48.528 28.08 48.552 ;
    END
  END q[386]
  PIN q[387]
    DIRECTION OUTPUT ;
    USE SIGNAL ;
    PORT
      LAYER M4 ;
        RECT  27.996 48.624 28.08 48.648 ;
    END
  END q[387]
  PIN q[388]
    DIRECTION OUTPUT ;
    USE SIGNAL ;
    PORT
      LAYER M4 ;
        RECT  27.996 48.72 28.08 48.744 ;
    END
  END q[388]
  PIN q[389]
    DIRECTION OUTPUT ;
    USE SIGNAL ;
    PORT
      LAYER M4 ;
        RECT  27.996 48.816 28.08 48.84 ;
    END
  END q[389]
  PIN q[38]
    DIRECTION OUTPUT ;
    USE SIGNAL ;
    PORT
      LAYER M4 ;
        RECT  27.996 29.712 28.08 29.736 ;
    END
  END q[38]
  PIN q[390]
    DIRECTION OUTPUT ;
    USE SIGNAL ;
    PORT
      LAYER M4 ;
        RECT  27.996 48.912 28.08 48.936 ;
    END
  END q[390]
  PIN q[391]
    DIRECTION OUTPUT ;
    USE SIGNAL ;
    PORT
      LAYER M4 ;
        RECT  27.996 49.008 28.08 49.032 ;
    END
  END q[391]
  PIN q[392]
    DIRECTION OUTPUT ;
    USE SIGNAL ;
    PORT
      LAYER M4 ;
        RECT  27.996 49.104 28.08 49.128 ;
    END
  END q[392]
  PIN q[393]
    DIRECTION OUTPUT ;
    USE SIGNAL ;
    PORT
      LAYER M4 ;
        RECT  27.996 49.2 28.08 49.224 ;
    END
  END q[393]
  PIN q[394]
    DIRECTION OUTPUT ;
    USE SIGNAL ;
    PORT
      LAYER M4 ;
        RECT  27.996 49.296 28.08 49.32 ;
    END
  END q[394]
  PIN q[395]
    DIRECTION OUTPUT ;
    USE SIGNAL ;
    PORT
      LAYER M4 ;
        RECT  27.996 49.392 28.08 49.416 ;
    END
  END q[395]
  PIN q[396]
    DIRECTION OUTPUT ;
    USE SIGNAL ;
    PORT
      LAYER M4 ;
        RECT  27.996 49.488 28.08 49.512 ;
    END
  END q[396]
  PIN q[397]
    DIRECTION OUTPUT ;
    USE SIGNAL ;
    PORT
      LAYER M4 ;
        RECT  27.996 49.584 28.08 49.608 ;
    END
  END q[397]
  PIN q[398]
    DIRECTION OUTPUT ;
    USE SIGNAL ;
    PORT
      LAYER M4 ;
        RECT  27.996 49.68 28.08 49.704 ;
    END
  END q[398]
  PIN q[399]
    DIRECTION OUTPUT ;
    USE SIGNAL ;
    PORT
      LAYER M4 ;
        RECT  27.996 49.776 28.08 49.8 ;
    END
  END q[399]
  PIN q[39]
    DIRECTION OUTPUT ;
    USE SIGNAL ;
    PORT
      LAYER M4 ;
        RECT  27.996 29.808 28.08 29.832 ;
    END
  END q[39]
  PIN q[3]
    DIRECTION OUTPUT ;
    USE SIGNAL ;
    PORT
      LAYER M4 ;
        RECT  27.996 20.208 28.08 20.232 ;
    END
  END q[3]
  PIN q[400]
    DIRECTION OUTPUT ;
    USE SIGNAL ;
    PORT
      LAYER M4 ;
        RECT  27.996 49.872 28.08 49.896 ;
    END
  END q[400]
  PIN q[401]
    DIRECTION OUTPUT ;
    USE SIGNAL ;
    PORT
      LAYER M4 ;
        RECT  27.996 49.968 28.08 49.992 ;
    END
  END q[401]
  PIN q[402]
    DIRECTION OUTPUT ;
    USE SIGNAL ;
    PORT
      LAYER M4 ;
        RECT  27.996 50.064 28.08 50.088 ;
    END
  END q[402]
  PIN q[403]
    DIRECTION OUTPUT ;
    USE SIGNAL ;
    PORT
      LAYER M4 ;
        RECT  27.996 50.16 28.08 50.184 ;
    END
  END q[403]
  PIN q[404]
    DIRECTION OUTPUT ;
    USE SIGNAL ;
    PORT
      LAYER M4 ;
        RECT  27.996 50.256 28.08 50.28 ;
    END
  END q[404]
  PIN q[405]
    DIRECTION OUTPUT ;
    USE SIGNAL ;
    PORT
      LAYER M4 ;
        RECT  27.996 50.352 28.08 50.376 ;
    END
  END q[405]
  PIN q[406]
    DIRECTION OUTPUT ;
    USE SIGNAL ;
    PORT
      LAYER M4 ;
        RECT  27.996 50.448 28.08 50.472 ;
    END
  END q[406]
  PIN q[407]
    DIRECTION OUTPUT ;
    USE SIGNAL ;
    PORT
      LAYER M4 ;
        RECT  27.996 50.544 28.08 50.568 ;
    END
  END q[407]
  PIN q[408]
    DIRECTION OUTPUT ;
    USE SIGNAL ;
    PORT
      LAYER M4 ;
        RECT  27.996 50.64 28.08 50.664 ;
    END
  END q[408]
  PIN q[409]
    DIRECTION OUTPUT ;
    USE SIGNAL ;
    PORT
      LAYER M4 ;
        RECT  27.996 50.736 28.08 50.76 ;
    END
  END q[409]
  PIN q[40]
    DIRECTION OUTPUT ;
    USE SIGNAL ;
    PORT
      LAYER M4 ;
        RECT  27.996 29.904 28.08 29.928 ;
    END
  END q[40]
  PIN q[410]
    DIRECTION OUTPUT ;
    USE SIGNAL ;
    PORT
      LAYER M4 ;
        RECT  27.996 50.832 28.08 50.856 ;
    END
  END q[410]
  PIN q[411]
    DIRECTION OUTPUT ;
    USE SIGNAL ;
    PORT
      LAYER M4 ;
        RECT  27.996 50.928 28.08 50.952 ;
    END
  END q[411]
  PIN q[412]
    DIRECTION OUTPUT ;
    USE SIGNAL ;
    PORT
      LAYER M4 ;
        RECT  27.996 51.024 28.08 51.048 ;
    END
  END q[412]
  PIN q[413]
    DIRECTION OUTPUT ;
    USE SIGNAL ;
    PORT
      LAYER M4 ;
        RECT  27.996 51.12 28.08 51.144 ;
    END
  END q[413]
  PIN q[414]
    DIRECTION OUTPUT ;
    USE SIGNAL ;
    PORT
      LAYER M4 ;
        RECT  27.996 51.216 28.08 51.24 ;
    END
  END q[414]
  PIN q[415]
    DIRECTION OUTPUT ;
    USE SIGNAL ;
    PORT
      LAYER M4 ;
        RECT  27.996 51.312 28.08 51.336 ;
    END
  END q[415]
  PIN q[416]
    DIRECTION OUTPUT ;
    USE SIGNAL ;
    PORT
      LAYER M4 ;
        RECT  27.996 39.12 28.08 39.144 ;
    END
  END q[416]
  PIN q[417]
    DIRECTION OUTPUT ;
    USE SIGNAL ;
    PORT
      LAYER M4 ;
        RECT  27.996 39.216 28.08 39.24 ;
    END
  END q[417]
  PIN q[418]
    DIRECTION OUTPUT ;
    USE SIGNAL ;
    PORT
      LAYER M4 ;
        RECT  27.996 39.312 28.08 39.336 ;
    END
  END q[418]
  PIN q[419]
    DIRECTION OUTPUT ;
    USE SIGNAL ;
    PORT
      LAYER M4 ;
        RECT  27.996 39.408 28.08 39.432 ;
    END
  END q[419]
  PIN q[41]
    DIRECTION OUTPUT ;
    USE SIGNAL ;
    PORT
      LAYER M4 ;
        RECT  27.996 30 28.08 30.024 ;
    END
  END q[41]
  PIN q[420]
    DIRECTION OUTPUT ;
    USE SIGNAL ;
    PORT
      LAYER M4 ;
        RECT  27.996 39.504 28.08 39.528 ;
    END
  END q[420]
  PIN q[421]
    DIRECTION OUTPUT ;
    USE SIGNAL ;
    PORT
      LAYER M4 ;
        RECT  27.996 39.6 28.08 39.624 ;
    END
  END q[421]
  PIN q[422]
    DIRECTION OUTPUT ;
    USE SIGNAL ;
    PORT
      LAYER M4 ;
        RECT  27.996 39.696 28.08 39.72 ;
    END
  END q[422]
  PIN q[423]
    DIRECTION OUTPUT ;
    USE SIGNAL ;
    PORT
      LAYER M4 ;
        RECT  27.996 39.792 28.08 39.816 ;
    END
  END q[423]
  PIN q[424]
    DIRECTION OUTPUT ;
    USE SIGNAL ;
    PORT
      LAYER M4 ;
        RECT  27.996 39.888 28.08 39.912 ;
    END
  END q[424]
  PIN q[425]
    DIRECTION OUTPUT ;
    USE SIGNAL ;
    PORT
      LAYER M4 ;
        RECT  27.996 39.984 28.08 40.008 ;
    END
  END q[425]
  PIN q[426]
    DIRECTION OUTPUT ;
    USE SIGNAL ;
    PORT
      LAYER M4 ;
        RECT  27.996 40.08 28.08 40.104 ;
    END
  END q[426]
  PIN q[427]
    DIRECTION OUTPUT ;
    USE SIGNAL ;
    PORT
      LAYER M4 ;
        RECT  27.996 40.176 28.08 40.2 ;
    END
  END q[427]
  PIN q[428]
    DIRECTION OUTPUT ;
    USE SIGNAL ;
    PORT
      LAYER M4 ;
        RECT  27.996 40.272 28.08 40.296 ;
    END
  END q[428]
  PIN q[429]
    DIRECTION OUTPUT ;
    USE SIGNAL ;
    PORT
      LAYER M4 ;
        RECT  27.996 40.368 28.08 40.392 ;
    END
  END q[429]
  PIN q[42]
    DIRECTION OUTPUT ;
    USE SIGNAL ;
    PORT
      LAYER M4 ;
        RECT  27.996 30.096 28.08 30.12 ;
    END
  END q[42]
  PIN q[430]
    DIRECTION OUTPUT ;
    USE SIGNAL ;
    PORT
      LAYER M4 ;
        RECT  27.996 40.464 28.08 40.488 ;
    END
  END q[430]
  PIN q[431]
    DIRECTION OUTPUT ;
    USE SIGNAL ;
    PORT
      LAYER M4 ;
        RECT  27.996 40.56 28.08 40.584 ;
    END
  END q[431]
  PIN q[432]
    DIRECTION OUTPUT ;
    USE SIGNAL ;
    PORT
      LAYER M4 ;
        RECT  27.996 40.656 28.08 40.68 ;
    END
  END q[432]
  PIN q[433]
    DIRECTION OUTPUT ;
    USE SIGNAL ;
    PORT
      LAYER M4 ;
        RECT  27.996 40.752 28.08 40.776 ;
    END
  END q[433]
  PIN q[434]
    DIRECTION OUTPUT ;
    USE SIGNAL ;
    PORT
      LAYER M4 ;
        RECT  27.996 40.848 28.08 40.872 ;
    END
  END q[434]
  PIN q[435]
    DIRECTION OUTPUT ;
    USE SIGNAL ;
    PORT
      LAYER M4 ;
        RECT  27.996 40.944 28.08 40.968 ;
    END
  END q[435]
  PIN q[436]
    DIRECTION OUTPUT ;
    USE SIGNAL ;
    PORT
      LAYER M4 ;
        RECT  27.996 41.04 28.08 41.064 ;
    END
  END q[436]
  PIN q[437]
    DIRECTION OUTPUT ;
    USE SIGNAL ;
    PORT
      LAYER M4 ;
        RECT  27.996 41.136 28.08 41.16 ;
    END
  END q[437]
  PIN q[438]
    DIRECTION OUTPUT ;
    USE SIGNAL ;
    PORT
      LAYER M4 ;
        RECT  27.996 41.232 28.08 41.256 ;
    END
  END q[438]
  PIN q[439]
    DIRECTION OUTPUT ;
    USE SIGNAL ;
    PORT
      LAYER M4 ;
        RECT  27.996 41.328 28.08 41.352 ;
    END
  END q[439]
  PIN q[43]
    DIRECTION OUTPUT ;
    USE SIGNAL ;
    PORT
      LAYER M4 ;
        RECT  27.996 30.192 28.08 30.216 ;
    END
  END q[43]
  PIN q[440]
    DIRECTION OUTPUT ;
    USE SIGNAL ;
    PORT
      LAYER M4 ;
        RECT  27.996 41.424 28.08 41.448 ;
    END
  END q[440]
  PIN q[441]
    DIRECTION OUTPUT ;
    USE SIGNAL ;
    PORT
      LAYER M4 ;
        RECT  27.996 41.52 28.08 41.544 ;
    END
  END q[441]
  PIN q[442]
    DIRECTION OUTPUT ;
    USE SIGNAL ;
    PORT
      LAYER M4 ;
        RECT  27.996 41.616 28.08 41.64 ;
    END
  END q[442]
  PIN q[443]
    DIRECTION OUTPUT ;
    USE SIGNAL ;
    PORT
      LAYER M4 ;
        RECT  27.996 41.712 28.08 41.736 ;
    END
  END q[443]
  PIN q[444]
    DIRECTION OUTPUT ;
    USE SIGNAL ;
    PORT
      LAYER M4 ;
        RECT  27.996 41.808 28.08 41.832 ;
    END
  END q[444]
  PIN q[445]
    DIRECTION OUTPUT ;
    USE SIGNAL ;
    PORT
      LAYER M4 ;
        RECT  27.996 41.904 28.08 41.928 ;
    END
  END q[445]
  PIN q[446]
    DIRECTION OUTPUT ;
    USE SIGNAL ;
    PORT
      LAYER M4 ;
        RECT  27.996 42 28.08 42.024 ;
    END
  END q[446]
  PIN q[447]
    DIRECTION OUTPUT ;
    USE SIGNAL ;
    PORT
      LAYER M4 ;
        RECT  27.996 42.096 28.08 42.12 ;
    END
  END q[447]
  PIN q[448]
    DIRECTION OUTPUT ;
    USE SIGNAL ;
    PORT
      LAYER M4 ;
        RECT  27.996 6.864 28.08 6.888 ;
    END
  END q[448]
  PIN q[449]
    DIRECTION OUTPUT ;
    USE SIGNAL ;
    PORT
      LAYER M4 ;
        RECT  27.996 6.96 28.08 6.984 ;
    END
  END q[449]
  PIN q[44]
    DIRECTION OUTPUT ;
    USE SIGNAL ;
    PORT
      LAYER M4 ;
        RECT  27.996 30.288 28.08 30.312 ;
    END
  END q[44]
  PIN q[450]
    DIRECTION OUTPUT ;
    USE SIGNAL ;
    PORT
      LAYER M4 ;
        RECT  27.996 7.056 28.08 7.08 ;
    END
  END q[450]
  PIN q[451]
    DIRECTION OUTPUT ;
    USE SIGNAL ;
    PORT
      LAYER M4 ;
        RECT  27.996 7.152 28.08 7.176 ;
    END
  END q[451]
  PIN q[452]
    DIRECTION OUTPUT ;
    USE SIGNAL ;
    PORT
      LAYER M4 ;
        RECT  27.996 7.248 28.08 7.272 ;
    END
  END q[452]
  PIN q[453]
    DIRECTION OUTPUT ;
    USE SIGNAL ;
    PORT
      LAYER M4 ;
        RECT  27.996 7.344 28.08 7.368 ;
    END
  END q[453]
  PIN q[454]
    DIRECTION OUTPUT ;
    USE SIGNAL ;
    PORT
      LAYER M4 ;
        RECT  27.996 7.44 28.08 7.464 ;
    END
  END q[454]
  PIN q[455]
    DIRECTION OUTPUT ;
    USE SIGNAL ;
    PORT
      LAYER M4 ;
        RECT  27.996 7.536 28.08 7.56 ;
    END
  END q[455]
  PIN q[456]
    DIRECTION OUTPUT ;
    USE SIGNAL ;
    PORT
      LAYER M4 ;
        RECT  27.996 7.632 28.08 7.656 ;
    END
  END q[456]
  PIN q[457]
    DIRECTION OUTPUT ;
    USE SIGNAL ;
    PORT
      LAYER M4 ;
        RECT  27.996 7.728 28.08 7.752 ;
    END
  END q[457]
  PIN q[458]
    DIRECTION OUTPUT ;
    USE SIGNAL ;
    PORT
      LAYER M4 ;
        RECT  27.996 7.824 28.08 7.848 ;
    END
  END q[458]
  PIN q[459]
    DIRECTION OUTPUT ;
    USE SIGNAL ;
    PORT
      LAYER M4 ;
        RECT  27.996 7.92 28.08 7.944 ;
    END
  END q[459]
  PIN q[45]
    DIRECTION OUTPUT ;
    USE SIGNAL ;
    PORT
      LAYER M4 ;
        RECT  27.996 30.384 28.08 30.408 ;
    END
  END q[45]
  PIN q[460]
    DIRECTION OUTPUT ;
    USE SIGNAL ;
    PORT
      LAYER M4 ;
        RECT  27.996 8.016 28.08 8.04 ;
    END
  END q[460]
  PIN q[461]
    DIRECTION OUTPUT ;
    USE SIGNAL ;
    PORT
      LAYER M4 ;
        RECT  27.996 8.112 28.08 8.136 ;
    END
  END q[461]
  PIN q[462]
    DIRECTION OUTPUT ;
    USE SIGNAL ;
    PORT
      LAYER M4 ;
        RECT  27.996 8.208 28.08 8.232 ;
    END
  END q[462]
  PIN q[463]
    DIRECTION OUTPUT ;
    USE SIGNAL ;
    PORT
      LAYER M4 ;
        RECT  27.996 8.304 28.08 8.328 ;
    END
  END q[463]
  PIN q[464]
    DIRECTION OUTPUT ;
    USE SIGNAL ;
    PORT
      LAYER M4 ;
        RECT  27.996 8.4 28.08 8.424 ;
    END
  END q[464]
  PIN q[465]
    DIRECTION OUTPUT ;
    USE SIGNAL ;
    PORT
      LAYER M4 ;
        RECT  27.996 8.496 28.08 8.52 ;
    END
  END q[465]
  PIN q[466]
    DIRECTION OUTPUT ;
    USE SIGNAL ;
    PORT
      LAYER M4 ;
        RECT  27.996 8.592 28.08 8.616 ;
    END
  END q[466]
  PIN q[467]
    DIRECTION OUTPUT ;
    USE SIGNAL ;
    PORT
      LAYER M4 ;
        RECT  27.996 8.688 28.08 8.712 ;
    END
  END q[467]
  PIN q[468]
    DIRECTION OUTPUT ;
    USE SIGNAL ;
    PORT
      LAYER M4 ;
        RECT  27.996 8.784 28.08 8.808 ;
    END
  END q[468]
  PIN q[469]
    DIRECTION OUTPUT ;
    USE SIGNAL ;
    PORT
      LAYER M4 ;
        RECT  27.996 8.88 28.08 8.904 ;
    END
  END q[469]
  PIN q[46]
    DIRECTION OUTPUT ;
    USE SIGNAL ;
    PORT
      LAYER M4 ;
        RECT  27.996 30.48 28.08 30.504 ;
    END
  END q[46]
  PIN q[470]
    DIRECTION OUTPUT ;
    USE SIGNAL ;
    PORT
      LAYER M4 ;
        RECT  27.996 8.976 28.08 9 ;
    END
  END q[470]
  PIN q[471]
    DIRECTION OUTPUT ;
    USE SIGNAL ;
    PORT
      LAYER M4 ;
        RECT  27.996 9.072 28.08 9.096 ;
    END
  END q[471]
  PIN q[472]
    DIRECTION OUTPUT ;
    USE SIGNAL ;
    PORT
      LAYER M4 ;
        RECT  27.996 9.168 28.08 9.192 ;
    END
  END q[472]
  PIN q[473]
    DIRECTION OUTPUT ;
    USE SIGNAL ;
    PORT
      LAYER M4 ;
        RECT  27.996 9.264 28.08 9.288 ;
    END
  END q[473]
  PIN q[474]
    DIRECTION OUTPUT ;
    USE SIGNAL ;
    PORT
      LAYER M4 ;
        RECT  27.996 9.36 28.08 9.384 ;
    END
  END q[474]
  PIN q[475]
    DIRECTION OUTPUT ;
    USE SIGNAL ;
    PORT
      LAYER M4 ;
        RECT  27.996 9.456 28.08 9.48 ;
    END
  END q[475]
  PIN q[476]
    DIRECTION OUTPUT ;
    USE SIGNAL ;
    PORT
      LAYER M4 ;
        RECT  27.996 9.552 28.08 9.576 ;
    END
  END q[476]
  PIN q[477]
    DIRECTION OUTPUT ;
    USE SIGNAL ;
    PORT
      LAYER M4 ;
        RECT  27.996 9.648 28.08 9.672 ;
    END
  END q[477]
  PIN q[478]
    DIRECTION OUTPUT ;
    USE SIGNAL ;
    PORT
      LAYER M4 ;
        RECT  27.996 9.744 28.08 9.768 ;
    END
  END q[478]
  PIN q[479]
    DIRECTION OUTPUT ;
    USE SIGNAL ;
    PORT
      LAYER M4 ;
        RECT  27.996 9.84 28.08 9.864 ;
    END
  END q[479]
  PIN q[47]
    DIRECTION OUTPUT ;
    USE SIGNAL ;
    PORT
      LAYER M4 ;
        RECT  27.996 30.576 28.08 30.6 ;
    END
  END q[47]
  PIN q[480]
    DIRECTION OUTPUT ;
    USE SIGNAL ;
    PORT
      LAYER M4 ;
        RECT  27.996 16.08 28.08 16.104 ;
    END
  END q[480]
  PIN q[481]
    DIRECTION OUTPUT ;
    USE SIGNAL ;
    PORT
      LAYER M4 ;
        RECT  27.996 16.176 28.08 16.2 ;
    END
  END q[481]
  PIN q[482]
    DIRECTION OUTPUT ;
    USE SIGNAL ;
    PORT
      LAYER M4 ;
        RECT  27.996 16.272 28.08 16.296 ;
    END
  END q[482]
  PIN q[483]
    DIRECTION OUTPUT ;
    USE SIGNAL ;
    PORT
      LAYER M4 ;
        RECT  27.996 16.368 28.08 16.392 ;
    END
  END q[483]
  PIN q[484]
    DIRECTION OUTPUT ;
    USE SIGNAL ;
    PORT
      LAYER M4 ;
        RECT  27.996 16.464 28.08 16.488 ;
    END
  END q[484]
  PIN q[485]
    DIRECTION OUTPUT ;
    USE SIGNAL ;
    PORT
      LAYER M4 ;
        RECT  27.996 16.56 28.08 16.584 ;
    END
  END q[485]
  PIN q[486]
    DIRECTION OUTPUT ;
    USE SIGNAL ;
    PORT
      LAYER M4 ;
        RECT  27.996 16.656 28.08 16.68 ;
    END
  END q[486]
  PIN q[487]
    DIRECTION OUTPUT ;
    USE SIGNAL ;
    PORT
      LAYER M4 ;
        RECT  27.996 16.752 28.08 16.776 ;
    END
  END q[487]
  PIN q[488]
    DIRECTION OUTPUT ;
    USE SIGNAL ;
    PORT
      LAYER M4 ;
        RECT  27.996 16.848 28.08 16.872 ;
    END
  END q[488]
  PIN q[489]
    DIRECTION OUTPUT ;
    USE SIGNAL ;
    PORT
      LAYER M4 ;
        RECT  27.996 16.944 28.08 16.968 ;
    END
  END q[489]
  PIN q[48]
    DIRECTION OUTPUT ;
    USE SIGNAL ;
    PORT
      LAYER M4 ;
        RECT  27.996 30.672 28.08 30.696 ;
    END
  END q[48]
  PIN q[490]
    DIRECTION OUTPUT ;
    USE SIGNAL ;
    PORT
      LAYER M4 ;
        RECT  27.996 17.04 28.08 17.064 ;
    END
  END q[490]
  PIN q[491]
    DIRECTION OUTPUT ;
    USE SIGNAL ;
    PORT
      LAYER M4 ;
        RECT  27.996 17.136 28.08 17.16 ;
    END
  END q[491]
  PIN q[492]
    DIRECTION OUTPUT ;
    USE SIGNAL ;
    PORT
      LAYER M4 ;
        RECT  27.996 17.232 28.08 17.256 ;
    END
  END q[492]
  PIN q[493]
    DIRECTION OUTPUT ;
    USE SIGNAL ;
    PORT
      LAYER M4 ;
        RECT  27.996 17.328 28.08 17.352 ;
    END
  END q[493]
  PIN q[494]
    DIRECTION OUTPUT ;
    USE SIGNAL ;
    PORT
      LAYER M4 ;
        RECT  27.996 17.424 28.08 17.448 ;
    END
  END q[494]
  PIN q[495]
    DIRECTION OUTPUT ;
    USE SIGNAL ;
    PORT
      LAYER M4 ;
        RECT  27.996 17.52 28.08 17.544 ;
    END
  END q[495]
  PIN q[496]
    DIRECTION OUTPUT ;
    USE SIGNAL ;
    PORT
      LAYER M4 ;
        RECT  27.996 17.616 28.08 17.64 ;
    END
  END q[496]
  PIN q[497]
    DIRECTION OUTPUT ;
    USE SIGNAL ;
    PORT
      LAYER M4 ;
        RECT  27.996 17.712 28.08 17.736 ;
    END
  END q[497]
  PIN q[498]
    DIRECTION OUTPUT ;
    USE SIGNAL ;
    PORT
      LAYER M4 ;
        RECT  27.996 17.808 28.08 17.832 ;
    END
  END q[498]
  PIN q[499]
    DIRECTION OUTPUT ;
    USE SIGNAL ;
    PORT
      LAYER M4 ;
        RECT  27.996 17.904 28.08 17.928 ;
    END
  END q[499]
  PIN q[49]
    DIRECTION OUTPUT ;
    USE SIGNAL ;
    PORT
      LAYER M4 ;
        RECT  27.996 30.768 28.08 30.792 ;
    END
  END q[49]
  PIN q[4]
    DIRECTION OUTPUT ;
    USE SIGNAL ;
    PORT
      LAYER M4 ;
        RECT  27.996 20.304 28.08 20.328 ;
    END
  END q[4]
  PIN q[500]
    DIRECTION OUTPUT ;
    USE SIGNAL ;
    PORT
      LAYER M4 ;
        RECT  27.996 18 28.08 18.024 ;
    END
  END q[500]
  PIN q[501]
    DIRECTION OUTPUT ;
    USE SIGNAL ;
    PORT
      LAYER M4 ;
        RECT  27.996 18.096 28.08 18.12 ;
    END
  END q[501]
  PIN q[502]
    DIRECTION OUTPUT ;
    USE SIGNAL ;
    PORT
      LAYER M4 ;
        RECT  27.996 18.192 28.08 18.216 ;
    END
  END q[502]
  PIN q[503]
    DIRECTION OUTPUT ;
    USE SIGNAL ;
    PORT
      LAYER M4 ;
        RECT  27.996 18.288 28.08 18.312 ;
    END
  END q[503]
  PIN q[504]
    DIRECTION OUTPUT ;
    USE SIGNAL ;
    PORT
      LAYER M4 ;
        RECT  27.996 18.384 28.08 18.408 ;
    END
  END q[504]
  PIN q[505]
    DIRECTION OUTPUT ;
    USE SIGNAL ;
    PORT
      LAYER M4 ;
        RECT  27.996 18.48 28.08 18.504 ;
    END
  END q[505]
  PIN q[506]
    DIRECTION OUTPUT ;
    USE SIGNAL ;
    PORT
      LAYER M4 ;
        RECT  27.996 18.576 28.08 18.6 ;
    END
  END q[506]
  PIN q[507]
    DIRECTION OUTPUT ;
    USE SIGNAL ;
    PORT
      LAYER M4 ;
        RECT  27.996 18.672 28.08 18.696 ;
    END
  END q[507]
  PIN q[508]
    DIRECTION OUTPUT ;
    USE SIGNAL ;
    PORT
      LAYER M4 ;
        RECT  27.996 18.768 28.08 18.792 ;
    END
  END q[508]
  PIN q[509]
    DIRECTION OUTPUT ;
    USE SIGNAL ;
    PORT
      LAYER M4 ;
        RECT  27.996 18.864 28.08 18.888 ;
    END
  END q[509]
  PIN q[50]
    DIRECTION OUTPUT ;
    USE SIGNAL ;
    PORT
      LAYER M4 ;
        RECT  27.996 30.864 28.08 30.888 ;
    END
  END q[50]
  PIN q[510]
    DIRECTION OUTPUT ;
    USE SIGNAL ;
    PORT
      LAYER M4 ;
        RECT  27.996 18.96 28.08 18.984 ;
    END
  END q[510]
  PIN q[511]
    DIRECTION OUTPUT ;
    USE SIGNAL ;
    PORT
      LAYER M4 ;
        RECT  27.996 19.056 28.08 19.08 ;
    END
  END q[511]
  PIN q[51]
    DIRECTION OUTPUT ;
    USE SIGNAL ;
    PORT
      LAYER M4 ;
        RECT  27.996 30.96 28.08 30.984 ;
    END
  END q[51]
  PIN q[52]
    DIRECTION OUTPUT ;
    USE SIGNAL ;
    PORT
      LAYER M4 ;
        RECT  27.996 31.056 28.08 31.08 ;
    END
  END q[52]
  PIN q[53]
    DIRECTION OUTPUT ;
    USE SIGNAL ;
    PORT
      LAYER M4 ;
        RECT  27.996 31.152 28.08 31.176 ;
    END
  END q[53]
  PIN q[54]
    DIRECTION OUTPUT ;
    USE SIGNAL ;
    PORT
      LAYER M4 ;
        RECT  27.996 31.248 28.08 31.272 ;
    END
  END q[54]
  PIN q[55]
    DIRECTION OUTPUT ;
    USE SIGNAL ;
    PORT
      LAYER M4 ;
        RECT  27.996 31.344 28.08 31.368 ;
    END
  END q[55]
  PIN q[56]
    DIRECTION OUTPUT ;
    USE SIGNAL ;
    PORT
      LAYER M4 ;
        RECT  27.996 31.44 28.08 31.464 ;
    END
  END q[56]
  PIN q[57]
    DIRECTION OUTPUT ;
    USE SIGNAL ;
    PORT
      LAYER M4 ;
        RECT  27.996 31.536 28.08 31.56 ;
    END
  END q[57]
  PIN q[58]
    DIRECTION OUTPUT ;
    USE SIGNAL ;
    PORT
      LAYER M4 ;
        RECT  27.996 31.632 28.08 31.656 ;
    END
  END q[58]
  PIN q[59]
    DIRECTION OUTPUT ;
    USE SIGNAL ;
    PORT
      LAYER M4 ;
        RECT  27.996 31.728 28.08 31.752 ;
    END
  END q[59]
  PIN q[5]
    DIRECTION OUTPUT ;
    USE SIGNAL ;
    PORT
      LAYER M4 ;
        RECT  27.996 20.4 28.08 20.424 ;
    END
  END q[5]
  PIN q[60]
    DIRECTION OUTPUT ;
    USE SIGNAL ;
    PORT
      LAYER M4 ;
        RECT  27.996 31.824 28.08 31.848 ;
    END
  END q[60]
  PIN q[61]
    DIRECTION OUTPUT ;
    USE SIGNAL ;
    PORT
      LAYER M4 ;
        RECT  27.996 31.92 28.08 31.944 ;
    END
  END q[61]
  PIN q[62]
    DIRECTION OUTPUT ;
    USE SIGNAL ;
    PORT
      LAYER M4 ;
        RECT  27.996 32.016 28.08 32.04 ;
    END
  END q[62]
  PIN q[63]
    DIRECTION OUTPUT ;
    USE SIGNAL ;
    PORT
      LAYER M4 ;
        RECT  27.996 32.112 28.08 32.136 ;
    END
  END q[63]
  PIN q[64]
    DIRECTION OUTPUT ;
    USE SIGNAL ;
    PORT
      LAYER M4 ;
        RECT  27.996 22.992 28.08 23.016 ;
    END
  END q[64]
  PIN q[65]
    DIRECTION OUTPUT ;
    USE SIGNAL ;
    PORT
      LAYER M4 ;
        RECT  27.996 23.088 28.08 23.112 ;
    END
  END q[65]
  PIN q[66]
    DIRECTION OUTPUT ;
    USE SIGNAL ;
    PORT
      LAYER M4 ;
        RECT  27.996 23.184 28.08 23.208 ;
    END
  END q[66]
  PIN q[67]
    DIRECTION OUTPUT ;
    USE SIGNAL ;
    PORT
      LAYER M4 ;
        RECT  27.996 23.28 28.08 23.304 ;
    END
  END q[67]
  PIN q[68]
    DIRECTION OUTPUT ;
    USE SIGNAL ;
    PORT
      LAYER M4 ;
        RECT  27.996 23.376 28.08 23.4 ;
    END
  END q[68]
  PIN q[69]
    DIRECTION OUTPUT ;
    USE SIGNAL ;
    PORT
      LAYER M4 ;
        RECT  27.996 23.472 28.08 23.496 ;
    END
  END q[69]
  PIN q[6]
    DIRECTION OUTPUT ;
    USE SIGNAL ;
    PORT
      LAYER M4 ;
        RECT  27.996 20.496 28.08 20.52 ;
    END
  END q[6]
  PIN q[70]
    DIRECTION OUTPUT ;
    USE SIGNAL ;
    PORT
      LAYER M4 ;
        RECT  27.996 23.568 28.08 23.592 ;
    END
  END q[70]
  PIN q[71]
    DIRECTION OUTPUT ;
    USE SIGNAL ;
    PORT
      LAYER M4 ;
        RECT  27.996 23.664 28.08 23.688 ;
    END
  END q[71]
  PIN q[72]
    DIRECTION OUTPUT ;
    USE SIGNAL ;
    PORT
      LAYER M4 ;
        RECT  27.996 23.76 28.08 23.784 ;
    END
  END q[72]
  PIN q[73]
    DIRECTION OUTPUT ;
    USE SIGNAL ;
    PORT
      LAYER M4 ;
        RECT  27.996 23.856 28.08 23.88 ;
    END
  END q[73]
  PIN q[74]
    DIRECTION OUTPUT ;
    USE SIGNAL ;
    PORT
      LAYER M4 ;
        RECT  27.996 23.952 28.08 23.976 ;
    END
  END q[74]
  PIN q[75]
    DIRECTION OUTPUT ;
    USE SIGNAL ;
    PORT
      LAYER M4 ;
        RECT  27.996 24.048 28.08 24.072 ;
    END
  END q[75]
  PIN q[76]
    DIRECTION OUTPUT ;
    USE SIGNAL ;
    PORT
      LAYER M4 ;
        RECT  27.996 24.144 28.08 24.168 ;
    END
  END q[76]
  PIN q[77]
    DIRECTION OUTPUT ;
    USE SIGNAL ;
    PORT
      LAYER M4 ;
        RECT  27.996 24.24 28.08 24.264 ;
    END
  END q[77]
  PIN q[78]
    DIRECTION OUTPUT ;
    USE SIGNAL ;
    PORT
      LAYER M4 ;
        RECT  27.996 24.336 28.08 24.36 ;
    END
  END q[78]
  PIN q[79]
    DIRECTION OUTPUT ;
    USE SIGNAL ;
    PORT
      LAYER M4 ;
        RECT  27.996 24.432 28.08 24.456 ;
    END
  END q[79]
  PIN q[7]
    DIRECTION OUTPUT ;
    USE SIGNAL ;
    PORT
      LAYER M4 ;
        RECT  27.996 20.592 28.08 20.616 ;
    END
  END q[7]
  PIN q[80]
    DIRECTION OUTPUT ;
    USE SIGNAL ;
    PORT
      LAYER M4 ;
        RECT  27.996 24.528 28.08 24.552 ;
    END
  END q[80]
  PIN q[81]
    DIRECTION OUTPUT ;
    USE SIGNAL ;
    PORT
      LAYER M4 ;
        RECT  27.996 24.624 28.08 24.648 ;
    END
  END q[81]
  PIN q[82]
    DIRECTION OUTPUT ;
    USE SIGNAL ;
    PORT
      LAYER M4 ;
        RECT  27.996 24.72 28.08 24.744 ;
    END
  END q[82]
  PIN q[83]
    DIRECTION OUTPUT ;
    USE SIGNAL ;
    PORT
      LAYER M4 ;
        RECT  27.996 24.816 28.08 24.84 ;
    END
  END q[83]
  PIN q[84]
    DIRECTION OUTPUT ;
    USE SIGNAL ;
    PORT
      LAYER M4 ;
        RECT  27.996 24.912 28.08 24.936 ;
    END
  END q[84]
  PIN q[85]
    DIRECTION OUTPUT ;
    USE SIGNAL ;
    PORT
      LAYER M4 ;
        RECT  27.996 25.008 28.08 25.032 ;
    END
  END q[85]
  PIN q[86]
    DIRECTION OUTPUT ;
    USE SIGNAL ;
    PORT
      LAYER M4 ;
        RECT  27.996 25.104 28.08 25.128 ;
    END
  END q[86]
  PIN q[87]
    DIRECTION OUTPUT ;
    USE SIGNAL ;
    PORT
      LAYER M4 ;
        RECT  27.996 25.2 28.08 25.224 ;
    END
  END q[87]
  PIN q[88]
    DIRECTION OUTPUT ;
    USE SIGNAL ;
    PORT
      LAYER M4 ;
        RECT  27.996 25.296 28.08 25.32 ;
    END
  END q[88]
  PIN q[89]
    DIRECTION OUTPUT ;
    USE SIGNAL ;
    PORT
      LAYER M4 ;
        RECT  27.996 25.392 28.08 25.416 ;
    END
  END q[89]
  PIN q[8]
    DIRECTION OUTPUT ;
    USE SIGNAL ;
    PORT
      LAYER M4 ;
        RECT  27.996 20.688 28.08 20.712 ;
    END
  END q[8]
  PIN q[90]
    DIRECTION OUTPUT ;
    USE SIGNAL ;
    PORT
      LAYER M4 ;
        RECT  27.996 25.488 28.08 25.512 ;
    END
  END q[90]
  PIN q[91]
    DIRECTION OUTPUT ;
    USE SIGNAL ;
    PORT
      LAYER M4 ;
        RECT  27.996 25.584 28.08 25.608 ;
    END
  END q[91]
  PIN q[92]
    DIRECTION OUTPUT ;
    USE SIGNAL ;
    PORT
      LAYER M4 ;
        RECT  27.996 25.68 28.08 25.704 ;
    END
  END q[92]
  PIN q[93]
    DIRECTION OUTPUT ;
    USE SIGNAL ;
    PORT
      LAYER M4 ;
        RECT  27.996 25.776 28.08 25.8 ;
    END
  END q[93]
  PIN q[94]
    DIRECTION OUTPUT ;
    USE SIGNAL ;
    PORT
      LAYER M4 ;
        RECT  27.996 25.872 28.08 25.896 ;
    END
  END q[94]
  PIN q[95]
    DIRECTION OUTPUT ;
    USE SIGNAL ;
    PORT
      LAYER M4 ;
        RECT  27.996 25.968 28.08 25.992 ;
    END
  END q[95]
  PIN q[96]
    DIRECTION OUTPUT ;
    USE SIGNAL ;
    PORT
      LAYER M4 ;
        RECT  27.996 26.064 28.08 26.088 ;
    END
  END q[96]
  PIN q[97]
    DIRECTION OUTPUT ;
    USE SIGNAL ;
    PORT
      LAYER M4 ;
        RECT  27.996 26.16 28.08 26.184 ;
    END
  END q[97]
  PIN q[98]
    DIRECTION OUTPUT ;
    USE SIGNAL ;
    PORT
      LAYER M4 ;
        RECT  27.996 26.256 28.08 26.28 ;
    END
  END q[98]
  PIN q[99]
    DIRECTION OUTPUT ;
    USE SIGNAL ;
    PORT
      LAYER M4 ;
        RECT  27.996 26.352 28.08 26.376 ;
    END
  END q[99]
  PIN q[9]
    DIRECTION OUTPUT ;
    USE SIGNAL ;
    PORT
      LAYER M4 ;
        RECT  27.996 20.784 28.08 20.808 ;
    END
  END q[9]
  PIN VDD
    DIRECTION INOUT ;
    USE POWER ;
    PORT
      LAYER M5 ;
        RECT  24.192 2.151 24.312 62.649 ;
        RECT  18.792 2.151 18.912 62.649 ;
        RECT  13.392 2.151 13.512 62.649 ;
        RECT  7.992 2.151 8.112 62.649 ;
        RECT  2.592 2.151 2.712 62.649 ;
    END
  END VDD
  PIN VSS
    DIRECTION INOUT ;
    USE GROUND ;
    PORT
      LAYER M5 ;
        RECT  24 2.137 24.12 62.663 ;
        RECT  18.6 2.137 18.72 62.663 ;
        RECT  13.2 2.137 13.32 62.663 ;
        RECT  7.8 2.137 7.92 62.663 ;
        RECT  2.4 2.137 2.52 62.663 ;
    END
  END VSS
  OBS
    LAYER RVTN ;
     RECT  2.16 2.16 25.92 2.295 ;
     RECT  2.16 2.565 25.92 2.835 ;
     RECT  2.16 3.105 25.92 3.375 ;
     RECT  2.16 3.645 25.92 3.915 ;
     RECT  2.16 4.185 25.92 4.455 ;
     RECT  2.16 4.725 25.92 4.995 ;
     RECT  2.16 5.265 25.92 5.535 ;
     RECT  2.16 5.805 25.92 6.075 ;
     RECT  2.16 6.345 25.92 6.615 ;
     RECT  2.16 6.885 25.92 7.155 ;
     RECT  2.16 7.425 25.92 7.695 ;
     RECT  2.16 7.965 25.92 8.235 ;
     RECT  2.16 8.505 25.92 8.775 ;
     RECT  2.16 9.045 25.92 9.315 ;
     RECT  2.16 9.585 25.92 9.855 ;
     RECT  2.16 10.125 25.92 10.395 ;
     RECT  2.16 10.665 25.92 10.935 ;
     RECT  2.16 11.205 25.92 11.475 ;
     RECT  2.16 11.745 25.92 12.015 ;
     RECT  2.16 12.285 25.92 12.555 ;
     RECT  2.16 12.825 25.92 13.095 ;
     RECT  2.16 13.365 25.92 13.635 ;
     RECT  2.16 13.905 25.92 14.175 ;
     RECT  2.16 14.445 25.92 14.715 ;
     RECT  2.16 14.985 25.92 15.255 ;
     RECT  2.16 15.525 25.92 15.795 ;
     RECT  2.16 16.065 25.92 16.335 ;
     RECT  2.16 16.605 25.92 16.875 ;
     RECT  2.16 17.145 25.92 17.415 ;
     RECT  2.16 17.685 25.92 17.955 ;
     RECT  2.16 18.225 25.92 18.495 ;
     RECT  2.16 18.765 25.92 19.035 ;
     RECT  2.16 19.305 25.92 19.575 ;
     RECT  2.16 19.845 25.92 20.115 ;
     RECT  2.16 20.385 25.92 20.655 ;
     RECT  2.16 20.925 25.92 21.195 ;
     RECT  2.16 21.465 25.92 21.735 ;
     RECT  2.16 22.005 25.92 22.275 ;
     RECT  2.16 22.545 25.92 22.815 ;
     RECT  2.16 23.085 25.92 23.355 ;
     RECT  2.16 23.625 25.92 23.895 ;
     RECT  2.16 24.165 25.92 24.435 ;
     RECT  2.16 24.705 25.92 24.975 ;
     RECT  2.16 25.245 25.92 25.515 ;
     RECT  2.16 25.785 25.92 26.055 ;
     RECT  2.16 26.325 25.92 26.595 ;
     RECT  2.16 26.865 25.92 27.135 ;
     RECT  2.16 27.405 25.92 27.675 ;
     RECT  2.16 27.945 25.92 28.215 ;
     RECT  2.16 28.485 25.92 28.755 ;
     RECT  2.16 29.025 25.92 29.295 ;
     RECT  2.16 29.565 25.92 29.835 ;
     RECT  2.16 30.105 25.92 30.375 ;
     RECT  2.16 30.645 25.92 30.915 ;
     RECT  2.16 31.185 25.92 31.455 ;
     RECT  2.16 31.725 25.92 31.995 ;
     RECT  2.16 32.265 25.92 32.535 ;
     RECT  2.16 32.805 25.92 33.075 ;
     RECT  2.16 33.345 25.92 33.615 ;
     RECT  2.16 33.885 25.92 34.155 ;
     RECT  2.16 34.425 25.92 34.695 ;
     RECT  2.16 34.965 25.92 35.235 ;
     RECT  2.16 35.505 25.92 35.775 ;
     RECT  2.16 36.045 25.92 36.315 ;
     RECT  2.16 36.585 25.92 36.855 ;
     RECT  2.16 37.125 25.92 37.395 ;
     RECT  2.16 37.665 25.92 37.935 ;
     RECT  2.16 38.205 25.92 38.475 ;
     RECT  2.16 38.745 25.92 39.015 ;
     RECT  2.16 39.285 25.92 39.555 ;
     RECT  2.16 39.825 25.92 40.095 ;
     RECT  2.16 40.365 25.92 40.635 ;
     RECT  2.16 40.905 25.92 41.175 ;
     RECT  2.16 41.445 25.92 41.715 ;
     RECT  2.16 41.985 25.92 42.255 ;
     RECT  2.16 42.525 25.92 42.795 ;
     RECT  2.16 43.065 25.92 43.335 ;
     RECT  2.16 43.605 25.92 43.875 ;
     RECT  2.16 44.145 25.92 44.415 ;
     RECT  2.16 44.685 25.92 44.955 ;
     RECT  2.16 45.225 25.92 45.495 ;
     RECT  2.16 45.765 25.92 46.035 ;
     RECT  2.16 46.305 25.92 46.575 ;
     RECT  2.16 46.845 25.92 47.115 ;
     RECT  2.16 47.385 25.92 47.655 ;
     RECT  2.16 47.925 25.92 48.195 ;
     RECT  2.16 48.465 25.92 48.735 ;
     RECT  2.16 49.005 25.92 49.275 ;
     RECT  2.16 49.545 25.92 49.815 ;
     RECT  2.16 50.085 25.92 50.355 ;
     RECT  2.16 50.625 25.92 50.895 ;
     RECT  2.16 51.165 25.92 51.435 ;
     RECT  2.16 51.705 25.92 51.975 ;
     RECT  2.16 52.245 25.92 52.515 ;
     RECT  2.16 52.785 25.92 53.055 ;
     RECT  2.16 53.325 25.92 53.595 ;
     RECT  2.16 53.865 25.92 54.135 ;
     RECT  2.16 54.405 25.92 54.675 ;
     RECT  2.16 54.945 25.92 55.215 ;
     RECT  2.16 55.485 25.92 55.755 ;
     RECT  2.16 56.025 25.92 56.295 ;
     RECT  2.16 56.565 25.92 56.835 ;
     RECT  2.16 57.105 25.92 57.375 ;
     RECT  2.16 57.645 25.92 57.915 ;
     RECT  2.16 58.185 25.92 58.455 ;
     RECT  2.16 58.725 25.92 58.995 ;
     RECT  2.16 59.265 25.92 59.535 ;
     RECT  2.16 59.805 25.92 60.075 ;
     RECT  2.16 60.345 25.92 60.615 ;
     RECT  2.16 60.885 25.92 61.155 ;
     RECT  2.16 61.425 25.92 61.695 ;
     RECT  2.16 61.965 25.92 62.235 ;
     RECT  2.16 62.505 25.92 62.64 ;
    LAYER RVTP ;
     RECT  2.16 2.295 25.92 2.565 ;
     RECT  2.16 2.835 25.92 3.105 ;
     RECT  2.16 3.375 25.92 3.645 ;
     RECT  2.16 3.915 25.92 4.185 ;
     RECT  2.16 4.455 25.92 4.725 ;
     RECT  2.16 4.995 25.92 5.265 ;
     RECT  2.16 5.535 25.92 5.805 ;
     RECT  2.16 6.075 25.92 6.345 ;
     RECT  2.16 6.615 25.92 6.885 ;
     RECT  2.16 7.155 25.92 7.425 ;
     RECT  2.16 7.695 25.92 7.965 ;
     RECT  2.16 8.235 25.92 8.505 ;
     RECT  2.16 8.775 25.92 9.045 ;
     RECT  2.16 9.315 25.92 9.585 ;
     RECT  2.16 9.855 25.92 10.125 ;
     RECT  2.16 10.395 25.92 10.665 ;
     RECT  2.16 10.935 25.92 11.205 ;
     RECT  2.16 11.475 25.92 11.745 ;
     RECT  2.16 12.015 25.92 12.285 ;
     RECT  2.16 12.555 25.92 12.825 ;
     RECT  2.16 13.095 25.92 13.365 ;
     RECT  2.16 13.635 25.92 13.905 ;
     RECT  2.16 14.175 25.92 14.445 ;
     RECT  2.16 14.715 25.92 14.985 ;
     RECT  2.16 15.255 25.92 15.525 ;
     RECT  2.16 15.795 25.92 16.065 ;
     RECT  2.16 16.335 25.92 16.605 ;
     RECT  2.16 16.875 25.92 17.145 ;
     RECT  2.16 17.415 25.92 17.685 ;
     RECT  2.16 17.955 25.92 18.225 ;
     RECT  2.16 18.495 25.92 18.765 ;
     RECT  2.16 19.035 25.92 19.305 ;
     RECT  2.16 19.575 25.92 19.845 ;
     RECT  2.16 20.115 25.92 20.385 ;
     RECT  2.16 20.655 25.92 20.925 ;
     RECT  2.16 21.195 25.92 21.465 ;
     RECT  2.16 21.735 25.92 22.005 ;
     RECT  2.16 22.275 25.92 22.545 ;
     RECT  2.16 22.815 25.92 23.085 ;
     RECT  2.16 23.355 25.92 23.625 ;
     RECT  2.16 23.895 25.92 24.165 ;
     RECT  2.16 24.435 25.92 24.705 ;
     RECT  2.16 24.975 25.92 25.245 ;
     RECT  2.16 25.515 25.92 25.785 ;
     RECT  2.16 26.055 25.92 26.325 ;
     RECT  2.16 26.595 25.92 26.865 ;
     RECT  2.16 27.135 25.92 27.405 ;
     RECT  2.16 27.675 25.92 27.945 ;
     RECT  2.16 28.215 25.92 28.485 ;
     RECT  2.16 28.755 25.92 29.025 ;
     RECT  2.16 29.295 25.92 29.565 ;
     RECT  2.16 29.835 25.92 30.105 ;
     RECT  2.16 30.375 25.92 30.645 ;
     RECT  2.16 30.915 25.92 31.185 ;
     RECT  2.16 31.455 25.92 31.725 ;
     RECT  2.16 31.995 25.92 32.265 ;
     RECT  2.16 32.535 25.92 32.805 ;
     RECT  2.16 33.075 25.92 33.345 ;
     RECT  2.16 33.615 25.92 33.885 ;
     RECT  2.16 34.155 25.92 34.425 ;
     RECT  2.16 34.695 25.92 34.965 ;
     RECT  2.16 35.235 25.92 35.505 ;
     RECT  2.16 35.775 25.92 36.045 ;
     RECT  2.16 36.315 25.92 36.585 ;
     RECT  2.16 36.855 25.92 37.125 ;
     RECT  2.16 37.395 25.92 37.665 ;
     RECT  2.16 37.935 25.92 38.205 ;
     RECT  2.16 38.475 25.92 38.745 ;
     RECT  2.16 39.015 25.92 39.285 ;
     RECT  2.16 39.555 25.92 39.825 ;
     RECT  2.16 40.095 25.92 40.365 ;
     RECT  2.16 40.635 25.92 40.905 ;
     RECT  2.16 41.175 25.92 41.445 ;
     RECT  2.16 41.715 25.92 41.985 ;
     RECT  2.16 42.255 25.92 42.525 ;
     RECT  2.16 42.795 25.92 43.065 ;
     RECT  2.16 43.335 25.92 43.605 ;
     RECT  2.16 43.875 25.92 44.145 ;
     RECT  2.16 44.415 25.92 44.685 ;
     RECT  2.16 44.955 25.92 45.225 ;
     RECT  2.16 45.495 25.92 45.765 ;
     RECT  2.16 46.035 25.92 46.305 ;
     RECT  2.16 46.575 25.92 46.845 ;
     RECT  2.16 47.115 25.92 47.385 ;
     RECT  2.16 47.655 25.92 47.925 ;
     RECT  2.16 48.195 25.92 48.465 ;
     RECT  2.16 48.735 25.92 49.005 ;
     RECT  2.16 49.275 25.92 49.545 ;
     RECT  2.16 49.815 25.92 50.085 ;
     RECT  2.16 50.355 25.92 50.625 ;
     RECT  2.16 50.895 25.92 51.165 ;
     RECT  2.16 51.435 25.92 51.705 ;
     RECT  2.16 51.975 25.92 52.245 ;
     RECT  2.16 52.515 25.92 52.785 ;
     RECT  2.16 53.055 25.92 53.325 ;
     RECT  2.16 53.595 25.92 53.865 ;
     RECT  2.16 54.135 25.92 54.405 ;
     RECT  2.16 54.675 25.92 54.945 ;
     RECT  2.16 55.215 25.92 55.485 ;
     RECT  2.16 55.755 25.92 56.025 ;
     RECT  2.16 56.295 25.92 56.565 ;
     RECT  2.16 56.835 25.92 57.105 ;
     RECT  2.16 57.375 25.92 57.645 ;
     RECT  2.16 57.915 25.92 58.185 ;
     RECT  2.16 58.455 25.92 58.725 ;
     RECT  2.16 58.995 25.92 59.265 ;
     RECT  2.16 59.535 25.92 59.805 ;
     RECT  2.16 60.075 25.92 60.345 ;
     RECT  2.16 60.615 25.92 60.885 ;
     RECT  2.16 61.155 25.92 61.425 ;
     RECT  2.16 61.695 25.92 61.965 ;
     RECT  2.16 62.235 25.92 62.505 ;
    LAYER M1 ;
     RECT  2.16 2.151 25.92 62.649 ;
    LAYER M2 ;
     RECT  0.031 6.822 0.103 6.84 ;
     RECT  0.031 8.676 0.103 8.694 ;
     RECT  0.103 6.39 0.139 6.84 ;
     RECT  0.103 10.71 0.139 10.728 ;
     RECT  0.103 22.212 0.139 22.23 ;
     RECT  0.103 28.224 0.139 28.242 ;
     RECT  0.103 30.69 0.139 30.708 ;
     RECT  0.103 31.464 0.139 31.482 ;
     RECT  0.103 32.472 0.139 33.948 ;
     RECT  0.103 34.704 0.139 35.028 ;
     RECT  0.103 55.188 0.139 55.71 ;
     RECT  0.139 6.318 0.175 6.84 ;
     RECT  0.103 7.938 0.175 8.694 ;
     RECT  0.139 10.332 0.175 10.728 ;
     RECT  0.139 22.212 0.175 22.5 ;
     RECT  0.103 29.772 0.175 29.79 ;
     RECT  0.139 30.69 0.175 31.482 ;
     RECT  0.139 32.274 0.175 35.262 ;
     RECT  0.103 46.08 0.175 46.098 ;
     RECT  0.175 20.511 0.211 20.529 ;
     RECT  0.139 28.224 0.211 28.476 ;
     RECT  0.175 29.772 0.211 29.862 ;
     RECT  0.175 30.69 0.211 35.262 ;
     RECT  0.103 51.75 0.211 51.768 ;
     RECT  0.103 25.83 0.247 25.848 ;
     RECT  0.211 28.224 0.247 28.782 ;
     RECT  0.211 29.772 0.247 35.262 ;
     RECT  0.211 51.21 0.247 51.768 ;
     RECT  0.211 20.466 0.283 20.529 ;
     RECT  0.247 51.102 0.283 51.768 ;
     RECT  0.175 10.134 0.391 10.728 ;
     RECT  0.103 41.922 0.419 41.94 ;
     RECT  0.103 12.528 0.463 13.086 ;
     RECT  0.247 25.83 0.463 26.352 ;
     RECT  0.175 6.318 0.499 8.694 ;
     RECT  0.283 20.088 0.499 20.529 ;
     RECT  0.463 24.984 0.499 25.002 ;
     RECT  0.463 25.83 0.499 26.964 ;
     RECT  0.247 28.224 0.499 35.262 ;
     RECT  0.103 38.682 0.499 38.7 ;
     RECT  0.463 12.528 0.535 13.464 ;
     RECT  0.103 14.76 0.535 14.778 ;
     RECT  0.103 18.198 0.535 18.792 ;
     RECT  0.499 19.584 0.535 20.529 ;
     RECT  0.175 21.978 0.535 22.5 ;
     RECT  0.499 24.984 0.535 26.964 ;
     RECT  0.499 27.918 0.535 35.262 ;
     RECT  0.103 36.288 0.535 36.306 ;
     RECT  0.499 37.602 0.535 37.62 ;
     RECT  0.499 38.556 0.535 38.7 ;
     RECT  0.211 48.942 0.535 48.96 ;
     RECT  0.535 37.602 1.147 38.7 ;
     RECT  0.535 42.876 1.147 42.894 ;
     RECT  0.103 43.65 1.147 43.668 ;
     RECT  0.391 10.098 1.175 10.728 ;
     RECT  1.147 42.876 1.175 43.668 ;
     RECT  0.499 6.318 2.16 9.108 ;
     RECT  1.175 10.098 2.16 10.656 ;
     RECT  0.535 11.826 2.16 13.464 ;
     RECT  0.535 14.76 2.16 15.318 ;
     RECT  0.535 16.344 2.16 16.974 ;
     RECT  0.535 18.198 2.16 20.718 ;
     RECT  0.535 21.978 2.16 22.644 ;
     RECT  0.535 24.984 2.16 35.298 ;
     RECT  0.535 36.126 2.16 36.306 ;
     RECT  1.147 37.404 2.16 38.7 ;
     RECT  1.175 42.876 2.16 43.56 ;
     RECT  0.535 44.73 2.16 44.748 ;
     RECT  0.175 46.008 2.16 46.098 ;
     RECT  0.535 48.276 2.16 48.96 ;
     RECT  0.283 50.634 2.16 51.768 ;
     RECT  0.139 55.188 2.16 56.052 ;
     RECT  2.155 56.88 2.16 56.898 ;
     RECT  1.723 57.924 2.16 57.942 ;
     RECT  2.16 2.151 25.92 62.649 ;
     RECT  25.92 4.806 26.231 60.174 ;
     RECT  26.231 4.896 26.699 60.174 ;
     RECT  26.699 4.896 26.771 58.014 ;
     RECT  26.699 58.896 26.771 60.174 ;
     RECT  26.771 59.004 27.059 60.174 ;
     RECT  26.771 6.156 27.275 58.014 ;
     RECT  26.771 4.896 27.311 5.364 ;
     RECT  27.275 6.156 27.311 42.174 ;
     RECT  27.275 42.966 27.311 58.014 ;
     RECT  27.311 6.156 27.347 11.124 ;
     RECT  27.311 12.294 27.347 24.894 ;
     RECT  27.311 25.686 27.347 27.234 ;
     RECT  27.311 28.116 27.347 37.224 ;
     RECT  27.311 38.016 27.347 41.976 ;
     RECT  27.311 42.966 27.347 54.774 ;
     RECT  27.311 4.896 27.383 4.914 ;
     RECT  27.347 12.294 27.383 15.246 ;
     RECT  27.347 16.038 27.383 18.054 ;
     RECT  27.347 21.708 27.383 24.462 ;
     RECT  27.347 25.686 27.383 27.054 ;
     RECT  27.347 28.116 27.383 30.978 ;
     RECT  27.347 31.806 27.383 35.496 ;
     RECT  27.347 40.716 27.383 41.976 ;
     RECT  27.347 45.198 27.383 47.304 ;
     RECT  27.347 48.51 27.383 48.528 ;
     RECT  27.383 12.366 27.419 15.246 ;
     RECT  27.383 23.796 27.419 24.462 ;
     RECT  27.383 30.006 27.419 30.942 ;
     RECT  27.383 32.166 27.419 35.496 ;
     RECT  27.383 40.95 27.419 41.508 ;
     RECT  27.419 32.976 27.455 35.064 ;
     RECT  27.347 6.156 27.491 10.494 ;
     RECT  27.491 8.316 27.527 10.494 ;
     RECT  27.527 8.514 27.563 8.604 ;
     RECT  27.311 55.566 27.607 58.014 ;
     RECT  27.059 59.004 27.607 59.994 ;
     RECT  27.491 6.156 27.635 7.38 ;
     RECT  27.607 55.566 27.815 59.994 ;
     RECT  27.815 55.566 27.851 56.286 ;
     RECT  27.815 57.078 27.851 59.994 ;
     RECT  27.383 28.116 27.887 29.124 ;
     RECT  27.851 57.078 27.887 59.094 ;
     RECT  27.527 9.864 27.923 10.494 ;
     RECT  27.383 17.73 27.923 18.054 ;
     RECT  27.383 25.686 27.923 26.964 ;
     RECT  27.851 55.566 27.923 55.944 ;
     RECT  27.419 12.366 27.959 15.174 ;
     RECT  27.923 17.856 27.959 18.054 ;
     RECT  27.347 20.088 27.959 20.304 ;
     RECT  27.383 21.708 27.959 22.914 ;
     RECT  27.923 25.686 27.959 26.514 ;
     RECT  27.887 28.116 27.959 28.818 ;
     RECT  27.419 30.006 27.959 30.366 ;
     RECT  27.455 32.976 27.959 34.758 ;
     RECT  27.347 36.288 27.959 37.224 ;
     RECT  27.347 38.016 27.959 38.664 ;
     RECT  27.419 41.076 27.959 41.508 ;
     RECT  27.383 46.206 27.959 47.304 ;
     RECT  27.347 49.446 27.959 50.958 ;
     RECT  27.347 52.866 27.959 52.884 ;
     RECT  27.923 55.566 27.959 55.674 ;
     RECT  27.887 57.456 27.959 59.094 ;
     RECT  27.563 8.586 27.995 8.604 ;
     RECT  27.923 9.864 27.995 9.882 ;
     RECT  27.959 12.366 27.995 13.932 ;
     RECT  27.959 15.066 27.995 15.084 ;
     RECT  27.383 16.038 27.995 16.794 ;
     RECT  27.959 18.036 27.995 18.054 ;
     RECT  27.959 20.088 27.995 20.106 ;
     RECT  27.959 21.708 27.995 22.104 ;
     RECT  27.959 22.896 27.995 22.914 ;
     RECT  27.419 24.444 27.995 24.462 ;
     RECT  27.959 25.956 27.995 25.974 ;
     RECT  27.959 28.296 27.995 28.818 ;
     RECT  27.959 30.348 27.995 30.366 ;
     RECT  27.419 32.166 27.995 32.184 ;
     RECT  27.959 32.976 27.995 32.994 ;
     RECT  27.959 34.056 27.995 34.758 ;
     RECT  27.959 37.206 27.995 37.224 ;
     RECT  27.959 38.016 27.995 38.394 ;
     RECT  27.959 41.49 27.995 41.508 ;
     RECT  27.347 42.966 27.995 43.326 ;
     RECT  27.959 46.701 27.995 47.304 ;
     RECT  27.959 49.626 27.995 49.644 ;
     RECT  27.959 50.526 27.995 50.544 ;
     RECT  27.347 51.948 27.995 51.966 ;
     RECT  27.959 55.656 27.995 55.674 ;
     RECT  27.959 57.456 27.995 57.474 ;
     RECT  27.959 58.698 27.995 59.094 ;
     RECT  27.635 6.156 28.031 6.876 ;
     RECT  27.851 59.976 28.031 59.994 ;
     RECT  27.995 34.056 28.067 34.074 ;
     RECT  27.959 36.288 28.067 36.306 ;
    LAYER M3 ;
     RECT  2.415 2.143 2.505 2.413 ;
     RECT  7.815 2.143 7.905 2.413 ;
     RECT  13.215 2.143 13.305 2.413 ;
     RECT  18.615 2.143 18.705 2.413 ;
     RECT  24.015 2.143 24.105 2.413 ;
     RECT  25.344 4.765 25.362 4.999 ;
     RECT  25.344 4.999 25.47 5.035 ;
     RECT  25.164 5.035 25.47 5.071 ;
     RECT  26.208 4.801 26.226 5.071 ;
     RECT  2.415 2.413 2.697 5.197 ;
     RECT  24.015 2.413 24.297 5.233 ;
     RECT  25.164 5.071 26.226 5.233 ;
     RECT  24.015 5.233 26.226 5.305 ;
     RECT  2.415 5.197 2.79 5.341 ;
     RECT  27.36 4.891 27.378 5.341 ;
     RECT  23.436 5.305 26.226 5.431 ;
     RECT  2.415 5.341 3.15 5.575 ;
     RECT  5.616 5.503 5.634 5.611 ;
     RECT  3.888 5.611 3.906 5.701 ;
     RECT  2.34 5.575 3.15 5.773 ;
     RECT  3.888 5.701 4.698 5.773 ;
     RECT  2.34 5.773 4.698 5.845 ;
     RECT  2.304 5.845 4.698 5.881 ;
     RECT  5.508 5.611 6.354 5.881 ;
     RECT  22.824 5.431 26.226 5.881 ;
     RECT  27.288 5.341 27.378 5.881 ;
     RECT  7.815 2.413 8.097 5.971 ;
     RECT  22.824 5.881 27.378 5.971 ;
     RECT  2.304 5.881 6.714 6.043 ;
     RECT  2.304 6.043 6.894 6.139 ;
     RECT  7.815 5.971 8.298 6.139 ;
     RECT  22.788 5.971 27.378 6.151 ;
     RECT  2.304 6.139 8.298 6.235 ;
     RECT  0.144 6.313 0.162 6.385 ;
     RECT  13.215 2.413 13.497 6.421 ;
     RECT  18.615 2.413 18.897 6.421 ;
     RECT  22.788 6.151 28.026 6.421 ;
     RECT  2.304 6.235 8.406 6.511 ;
     RECT  18.072 6.421 18.897 6.575 ;
     RECT  2.304 6.511 8.586 6.583 ;
     RECT  9.432 6.547 9.45 6.583 ;
     RECT  14.58 6.511 14.598 6.583 ;
     RECT  13.215 6.421 13.806 6.655 ;
     RECT  10.656 6.655 10.674 6.691 ;
     RECT  18.504 6.575 18.897 6.691 ;
     RECT  19.62 6.655 19.638 6.691 ;
     RECT  12.564 6.655 13.806 6.781 ;
     RECT  14.58 6.583 14.742 6.781 ;
     RECT  21.708 6.691 21.726 6.781 ;
     RECT  22.608 6.421 28.026 6.781 ;
     RECT  15.66 6.691 15.678 6.809 ;
     RECT  0.108 6.385 0.162 6.817 ;
     RECT  10.656 6.691 11.394 6.817 ;
     RECT  21.708 6.781 28.026 6.845 ;
     RECT  22.464 6.845 28.026 6.881 ;
     RECT  12.492 6.781 13.806 6.925 ;
     RECT  14.58 6.781 14.886 6.925 ;
     RECT  10.296 6.817 11.394 6.961 ;
     RECT  12.492 6.925 14.886 6.961 ;
     RECT  2.304 6.583 9.45 7.087 ;
     RECT  10.296 6.961 11.466 7.087 ;
     RECT  12.492 6.961 15.39 7.087 ;
     RECT  21.672 6.889 21.69 7.087 ;
     RECT  18.504 6.691 19.638 7.123 ;
     RECT  18.504 7.123 19.854 7.159 ;
     RECT  18.504 7.159 20.214 7.189 ;
     RECT  0.036 6.817 0.162 7.195 ;
     RECT  17.748 6.583 17.766 7.195 ;
     RECT  10.296 7.087 15.39 7.231 ;
     RECT  18.504 7.189 20.466 7.231 ;
     RECT  18.504 7.231 20.61 7.321 ;
     RECT  21.384 7.087 21.69 7.321 ;
     RECT  2.304 7.087 9.486 7.393 ;
     RECT  10.224 7.231 15.39 7.393 ;
     RECT  16.164 7.159 16.182 7.465 ;
     RECT  17.676 7.195 17.766 7.465 ;
     RECT  17.64 7.465 17.766 7.501 ;
     RECT  18.504 7.321 21.69 7.501 ;
     RECT  2.304 7.393 15.39 7.655 ;
     RECT  2.34 7.655 15.39 7.661 ;
     RECT  17.64 7.501 21.69 7.675 ;
     RECT  22.464 6.881 27.954 7.757 ;
     RECT  0.036 7.195 0.27 7.771 ;
     RECT  16.164 7.465 16.542 7.771 ;
     RECT  17.604 7.675 21.69 7.771 ;
     RECT  22.464 7.757 26.298 7.771 ;
     RECT  16.164 7.771 16.686 7.861 ;
     RECT  16.128 7.861 16.686 8.041 ;
     RECT  17.604 7.771 26.298 8.041 ;
     RECT  2.376 7.661 15.39 8.131 ;
     RECT  16.128 8.041 16.722 8.131 ;
     RECT  27.36 7.757 27.954 8.203 ;
     RECT  2.376 8.131 16.722 8.231 ;
     RECT  17.532 8.041 26.298 8.311 ;
     RECT  13.068 8.231 16.722 8.429 ;
     RECT  2.376 8.231 12.294 8.581 ;
     RECT  0.036 7.771 0.558 8.699 ;
     RECT  2.34 8.581 12.294 8.779 ;
     RECT  17.496 8.311 26.298 8.851 ;
     RECT  13.104 8.429 16.722 8.941 ;
     RECT  17.46 8.851 26.298 8.941 ;
     RECT  27.36 8.203 27.99 8.971 ;
     RECT  13.104 8.941 26.298 9.005 ;
     RECT  2.304 8.779 12.294 9.067 ;
     RECT  0.108 8.699 0.558 9.101 ;
     RECT  2.304 9.067 12.33 9.211 ;
     RECT  13.104 9.005 14.562 9.211 ;
     RECT  15.444 9.005 26.298 9.547 ;
     RECT  27.324 8.971 27.99 9.547 ;
     RECT  2.304 9.211 14.562 9.643 ;
     RECT  15.444 9.547 27.99 9.739 ;
     RECT  0.108 9.101 0.522 9.773 ;
     RECT  2.268 9.643 14.562 9.823 ;
     RECT  15.372 9.739 27.99 9.823 ;
     RECT  2.268 9.823 27.99 9.887 ;
     RECT  2.268 9.887 27.918 10.085 ;
     RECT  0.144 9.773 0.522 10.165 ;
     RECT  0.144 10.165 0.558 10.633 ;
     RECT  2.304 10.085 27.918 10.637 ;
     RECT  0.144 10.633 1.17 10.705 ;
     RECT  0.108 10.705 1.17 10.733 ;
     RECT  0.108 10.733 0.486 10.829 ;
     RECT  0.108 10.829 0.414 10.925 ;
     RECT  0.108 10.925 0.162 11.021 ;
     RECT  27.252 10.637 27.918 11.213 ;
     RECT  0.144 11.021 0.162 11.309 ;
     RECT  2.304 10.637 26.298 11.365 ;
     RECT  27.252 11.213 27.342 11.365 ;
     RECT  2.304 11.365 27.342 11.371 ;
     RECT  2.268 11.371 27.342 11.405 ;
     RECT  27.252 11.405 27.342 11.947 ;
     RECT  27.252 11.947 27.954 12.139 ;
     RECT  27.252 12.139 27.99 12.235 ;
     RECT  2.268 11.405 26.118 12.245 ;
     RECT  2.34 12.245 26.118 12.427 ;
     RECT  27.216 12.235 27.99 12.427 ;
     RECT  0.54 11.821 0.558 12.523 ;
     RECT  2.34 12.427 27.99 13.003 ;
     RECT  0.108 12.523 0.558 13.517 ;
     RECT  2.304 13.003 27.99 13.531 ;
     RECT  2.268 13.531 27.99 13.559 ;
     RECT  0.18 13.517 0.558 13.565 ;
     RECT  2.268 13.559 15.714 13.631 ;
     RECT  0.468 13.565 0.558 13.709 ;
     RECT  0.468 13.709 0.486 13.805 ;
     RECT  2.268 13.631 15.606 13.805 ;
     RECT  16.488 13.559 27.99 14.243 ;
     RECT  2.268 13.805 15.498 14.299 ;
     RECT  2.232 14.299 15.498 14.405 ;
     RECT  16.488 14.243 17.262 14.521 ;
     RECT  2.268 14.405 15.498 14.675 ;
     RECT  2.304 14.675 15.498 14.755 ;
     RECT  16.416 14.521 17.262 14.755 ;
     RECT  18.144 14.243 27.99 14.765 ;
     RECT  0.108 14.755 0.126 14.957 ;
     RECT  2.304 14.755 17.262 14.971 ;
     RECT  18.144 14.765 26.334 14.971 ;
     RECT  27.288 14.765 27.99 15.089 ;
     RECT  27.288 15.089 27.954 15.179 ;
     RECT  2.304 14.971 26.334 15.685 ;
     RECT  27.288 15.179 27.414 15.685 ;
     RECT  2.304 15.685 27.414 15.719 ;
     RECT  0.144 15.295 0.558 15.773 ;
     RECT  26.244 15.719 27.414 15.979 ;
     RECT  2.304 15.719 25.398 16.501 ;
     RECT  26.244 15.979 27.99 16.501 ;
     RECT  2.304 16.501 27.99 16.88 ;
     RECT  2.304 16.88 25.722 17.323 ;
     RECT  0.54 15.773 0.558 17.837 ;
     RECT  2.268 17.323 25.722 17.923 ;
     RECT  26.676 16.88 27.99 17.923 ;
     RECT  2.268 17.923 27.99 18.059 ;
     RECT  2.268 18.059 27.378 18.257 ;
     RECT  2.304 18.257 27.378 18.509 ;
     RECT  0.108 18.193 0.126 18.859 ;
     RECT  2.304 18.509 27.342 18.989 ;
     RECT  26.676 18.989 27.342 19.139 ;
     RECT  0.108 18.859 0.162 19.277 ;
     RECT  0.144 19.277 0.162 19.345 ;
     RECT  0.144 19.345 0.558 19.757 ;
     RECT  2.304 18.989 25.794 19.912 ;
     RECT  27.288 19.139 27.342 19.915 ;
     RECT  2.232 19.912 25.794 19.949 ;
     RECT  2.304 19.949 25.794 20.011 ;
     RECT  27.288 19.915 27.99 20.111 ;
     RECT  27.288 20.111 27.954 20.309 ;
     RECT  0.144 19.757 0.522 20.525 ;
     RECT  27.288 20.309 27.414 20.621 ;
     RECT  0.18 20.525 0.522 20.695 ;
     RECT  2.304 20.011 26.262 20.731 ;
     RECT  27.288 20.621 27.342 20.731 ;
     RECT  2.304 20.731 27.342 20.875 ;
     RECT  0.18 20.695 0.558 21.197 ;
     RECT  0.18 21.197 0.522 21.259 ;
     RECT  2.268 20.875 27.342 21.425 ;
     RECT  2.304 21.425 27.342 21.643 ;
     RECT  0.144 21.259 0.522 22.045 ;
     RECT  2.304 21.643 27.99 22.199 ;
     RECT  0.144 22.045 0.558 22.207 ;
     RECT  2.304 22.199 26.334 22.541 ;
     RECT  0.108 22.207 0.558 22.829 ;
     RECT  27.288 22.199 27.99 22.919 ;
     RECT  0.108 22.829 0.162 22.925 ;
     RECT  0.144 22.925 0.162 23.021 ;
     RECT  2.304 22.541 26.262 23.275 ;
     RECT  27.288 22.919 27.918 23.275 ;
     RECT  2.304 23.275 27.918 23.287 ;
     RECT  2.232 23.287 27.918 24.139 ;
     RECT  2.232 24.139 27.99 24.269 ;
     RECT  0.18 24.187 0.198 24.331 ;
     RECT  0.18 24.331 0.342 24.523 ;
     RECT  26.748 24.269 27.99 24.629 ;
     RECT  0.144 24.523 0.342 24.701 ;
     RECT  2.232 24.269 25.722 25.003 ;
     RECT  0.468 24.979 0.486 25.015 ;
     RECT  0.468 25.015 0.558 25.051 ;
     RECT  2.232 25.003 26.298 25.477 ;
     RECT  27.288 24.629 27.99 25.477 ;
     RECT  2.232 25.477 27.99 25.757 ;
     RECT  0.468 25.051 1.17 25.825 ;
     RECT  2.304 25.757 27.99 25.979 ;
     RECT  2.304 25.979 27.954 26.159 ;
     RECT  2.304 26.159 25.686 26.519 ;
     RECT  26.784 26.159 27.954 26.519 ;
     RECT  0.108 25.825 1.17 26.957 ;
     RECT  2.304 26.519 25.65 27.095 ;
     RECT  26.784 26.519 27.918 27.341 ;
     RECT  2.304 27.095 25.506 27.403 ;
     RECT  0.108 26.957 0.558 27.437 ;
     RECT  27.252 27.341 27.918 27.499 ;
     RECT  2.268 27.403 25.506 27.913 ;
     RECT  2.232 27.913 25.506 27.931 ;
     RECT  26.244 27.787 26.262 27.931 ;
     RECT  2.232 27.931 26.262 28.013 ;
     RECT  0.468 27.437 0.558 28.219 ;
     RECT  2.268 28.013 26.262 28.219 ;
     RECT  27.252 27.499 27.99 28.219 ;
     RECT  0.108 28.219 0.558 28.781 ;
     RECT  2.268 28.219 27.99 29.399 ;
     RECT  2.268 29.399 26.298 29.561 ;
     RECT  2.268 29.561 25.722 29.759 ;
     RECT  0.144 28.781 0.558 29.767 ;
     RECT  27.252 29.399 27.99 30.187 ;
     RECT  0.108 29.767 0.558 30.221 ;
     RECT  2.34 29.759 25.722 30.283 ;
     RECT  0.108 30.221 0.522 30.317 ;
     RECT  27.18 30.187 27.99 30.371 ;
     RECT  2.34 30.283 26.262 30.379 ;
     RECT  27.18 30.371 27.846 30.379 ;
     RECT  2.34 30.379 27.846 30.749 ;
     RECT  26.676 30.749 27.846 30.941 ;
     RECT  2.34 30.749 25.722 30.955 ;
     RECT  0.108 30.317 0.378 31.189 ;
     RECT  0.108 31.189 0.558 31.373 ;
     RECT  26.676 30.941 27.81 31.723 ;
     RECT  2.304 30.955 25.722 31.955 ;
     RECT  2.376 31.955 25.722 32.059 ;
     RECT  26.676 31.723 27.99 32.059 ;
     RECT  0.108 31.373 0.522 32.341 ;
     RECT  2.376 32.059 27.99 32.717 ;
     RECT  2.376 32.717 25.578 32.737 ;
     RECT  2.232 32.737 25.578 32.909 ;
     RECT  26.712 32.717 27.99 32.999 ;
     RECT  0.108 32.341 0.558 33.389 ;
     RECT  2.304 32.909 25.578 33.739 ;
     RECT  2.304 33.739 25.686 33.781 ;
     RECT  0.108 33.389 0.522 33.869 ;
     RECT  2.304 33.781 25.722 33.881 ;
     RECT  26.712 32.999 27.954 34.027 ;
     RECT  26.712 34.027 27.99 34.051 ;
     RECT  0.108 33.869 0.486 34.061 ;
     RECT  26.712 34.051 28.062 34.079 ;
     RECT  2.304 33.881 25.686 34.393 ;
     RECT  2.268 34.393 25.686 34.541 ;
     RECT  2.304 34.541 25.686 34.655 ;
     RECT  2.415 34.655 25.686 34.735 ;
     RECT  0.108 34.061 0.27 34.924 ;
     RECT  0.108 34.924 0.306 35.275 ;
     RECT  0.108 35.275 0.558 35.405 ;
     RECT  26.748 34.079 28.062 35.419 ;
     RECT  2.415 34.735 25.794 35.437 ;
     RECT  2.304 35.437 25.794 35.659 ;
     RECT  26.676 35.419 28.062 35.659 ;
     RECT  0.144 35.405 0.558 36.283 ;
     RECT  2.304 35.659 28.062 36.311 ;
     RECT  0.108 36.283 0.558 36.749 ;
     RECT  2.304 36.311 27.99 37.121 ;
     RECT  0.54 36.749 0.558 37.399 ;
     RECT  0.54 37.399 1.17 37.597 ;
     RECT  0.504 37.597 1.17 37.625 ;
     RECT  2.304 37.121 25.794 37.771 ;
     RECT  0.504 37.625 0.558 38.059 ;
     RECT  2.268 37.771 25.794 38.093 ;
     RECT  26.676 37.121 27.99 38.399 ;
     RECT  2.268 38.093 25.722 38.407 ;
     RECT  26.676 38.399 27.954 38.471 ;
     RECT  2.196 38.407 25.722 38.477 ;
     RECT  27.324 38.471 27.954 38.669 ;
     RECT  0.324 38.059 0.558 38.677 ;
     RECT  0.108 38.677 0.558 38.765 ;
     RECT  0.108 38.765 0.522 38.861 ;
     RECT  0.108 38.861 0.126 38.957 ;
     RECT  27.324 38.669 27.342 39.211 ;
     RECT  2.304 38.477 25.722 39.361 ;
     RECT  26.748 39.211 27.342 39.559 ;
     RECT  2.268 39.361 25.722 39.787 ;
     RECT  26.712 39.559 27.342 39.787 ;
     RECT  2.268 39.787 27.342 40.127 ;
     RECT  0.216 39.979 0.234 40.157 ;
     RECT  0.144 40.171 0.162 40.349 ;
     RECT  2.304 40.127 27.342 40.555 ;
     RECT  2.304 40.555 27.378 40.631 ;
     RECT  26.748 40.631 27.378 40.651 ;
     RECT  2.304 40.631 25.722 41.035 ;
     RECT  26.748 40.651 27.954 41.419 ;
     RECT  26.748 41.419 27.99 41.513 ;
     RECT  2.268 41.035 25.722 41.515 ;
     RECT  26.748 41.513 27.378 41.515 ;
     RECT  2.268 41.515 27.378 41.611 ;
     RECT  2.232 41.611 27.378 41.645 ;
     RECT  2.232 41.645 25.65 41.747 ;
     RECT  0.324 41.803 0.342 41.899 ;
     RECT  0.108 41.899 0.342 41.917 ;
     RECT  0.108 41.917 0.414 41.945 ;
     RECT  2.268 41.747 25.65 41.945 ;
     RECT  26.712 41.645 27.378 41.981 ;
     RECT  0.18 41.945 0.414 42.029 ;
     RECT  0.18 42.029 0.27 42.125 ;
     RECT  0.252 42.125 0.27 42.173 ;
     RECT  26.712 41.981 27.342 42.475 ;
     RECT  2.304 41.945 25.65 42.565 ;
     RECT  2.304 42.565 25.722 42.667 ;
     RECT  2.232 42.667 25.722 42.719 ;
     RECT  26.676 42.475 27.342 42.859 ;
     RECT  0.54 42.871 0.558 43.099 ;
     RECT  26.676 42.859 27.99 43.243 ;
     RECT  0.144 43.099 0.558 43.373 ;
     RECT  2.232 42.719 25.578 43.403 ;
     RECT  26.64 43.243 27.99 43.565 ;
     RECT  0.144 43.373 0.162 43.645 ;
     RECT  1.152 43.537 1.17 43.673 ;
     RECT  2.304 43.403 25.578 43.979 ;
     RECT  0.108 43.645 0.162 44.045 ;
     RECT  0.144 44.045 0.162 44.189 ;
     RECT  2.304 43.979 25.506 44.203 ;
     RECT  26.64 43.565 27.342 44.395 ;
     RECT  2.232 44.203 25.506 44.645 ;
     RECT  2.304 44.645 25.506 44.851 ;
     RECT  26.28 44.395 27.342 44.851 ;
     RECT  2.304 44.851 27.342 44.915 ;
     RECT  9.72 44.915 27.342 45.149 ;
     RECT  13.032 45.149 27.342 45.193 ;
     RECT  0.54 44.725 0.558 45.773 ;
     RECT  2.304 44.915 8.91 45.931 ;
     RECT  9.72 45.149 12.294 45.995 ;
     RECT  13.032 45.193 27.378 46.027 ;
     RECT  0.18 46.003 0.198 46.075 ;
     RECT  13.032 46.027 27.81 46.075 ;
     RECT  2.268 45.931 8.91 46.111 ;
     RECT  9.72 45.995 10.098 46.111 ;
     RECT  13.032 46.075 27.882 46.123 ;
     RECT  10.872 45.995 12.294 46.171 ;
     RECT  13.032 46.123 27.954 46.171 ;
     RECT  0.108 46.075 0.198 46.541 ;
     RECT  0.18 46.541 0.198 46.637 ;
     RECT  10.872 46.171 27.954 46.696 ;
     RECT  2.268 46.111 10.098 46.813 ;
     RECT  10.872 46.696 27.99 46.813 ;
     RECT  1.26 46.987 1.278 47.083 ;
     RECT  1.152 47.083 1.278 47.117 ;
     RECT  1.152 47.117 1.17 47.261 ;
     RECT  2.268 46.813 27.99 47.309 ;
     RECT  2.268 47.309 27.918 47.452 ;
     RECT  2.232 47.452 27.918 47.687 ;
     RECT  0.144 47.899 0.162 48.043 ;
     RECT  2.268 47.687 27.918 48.173 ;
     RECT  27.324 48.173 27.918 48.235 ;
     RECT  0.144 48.043 0.342 48.271 ;
     RECT  2.268 48.173 26.262 48.427 ;
     RECT  2.232 48.427 26.262 48.569 ;
     RECT  0.144 48.271 0.558 48.653 ;
     RECT  2.268 48.569 26.262 48.839 ;
     RECT  27.324 48.235 27.99 48.901 ;
     RECT  0.144 48.653 0.234 48.989 ;
     RECT  9.144 48.839 25.578 49.001 ;
     RECT  0.216 48.989 0.234 49.037 ;
     RECT  2.268 48.839 8.406 49.505 ;
     RECT  2.304 49.505 8.406 49.585 ;
     RECT  9.144 49.001 25.506 49.585 ;
     RECT  0.324 49.675 0.342 49.771 ;
     RECT  26.748 48.901 27.99 49.771 ;
     RECT  26.712 49.771 27.99 49.811 ;
     RECT  2.304 49.585 25.506 49.855 ;
     RECT  2.304 49.855 25.578 49.891 ;
     RECT  26.748 49.811 27.99 49.919 ;
     RECT  0.18 49.771 0.342 50.141 ;
     RECT  0.216 50.141 0.342 50.381 ;
     RECT  26.784 49.919 27.99 51.019 ;
     RECT  0.216 50.381 0.306 51.053 ;
     RECT  0.216 51.053 0.27 51.499 ;
     RECT  2.304 49.891 25.722 51.499 ;
     RECT  26.748 51.019 27.99 51.499 ;
     RECT  0.144 51.499 0.27 51.725 ;
     RECT  2.304 51.499 27.99 51.809 ;
     RECT  2.304 51.809 25.722 51.883 ;
     RECT  0.108 51.745 0.126 52.013 ;
     RECT  2.268 51.883 25.722 52.015 ;
     RECT  2.232 52.015 25.722 52.397 ;
     RECT  26.676 51.809 27.99 52.511 ;
     RECT  0.144 52.795 0.162 52.973 ;
     RECT  2.268 52.397 25.722 52.987 ;
     RECT  2.268 52.987 25.794 53.015 ;
     RECT  10.008 53.015 25.794 53.087 ;
     RECT  10.008 53.087 25.722 53.285 ;
     RECT  26.712 52.511 27.99 53.419 ;
     RECT  0.324 53.419 0.342 53.549 ;
     RECT  2.304 53.015 9.198 53.797 ;
     RECT  2.268 53.797 9.198 53.869 ;
     RECT  10.008 53.285 10.422 53.869 ;
     RECT  11.16 53.285 25.722 53.899 ;
     RECT  2.268 53.869 10.422 54.067 ;
     RECT  11.16 53.899 25.758 54.067 ;
     RECT  2.268 54.067 25.758 54.523 ;
     RECT  2.196 54.523 25.758 54.571 ;
     RECT  26.496 53.419 27.99 54.571 ;
     RECT  2.196 54.571 27.99 54.763 ;
     RECT  0.144 54.523 0.162 55.183 ;
     RECT  0.108 55.183 0.162 55.339 ;
     RECT  0.108 55.339 0.342 55.469 ;
     RECT  0.108 55.469 0.162 56.045 ;
     RECT  2.16 54.763 27.99 56.219 ;
     RECT  0.144 56.045 0.162 56.525 ;
     RECT  2.16 56.219 12.33 56.971 ;
     RECT  0.324 56.683 0.342 57.163 ;
     RECT  1.728 56.971 12.33 57.307 ;
     RECT  13.068 56.219 27.99 57.307 ;
     RECT  0.324 57.163 0.45 57.355 ;
     RECT  0.252 57.355 0.45 57.437 ;
     RECT  0.252 57.437 0.27 57.533 ;
     RECT  1.728 57.307 27.99 57.547 ;
     RECT  1.728 57.547 28.026 57.569 ;
     RECT  13.068 57.569 28.026 57.713 ;
     RECT  1.728 57.569 12.33 57.947 ;
     RECT  0.108 57.643 0.126 57.965 ;
     RECT  2.232 57.947 12.33 57.983 ;
     RECT  2.268 57.983 12.33 58.019 ;
     RECT  13.215 57.713 28.026 58.019 ;
     RECT  2.268 58.019 12.294 58.109 ;
     RECT  12.24 58.109 12.294 58.145 ;
     RECT  14.508 58.019 28.026 58.145 ;
     RECT  15.084 58.145 28.026 58.157 ;
     RECT  2.268 58.109 10.566 58.217 ;
     RECT  12.276 58.145 12.294 58.253 ;
     RECT  16.596 58.157 28.026 58.289 ;
     RECT  2.304 58.217 10.566 58.379 ;
     RECT  13.215 58.019 13.698 58.379 ;
     RECT  15.084 58.157 15.57 58.379 ;
     RECT  16.848 58.289 28.026 58.379 ;
     RECT  15.084 58.379 15.138 58.415 ;
     RECT  18.252 58.379 25.794 58.415 ;
     RECT  19.836 58.415 25.794 58.559 ;
     RECT  9.108 58.379 10.566 58.649 ;
     RECT  11.376 58.109 11.394 58.649 ;
     RECT  15.084 58.415 15.102 58.649 ;
     RECT  19.836 58.559 19.854 58.685 ;
     RECT  2.304 58.379 8.097 58.691 ;
     RECT  22.428 58.559 25.794 58.721 ;
     RECT  26.604 58.379 28.026 58.721 ;
     RECT  10.548 58.649 10.566 58.829 ;
     RECT  22.428 58.721 25.758 58.829 ;
     RECT  9.108 58.649 9.126 58.919 ;
     RECT  20.808 58.559 21.654 58.919 ;
     RECT  2.304 58.691 6.75 58.955 ;
     RECT  22.428 58.829 25.722 59.069 ;
     RECT  2.304 58.955 5.346 59.099 ;
     RECT  6.3 58.955 6.75 59.099 ;
     RECT  2.304 59.099 5.094 59.189 ;
     RECT  6.588 59.099 6.75 59.189 ;
     RECT  7.524 58.691 8.097 59.189 ;
     RECT  26.676 58.721 28.026 59.189 ;
     RECT  2.304 59.189 4.986 59.225 ;
     RECT  16.848 58.379 17.514 59.369 ;
     RECT  2.304 59.225 3.834 59.459 ;
     RECT  4.608 59.225 4.626 59.459 ;
     RECT  21.636 58.919 21.654 59.459 ;
     RECT  22.608 59.069 25.722 59.459 ;
     RECT  27.036 59.189 28.026 59.459 ;
     RECT  23.94 59.459 25.722 59.495 ;
     RECT  2.304 59.459 2.826 59.567 ;
     RECT  27.828 59.459 28.026 59.639 ;
     RECT  23.94 59.495 25.686 59.729 ;
     RECT  2.304 59.567 2.697 59.765 ;
     RECT  17.496 59.369 17.514 59.837 ;
     RECT  20.808 58.919 20.826 59.909 ;
     RECT  22.824 59.459 23.166 59.999 ;
     RECT  28.008 59.639 28.026 59.999 ;
     RECT  23.94 59.729 25.578 60.035 ;
     RECT  23.148 59.999 23.166 60.071 ;
     RECT  23.976 60.035 25.578 60.071 ;
     RECT  25.56 60.071 25.578 60.107 ;
     RECT  23.976 60.071 24.297 60.179 ;
     RECT  27.036 59.459 27.054 60.179 ;
     RECT  2.415 59.765 2.697 62.387 ;
     RECT  7.815 59.189 8.097 62.387 ;
     RECT  13.215 58.379 13.497 62.387 ;
     RECT  18.615 58.415 18.897 62.387 ;
     RECT  24.015 60.179 24.297 62.387 ;
     RECT  2.415 62.387 2.505 62.657 ;
     RECT  7.815 62.387 7.905 62.657 ;
     RECT  13.215 62.387 13.305 62.657 ;
     RECT  18.615 62.387 18.705 62.657 ;
     RECT  24.015 62.387 24.105 62.657 ;
    LAYER M4 ;
     RECT  0.06 7.248 0.097 57.864 ;
     RECT  0.097 7.248 2.408 57.96 ;
     RECT  2.293 59.28 2.408 59.304 ;
     RECT  2.408 2.148 2.512 62.652 ;
     RECT  2.512 2.418 2.704 62.382 ;
     RECT  2.704 6.24 2.765 59.304 ;
     RECT  2.765 6.24 2.867 58.68 ;
     RECT  2.867 6.24 2.873 58.248 ;
     RECT  2.873 56.976 2.981 58.248 ;
     RECT  2.981 57.072 3.017 58.248 ;
     RECT  2.341 0.096 3.155 0.12 ;
     RECT  3.017 57.072 3.161 57.096 ;
     RECT  2.873 6.24 3.443 55.896 ;
     RECT  3.443 6.24 3.781 55.848 ;
     RECT  3.017 58.08 4.021 58.248 ;
     RECT  4.021 57.552 4.129 58.248 ;
     RECT  3.781 5.712 4.501 55.848 ;
     RECT  4.129 57.024 4.501 58.248 ;
     RECT  4.501 5.712 4.547 58.248 ;
     RECT  3.805 59.28 4.691 59.304 ;
     RECT  4.547 5.712 4.709 56.328 ;
     RECT  4.547 57.552 4.745 58.248 ;
     RECT  4.745 58.08 4.781 58.248 ;
     RECT  4.781 58.128 4.837 58.248 ;
     RECT  4.709 5.904 5.501 56.328 ;
     RECT  5.501 6.048 5.753 56.328 ;
     RECT  5.753 46.08 6.325 56.328 ;
     RECT  5.753 6.048 6.329 45.096 ;
     RECT  4.837 58.128 6.397 58.776 ;
     RECT  6.397 57.84 6.649 58.776 ;
     RECT  6.649 57.744 6.761 58.776 ;
     RECT  6.325 46.08 6.829 56.424 ;
     RECT  6.761 57.744 6.829 58.728 ;
     RECT  6.329 6.048 7.381 19.656 ;
     RECT  6.329 20.64 7.381 45.096 ;
     RECT  6.829 46.08 7.381 58.728 ;
     RECT  7.381 6.048 7.808 58.728 ;
     RECT  7.808 2.148 7.912 62.652 ;
     RECT  7.912 2.418 8.104 62.382 ;
     RECT  8.104 7.392 8.129 58.152 ;
     RECT  8.104 6.24 8.435 6.264 ;
     RECT  8.129 58.128 8.633 58.152 ;
     RECT  8.129 7.392 8.957 56.904 ;
     RECT  8.957 7.392 9.209 52.92 ;
     RECT  9.209 7.392 9.353 47.352 ;
     RECT  9.353 7.968 9.395 47.304 ;
     RECT  9.395 14.976 9.577 47.304 ;
     RECT  8.957 54.096 9.733 56.904 ;
     RECT  9.692 58.608 9.779 58.632 ;
     RECT  9.209 48.624 9.827 52.92 ;
     RECT  9.733 54.096 10.109 57.576 ;
     RECT  9.577 14.976 10.397 42.696 ;
     RECT  10.397 20.4 10.721 42.696 ;
     RECT  9.395 7.968 10.757 13.992 ;
     RECT  10.721 20.4 10.835 33.048 ;
     RECT  10.721 34.176 10.835 42.696 ;
     RECT  9.827 48.672 10.901 52.92 ;
     RECT  10.835 36.288 10.937 42.696 ;
     RECT  10.901 50.832 10.969 52.92 ;
     RECT  10.757 9.552 11.005 13.992 ;
     RECT  10.397 14.976 11.005 19.416 ;
     RECT  10.109 54.096 11.045 57.432 ;
     RECT  9.577 43.872 11.293 47.304 ;
     RECT  11.045 54.096 11.405 56.088 ;
     RECT  11.005 9.552 11.437 19.416 ;
     RECT  10.835 20.4 11.437 27.384 ;
     RECT  10.835 28.416 11.833 33.048 ;
     RECT  10.835 34.176 11.833 35.208 ;
     RECT  10.757 8.016 11.869 8.568 ;
     RECT  11.437 9.552 11.869 27.384 ;
     RECT  11.833 28.416 11.869 35.208 ;
     RECT  10.901 48.672 11.905 49.608 ;
     RECT  11.869 8.016 11.945 35.208 ;
     RECT  11.945 15.984 12.013 35.208 ;
     RECT  10.937 36.288 12.013 42.216 ;
     RECT  11.905 48.528 12.037 49.608 ;
     RECT  12.037 48.528 12.049 49.704 ;
     RECT  10.969 50.832 12.049 52.968 ;
     RECT  12.049 48.528 12.085 52.968 ;
     RECT  12.085 48.528 12.124 53.064 ;
     RECT  12.124 50.112 12.133 53.064 ;
     RECT  11.293 43.344 12.229 47.304 ;
     RECT  11.945 8.016 12.233 15 ;
     RECT  11.045 57.408 12.301 57.432 ;
     RECT  12.124 48.528 12.445 49.128 ;
     RECT  12.229 43.296 12.517 47.304 ;
     RECT  12.445 48.384 12.517 49.128 ;
     RECT  12.233 8.016 12.625 13.896 ;
     RECT  12.133 50.88 12.841 53.064 ;
     RECT  11.405 54.096 12.841 55.848 ;
     RECT  12.625 7.44 12.877 13.896 ;
     RECT  12.841 50.88 13.093 55.848 ;
     RECT  12.301 57.024 13.093 57.432 ;
     RECT  12.013 15.984 13.165 42.216 ;
     RECT  12.517 43.296 13.165 49.128 ;
     RECT  12.877 6.864 13.208 13.896 ;
     RECT  12.233 14.88 13.208 15 ;
     RECT  13.165 15.984 13.208 49.128 ;
     RECT  13.093 50.88 13.208 57.432 ;
     RECT  13.208 2.148 13.312 62.652 ;
     RECT  13.312 2.418 13.504 62.382 ;
     RECT  13.504 7.344 13.601 9.144 ;
     RECT  13.504 41.472 13.619 49.56 ;
     RECT  13.619 41.472 13.637 42.072 ;
     RECT  13.637 41.904 13.709 42.072 ;
     RECT  13.619 43.344 13.889 49.56 ;
     RECT  13.504 17.52 14.497 40.2 ;
     RECT  13.601 7.392 14.569 9.144 ;
     RECT  14.569 6.528 14.573 9.144 ;
     RECT  13.504 54.432 14.605 55.512 ;
     RECT  13.504 56.496 14.605 58.008 ;
     RECT  14.497 17.52 14.641 40.248 ;
     RECT  13.709 42.048 14.677 42.072 ;
     RECT  13.504 50.832 14.821 53.064 ;
     RECT  14.573 6.528 14.897 8.568 ;
     RECT  13.889 43.968 14.897 49.56 ;
     RECT  14.605 54.432 14.969 58.008 ;
     RECT  14.641 17.376 15.061 40.248 ;
     RECT  14.677 41.232 15.061 42.072 ;
     RECT  14.821 50.832 15.221 53.352 ;
     RECT  14.897 45.792 15.257 49.56 ;
     RECT  13.504 10.272 15.361 16.248 ;
     RECT  15.061 17.376 15.493 42.072 ;
     RECT  14.897 43.968 15.505 44.76 ;
     RECT  15.361 9.744 15.649 16.248 ;
     RECT  15.649 9.744 15.653 16.392 ;
     RECT  15.493 17.376 15.685 42.216 ;
     RECT  15.685 17.376 15.721 42.792 ;
     RECT  15.505 43.92 15.721 44.76 ;
     RECT  15.721 17.376 15.779 44.76 ;
     RECT  15.779 17.376 15.841 42.216 ;
     RECT  15.779 43.248 15.865 44.76 ;
     RECT  15.257 45.792 15.865 48.936 ;
     RECT  15.221 51.12 16.117 53.352 ;
     RECT  14.969 54.432 16.117 55.512 ;
     RECT  14.969 56.496 16.117 58.008 ;
     RECT  14.897 8.208 16.225 8.568 ;
     RECT  16.225 8.016 16.405 8.568 ;
     RECT  14.897 6.528 16.441 6.552 ;
     RECT  16.405 7.728 16.441 8.568 ;
     RECT  15.865 43.248 16.501 48.936 ;
     RECT  16.441 6.528 16.549 8.568 ;
     RECT  16.549 6.528 16.553 9.432 ;
     RECT  16.117 51.12 16.585 55.512 ;
     RECT  16.553 9.072 16.636 9.432 ;
     RECT  15.653 10.464 16.765 16.392 ;
     RECT  15.841 17.376 16.765 42.168 ;
     RECT  16.765 10.464 16.945 42.168 ;
     RECT  16.501 43.248 16.945 49.464 ;
     RECT  16.585 50.976 16.945 55.512 ;
     RECT  16.117 56.496 16.945 58.152 ;
     RECT  16.945 10.464 17.017 49.464 ;
     RECT  17.017 10.32 17.053 49.464 ;
     RECT  16.945 50.976 17.053 58.152 ;
     RECT  17.053 10.32 17.057 58.152 ;
     RECT  17.057 14.784 17.381 58.152 ;
     RECT  17.381 54.096 17.596 58.152 ;
     RECT  17.596 56.544 17.633 58.152 ;
     RECT  16.636 9.072 18.061 9.096 ;
     RECT  17.057 10.32 18.061 13.656 ;
     RECT  18.061 9.072 18.133 13.656 ;
     RECT  17.381 14.784 18.133 53.016 ;
     RECT  16.553 6.528 18.608 8.04 ;
     RECT  18.133 9.072 18.608 53.016 ;
     RECT  17.596 54.096 18.608 55.512 ;
     RECT  17.633 56.544 18.608 57.96 ;
     RECT  18.608 2.148 18.712 62.652 ;
     RECT  18.712 2.418 18.904 62.382 ;
     RECT  18.904 56.544 20.185 58.152 ;
     RECT  18.904 6.768 20.579 55.416 ;
     RECT  20.579 9.072 20.621 55.416 ;
     RECT  20.621 9.36 21.049 55.416 ;
     RECT  20.185 56.544 21.049 58.536 ;
     RECT  21.049 9.36 21.341 58.536 ;
     RECT  21.341 56.592 21.625 58.536 ;
     RECT  20.579 6.768 21.665 7.752 ;
     RECT  21.625 56.592 21.683 59.064 ;
     RECT  21.769 7.92 21.913 8.136 ;
     RECT  21.913 7.92 22.129 8.232 ;
     RECT  21.341 9.36 22.129 55.512 ;
     RECT  22.129 7.92 22.529 55.512 ;
     RECT  21.683 59.04 22.705 59.064 ;
     RECT  22.529 7.92 22.709 44.904 ;
     RECT  22.709 7.92 22.741 19.848 ;
     RECT  21.683 56.592 22.813 57.576 ;
     RECT  22.705 58.704 22.813 59.064 ;
     RECT  22.529 46.08 22.957 55.512 ;
     RECT  22.813 56.592 22.957 59.064 ;
     RECT  22.957 46.08 23.137 59.064 ;
     RECT  21.665 6.768 23.281 6.84 ;
     RECT  22.741 7.824 23.281 19.848 ;
     RECT  22.709 21.12 23.497 44.904 ;
     RECT  23.137 46.08 23.533 59.88 ;
     RECT  23.281 6.768 23.713 19.848 ;
     RECT  23.497 21.12 23.785 44.952 ;
     RECT  23.533 45.984 23.785 59.88 ;
     RECT  23.713 6.768 23.797 20.088 ;
     RECT  23.797 6.24 24.008 20.088 ;
     RECT  23.785 21.12 24.008 59.88 ;
     RECT  24.008 2.148 24.112 62.652 ;
     RECT  24.112 2.418 24.304 62.382 ;
     RECT  24.304 6.672 24.977 59.16 ;
     RECT  24.977 6.672 25.049 48.504 ;
     RECT  25.049 20.16 25.085 48.504 ;
     RECT  25.085 20.16 25.121 48.456 ;
     RECT  25.049 6.672 25.193 18.936 ;
     RECT  24.977 49.536 25.229 59.16 ;
     RECT  25.121 20.16 25.265 38.28 ;
     RECT  25.229 49.68 25.265 59.16 ;
     RECT  25.265 58.128 25.297 59.16 ;
     RECT  25.121 39.312 25.301 48.456 ;
     RECT  25.297 58.128 25.301 59.88 ;
     RECT  25.301 39.312 25.337 42.024 ;
     RECT  25.301 59.136 25.337 59.88 ;
     RECT  25.337 59.856 25.381 59.88 ;
     RECT  25.265 20.16 25.409 38.088 ;
     RECT  25.265 49.68 25.409 57.144 ;
     RECT  25.409 20.16 25.517 37.032 ;
     RECT  25.409 52.992 25.571 57.144 ;
     RECT  25.301 58.128 25.597 58.152 ;
     RECT  25.193 6.672 25.661 18.792 ;
     RECT  25.409 38.016 25.661 38.088 ;
     RECT  25.337 39.792 25.661 41.928 ;
     RECT  25.661 39.792 25.697 41.64 ;
     RECT  25.409 49.68 25.697 52.008 ;
     RECT  25.661 6.672 25.733 11.592 ;
     RECT  25.733 6.72 25.841 11.592 ;
     RECT  25.571 53.424 25.877 57.144 ;
     RECT  25.661 12.864 26.233 18.792 ;
     RECT  25.517 20.16 26.233 26.664 ;
     RECT  25.301 43.44 26.233 48.456 ;
     RECT  25.697 49.68 26.233 50.28 ;
     RECT  25.877 56.688 26.593 57.144 ;
     RECT  26.233 43.44 26.629 50.28 ;
     RECT  26.233 12.864 26.665 18.984 ;
     RECT  25.517 34.8 26.665 37.032 ;
     RECT  25.661 38.064 26.665 38.088 ;
     RECT  25.697 41.52 26.665 41.64 ;
     RECT  26.629 43.248 26.665 50.28 ;
     RECT  26.593 56.688 26.665 57.384 ;
     RECT  25.841 6.864 26.701 11.592 ;
     RECT  26.665 12.72 26.701 18.984 ;
     RECT  25.697 39.792 26.701 40.488 ;
     RECT  25.697 51.312 26.701 52.008 ;
     RECT  25.877 53.424 26.701 55.56 ;
     RECT  25.517 27.792 26.737 33.768 ;
     RECT  26.665 34.8 26.737 38.088 ;
     RECT  26.701 39.696 26.737 40.488 ;
     RECT  26.665 41.52 26.737 50.28 ;
     RECT  26.701 51.312 26.737 55.56 ;
     RECT  26.233 20.016 26.773 26.664 ;
     RECT  26.737 27.792 26.773 38.088 ;
     RECT  26.665 56.688 26.777 57.576 ;
     RECT  26.737 39.216 27.025 55.56 ;
     RECT  26.777 56.688 27.025 57.384 ;
     RECT  26.701 6.864 27.313 18.984 ;
     RECT  26.773 20.016 27.313 38.088 ;
     RECT  27.025 39.216 27.313 57.384 ;
     RECT  27.313 6.864 27.853 57.384 ;
     RECT  27.709 58.656 27.857 58.68 ;
     RECT  27.853 6.864 28.037 57.576 ;
     RECT  28.037 6.864 28.044 57.48 ;
    LAYER M5 ;
     RECT  2.352 0.085 3.144 0.131 ;
     RECT  3.12 0.131 3.144 2.137 ;
     RECT  7.8 2.137 7.92 2.151 ;
     RECT  13.2 2.137 13.32 2.151 ;
     RECT  18.6 2.137 18.72 2.151 ;
     RECT  24 2.137 24.12 2.151 ;
     RECT  2.4 2.137 3.144 5.701 ;
     RECT  2.4 5.701 3.816 5.893 ;
     RECT  2.4 5.893 4.392 6.037 ;
     RECT  2.4 6.037 4.776 6.181 ;
     RECT  6.624 6.133 6.648 6.229 ;
     RECT  7.8 2.151 8.112 6.229 ;
     RECT  24 2.151 24.312 6.229 ;
     RECT  2.4 6.181 4.968 7.861 ;
     RECT  6.576 6.229 8.424 7.861 ;
     RECT  2.4 7.861 5.112 7.909 ;
     RECT  6.144 7.861 8.424 7.909 ;
     RECT  0.144 7.669 0.168 7.955 ;
     RECT  13.2 2.151 13.512 7.957 ;
     RECT  23.808 6.229 24.312 8.245 ;
     RECT  25.44 6.805 25.464 8.245 ;
     RECT  11.04 8.005 11.064 8.435 ;
     RECT  21.36 7.381 21.384 8.437 ;
     RECT  23.808 8.245 25.464 8.579 ;
     RECT  13.2 7.957 13.992 8.723 ;
     RECT  2.4 7.909 8.424 8.867 ;
     RECT  6.144 8.867 8.424 8.869 ;
     RECT  24 8.579 25.464 9.155 ;
     RECT  2.4 8.867 5.112 9.925 ;
     RECT  6.144 8.869 9.384 9.925 ;
     RECT  20.544 8.437 21.384 10.069 ;
     RECT  18.6 2.151 18.912 10.165 ;
     RECT  2.4 9.925 9.384 10.357 ;
     RECT  20.544 10.069 21.672 10.883 ;
     RECT  24 9.155 25.128 10.883 ;
     RECT  18.48 10.165 18.912 11.267 ;
     RECT  24 10.883 24.552 11.555 ;
     RECT  22.752 10.837 22.776 11.699 ;
     RECT  0.192 9.589 0.216 11.701 ;
     RECT  0.144 11.701 0.216 12.275 ;
     RECT  21.36 10.883 21.384 12.469 ;
     RECT  2.304 10.357 9.384 12.563 ;
     RECT  2.304 12.563 8.112 12.755 ;
     RECT  16.56 9.397 16.584 12.995 ;
     RECT  18.6 11.267 18.912 13.045 ;
     RECT  10.512 12.469 10.536 13.091 ;
     RECT  21.36 12.469 22.008 13.091 ;
     RECT  0.144 12.275 0.168 13.285 ;
     RECT  21.936 13.091 22.008 13.571 ;
     RECT  24 11.555 24.408 13.619 ;
     RECT  19.968 13.045 19.992 14.291 ;
     RECT  2.4 12.755 8.112 14.437 ;
     RECT  0.144 13.285 0.312 14.483 ;
     RECT  2.304 14.437 8.112 14.965 ;
     RECT  9.36 12.563 9.384 14.965 ;
     RECT  21.936 13.571 21.96 15.349 ;
     RECT  21.648 15.349 21.96 15.397 ;
     RECT  20.496 14.533 20.52 15.443 ;
     RECT  21.648 15.397 22.776 15.491 ;
     RECT  2.304 14.965 9.384 15.731 ;
     RECT  18.24 13.045 18.912 15.827 ;
     RECT  22.752 15.491 22.776 16.115 ;
     RECT  0.144 14.483 0.168 16.213 ;
     RECT  18.288 15.827 18.912 16.261 ;
     RECT  18.288 16.261 19.848 16.451 ;
     RECT  0.144 16.213 0.264 16.787 ;
     RECT  21.648 15.491 21.672 16.981 ;
     RECT  9.696 15.877 9.72 17.077 ;
     RECT  0.144 16.787 0.168 17.171 ;
     RECT  21.024 16.981 21.672 17.509 ;
     RECT  2.304 15.731 8.616 17.699 ;
     RECT  24 13.619 24.312 17.797 ;
     RECT  18.288 16.451 18.912 17.941 ;
     RECT  24 17.797 25.08 17.987 ;
     RECT  2.304 17.699 6.264 18.275 ;
     RECT  7.488 17.699 8.616 18.563 ;
     RECT  0.528 18.277 0.552 18.565 ;
     RECT  7.68 18.563 8.616 18.565 ;
     RECT  9.696 17.077 9.864 18.565 ;
     RECT  20.736 17.509 21.768 18.709 ;
     RECT  20.016 18.709 21.768 18.851 ;
     RECT  22.8 18.181 22.824 18.947 ;
     RECT  2.304 18.275 6.168 19.043 ;
     RECT  13.2 8.723 13.512 19.045 ;
     RECT  13.2 19.045 13.656 19.237 ;
     RECT  0.192 18.565 0.552 19.283 ;
     RECT  2.304 19.043 4.488 19.427 ;
     RECT  0.192 19.283 0.36 19.475 ;
     RECT  2.304 19.427 4.152 19.619 ;
     RECT  13.2 19.237 14.52 19.765 ;
     RECT  20.736 18.851 21.768 19.909 ;
     RECT  0.192 19.475 0.312 20.003 ;
     RECT  7.68 18.565 9.864 20.053 ;
     RECT  0.24 20.003 0.312 20.099 ;
     RECT  7.392 20.053 9.864 20.293 ;
     RECT  2.4 19.619 4.152 20.485 ;
     RECT  13.2 19.765 14.76 20.485 ;
     RECT  5.472 19.043 6.168 20.579 ;
     RECT  0.288 20.099 0.312 20.627 ;
     RECT  13.2 20.485 15.576 20.725 ;
     RECT  13.2 20.725 16.248 21.013 ;
     RECT  17.52 17.941 18.912 21.013 ;
     RECT  24 17.987 24.312 21.109 ;
     RECT  5.472 20.579 5.64 21.155 ;
     RECT  13.2 21.013 18.912 21.155 ;
     RECT  22.752 19.669 22.776 21.155 ;
     RECT  7.392 20.293 9.912 21.397 ;
     RECT  7.392 21.397 10.2 21.493 ;
     RECT  15.744 21.155 18.912 21.493 ;
     RECT  6.624 21.493 10.2 21.637 ;
     RECT  24 21.109 24.456 21.685 ;
     RECT  13.2 21.155 13.656 21.925 ;
     RECT  2.4 20.485 4.44 22.021 ;
     RECT  15.744 21.493 19.224 22.069 ;
     RECT  12.528 21.925 13.656 22.597 ;
     RECT  14.736 21.155 14.76 22.597 ;
     RECT  12.528 22.597 14.76 22.645 ;
     RECT  15.744 22.069 19.656 22.645 ;
     RECT  12.528 22.645 19.656 23.075 ;
     RECT  24 21.685 24.504 23.267 ;
     RECT  2.4 22.021 4.488 23.269 ;
     RECT  5.616 21.155 5.64 23.269 ;
     RECT  6.624 21.637 10.632 23.411 ;
     RECT  13.2 23.075 19.656 23.555 ;
     RECT  2.4 23.269 5.64 23.797 ;
     RECT  6.624 23.411 6.648 23.797 ;
     RECT  0.144 21.781 0.168 23.941 ;
     RECT  7.8 23.411 10.632 23.987 ;
     RECT  14.736 23.555 19.656 24.085 ;
     RECT  20.688 19.909 21.768 24.085 ;
     RECT  2.4 23.797 6.648 24.371 ;
     RECT  13.2 23.555 13.608 24.373 ;
     RECT  13.104 24.373 13.608 24.421 ;
     RECT  0.144 23.941 0.312 24.563 ;
     RECT  10.608 23.987 10.632 24.613 ;
     RECT  12.528 24.421 13.608 24.805 ;
     RECT  12.528 24.805 13.656 24.901 ;
     RECT  14.736 24.085 21.768 24.901 ;
     RECT  6.24 24.371 6.648 25.045 ;
     RECT  7.8 23.987 9.624 25.045 ;
     RECT  10.608 24.613 10.776 25.045 ;
     RECT  2.4 24.371 5.112 25.429 ;
     RECT  6.24 25.045 10.776 25.429 ;
     RECT  0.144 24.563 0.264 25.573 ;
     RECT  12.528 24.901 21.768 25.715 ;
     RECT  0.144 25.573 0.552 25.763 ;
     RECT  2.304 25.429 10.776 26.437 ;
     RECT  0.288 25.763 0.552 26.627 ;
     RECT  13.2 25.715 21.768 26.819 ;
     RECT  0.288 26.627 0.312 26.867 ;
     RECT  2.304 26.437 10.824 27.395 ;
     RECT  13.2 26.819 19.512 27.589 ;
     RECT  0.144 27.157 0.168 27.731 ;
     RECT  12.528 27.589 19.512 27.877 ;
     RECT  20.544 26.819 21.768 27.877 ;
     RECT  10.56 27.395 10.824 28.453 ;
     RECT  12.528 27.877 21.768 28.453 ;
     RECT  24 23.267 24.312 28.453 ;
     RECT  0.528 27.829 0.552 28.595 ;
     RECT  2.304 27.395 9.432 28.595 ;
     RECT  10.56 28.453 21.768 29.363 ;
     RECT  0.24 28.981 0.264 29.557 ;
     RECT  12.528 29.363 21.768 29.699 ;
     RECT  23.04 28.453 24.312 29.747 ;
     RECT  2.304 28.595 9.144 29.795 ;
     RECT  2.4 29.795 9.144 29.797 ;
     RECT  10.56 29.363 11.496 29.797 ;
     RECT  0.24 29.557 0.312 29.989 ;
     RECT  0.144 29.989 0.312 30.371 ;
     RECT  0.192 30.371 0.312 30.419 ;
     RECT  2.4 29.797 11.496 30.803 ;
     RECT  2.4 30.803 9.24 30.947 ;
     RECT  0.192 30.419 0.216 30.995 ;
     RECT  10.224 30.803 11.496 30.995 ;
     RECT  13.2 29.699 19.32 31.093 ;
     RECT  13.104 31.093 19.32 31.427 ;
     RECT  27.888 31.429 27.912 31.619 ;
     RECT  22.896 30.757 22.92 31.667 ;
     RECT  20.688 29.699 21.768 31.669 ;
     RECT  9.216 30.947 9.24 31.765 ;
     RECT  10.224 30.995 10.824 31.765 ;
     RECT  24 29.747 24.312 31.813 ;
     RECT  12.096 31.813 12.12 31.861 ;
     RECT  13.104 31.427 14.808 31.861 ;
     RECT  20.688 31.669 21.864 32.147 ;
     RECT  2.4 30.947 8.232 32.437 ;
     RECT  9.216 31.765 10.824 32.437 ;
     RECT  2.4 32.437 10.824 32.531 ;
     RECT  22.752 32.485 22.776 32.821 ;
     RECT  0.144 32.917 0.168 33.107 ;
     RECT  15.792 31.427 19.32 33.157 ;
     RECT  22.752 32.821 22.824 33.251 ;
     RECT  24 31.813 24.408 33.301 ;
     RECT  22.8 33.251 22.824 33.347 ;
     RECT  12.096 31.861 14.808 33.349 ;
     RECT  11.904 33.349 14.808 33.445 ;
     RECT  15.792 33.157 19.368 33.445 ;
     RECT  24 33.301 25.032 33.589 ;
     RECT  2.4 32.531 10.104 33.683 ;
     RECT  11.904 33.445 19.368 33.875 ;
     RECT  6.816 33.683 10.104 34.693 ;
     RECT  11.904 33.875 19.32 34.835 ;
     RECT  23.664 33.589 25.032 34.933 ;
     RECT  2.4 33.683 5.688 35.077 ;
     RECT  6.816 34.693 10.824 35.077 ;
     RECT  2.4 35.077 10.824 35.507 ;
     RECT  22.8 34.933 25.032 35.557 ;
     RECT  22.8 35.557 25.08 35.939 ;
     RECT  23.568 35.939 25.08 36.083 ;
     RECT  2.4 35.507 10.104 36.275 ;
     RECT  23.568 36.083 25.032 36.323 ;
     RECT  2.4 36.275 9.72 36.515 ;
     RECT  23.568 36.323 24.504 36.995 ;
     RECT  2.4 36.515 6.072 37.091 ;
     RECT  12.048 34.835 19.32 37.091 ;
     RECT  23.568 36.995 24.312 37.091 ;
     RECT  13.008 37.091 19.32 37.139 ;
     RECT  5.088 37.091 6.072 37.573 ;
     RECT  7.056 36.515 9.72 37.573 ;
     RECT  5.088 37.573 9.72 37.667 ;
     RECT  6.672 37.667 9.72 37.715 ;
     RECT  20.688 32.147 21.768 38.005 ;
     RECT  20.688 38.005 22.2 38.149 ;
     RECT  0.144 38.005 0.168 38.195 ;
     RECT  11.568 38.005 11.592 38.533 ;
     RECT  13.2 37.139 19.32 38.533 ;
     RECT  23.664 37.091 24.312 38.533 ;
     RECT  11.568 38.533 19.32 38.677 ;
     RECT  20.688 38.149 22.536 38.677 ;
     RECT  5.088 37.667 5.688 38.725 ;
     RECT  6.672 37.715 8.112 38.725 ;
     RECT  23.664 38.533 24.408 38.917 ;
     RECT  9.696 37.715 9.72 39.061 ;
     RECT  23.664 38.917 24.504 39.155 ;
     RECT  11.568 38.677 22.536 39.395 ;
     RECT  15.072 39.395 22.536 39.491 ;
     RECT  2.4 37.091 4.056 39.589 ;
     RECT  5.088 38.725 8.112 39.589 ;
     RECT  11.568 39.395 14.04 39.635 ;
     RECT  9.504 39.061 9.72 39.637 ;
     RECT  2.4 39.589 8.112 39.877 ;
     RECT  9.168 39.637 9.72 39.877 ;
     RECT  2.4 39.877 9.72 40.067 ;
     RECT  11.568 39.635 13.848 40.067 ;
     RECT  23.664 39.155 24.312 40.165 ;
     RECT  23.664 40.165 24.6 40.453 ;
     RECT  2.4 40.067 9.528 40.499 ;
     RECT  23.664 40.453 25.08 40.499 ;
     RECT  15.072 39.491 21.768 40.547 ;
     RECT  0.144 40.453 0.168 40.549 ;
     RECT  24 40.499 25.08 40.643 ;
     RECT  0.144 40.549 0.216 40.645 ;
     RECT  0.144 40.645 0.264 40.837 ;
     RECT  15.168 40.547 21.768 41.075 ;
     RECT  7.152 40.499 9.528 41.365 ;
     RECT  0.144 40.837 0.312 41.461 ;
     RECT  7.152 41.365 10.2 41.507 ;
     RECT  15.168 41.075 20.184 41.555 ;
     RECT  15.168 41.555 16.248 41.651 ;
     RECT  17.76 41.555 20.184 41.651 ;
     RECT  24 40.643 24.6 41.699 ;
     RECT  0.144 41.461 0.408 41.747 ;
     RECT  0.144 41.747 0.312 41.795 ;
     RECT  2.4 40.499 5.976 41.989 ;
     RECT  7.152 41.507 9.528 41.989 ;
     RECT  11.568 40.067 12.024 42.227 ;
     RECT  15.504 41.651 16.248 42.227 ;
     RECT  0.144 41.795 0.168 42.275 ;
     RECT  17.904 41.651 19.416 42.419 ;
     RECT  22.176 42.133 22.2 42.755 ;
     RECT  2.4 41.989 9.528 43.379 ;
     RECT  13.2 40.067 13.848 43.379 ;
     RECT  2.4 43.379 8.808 43.955 ;
     RECT  15.552 42.227 16.248 43.955 ;
     RECT  2.4 43.955 6.552 44.099 ;
     RECT  0.144 43.717 0.168 44.293 ;
     RECT  17.904 42.419 19.32 44.483 ;
     RECT  2.4 44.099 6.168 44.579 ;
     RECT  0.144 44.293 0.216 44.677 ;
     RECT  16.224 43.955 16.248 45.107 ;
     RECT  22.176 43.813 22.2 45.155 ;
     RECT  0.144 44.677 0.264 45.203 ;
     RECT  7.68 43.955 8.808 45.493 ;
     RECT  18.432 44.483 18.912 45.541 ;
     RECT  0.24 45.203 0.264 45.635 ;
     RECT  5.568 44.579 6.168 45.635 ;
     RECT  2.4 44.579 4.488 46.069 ;
     RECT  5.616 45.635 6.168 46.069 ;
     RECT  17.52 45.541 18.912 46.163 ;
     RECT  0.336 45.637 0.36 46.259 ;
     RECT  20.112 45.829 20.136 46.693 ;
     RECT  26.784 46.501 26.808 46.739 ;
     RECT  2.4 46.069 4.536 46.933 ;
     RECT  5.616 46.069 6.264 46.933 ;
     RECT  20.112 46.693 20.184 47.315 ;
     RECT  2.4 46.933 6.264 47.459 ;
     RECT  22.128 46.645 22.152 47.507 ;
     RECT  5.04 47.459 6.264 47.701 ;
     RECT  7.392 45.493 8.808 47.701 ;
     RECT  2.4 47.459 3.96 47.939 ;
     RECT  5.04 47.701 8.808 48.613 ;
     RECT  9.792 45.877 9.816 48.613 ;
     RECT  5.04 48.613 9.816 48.659 ;
     RECT  18.432 46.163 18.912 48.757 ;
     RECT  20.16 47.315 20.184 48.757 ;
     RECT  18.432 48.757 20.184 48.949 ;
     RECT  5.04 48.659 9 48.997 ;
     RECT  24 41.699 24.312 49.285 ;
     RECT  18.432 48.949 20.52 49.333 ;
     RECT  16.512 47.893 16.536 49.475 ;
     RECT  18.288 49.333 20.52 49.571 ;
     RECT  24 49.285 24.408 49.669 ;
     RECT  12.048 48.661 12.072 49.715 ;
     RECT  18.288 49.571 20.328 50.051 ;
     RECT  2.4 47.939 3.912 50.101 ;
     RECT  4.992 48.997 9 50.101 ;
     RECT  18.288 50.051 18.912 50.101 ;
     RECT  17.664 50.101 18.912 50.435 ;
     RECT  24 49.669 24.456 50.483 ;
     RECT  20.304 50.051 20.328 50.819 ;
     RECT  22.992 50.149 23.016 50.963 ;
     RECT  24 50.483 24.312 51.301 ;
     RECT  14.832 50.965 14.856 51.683 ;
     RECT  2.4 50.101 9 51.731 ;
     RECT  2.4 51.731 8.52 51.923 ;
     RECT  23.136 51.301 24.312 52.837 ;
     RECT  23.136 52.837 24.648 52.981 ;
     RECT  4.512 51.923 8.52 53.075 ;
     RECT  12.096 50.101 12.12 53.075 ;
     RECT  4.512 53.075 8.232 53.461 ;
     RECT  0.144 53.365 0.168 53.555 ;
     RECT  23.136 52.981 25.56 53.749 ;
     RECT  22.8 53.749 25.56 53.795 ;
     RECT  22.8 53.795 22.824 54.085 ;
     RECT  4.464 53.461 8.232 54.371 ;
     RECT  2.4 51.923 3.432 54.469 ;
     RECT  22.752 54.085 22.824 54.611 ;
     RECT  2.304 54.469 3.432 54.659 ;
     RECT  6.528 54.371 8.232 54.755 ;
     RECT  19.968 54.661 19.992 54.803 ;
     RECT  0.288 54.661 0.312 54.899 ;
     RECT  18.288 50.435 18.912 55.237 ;
     RECT  17.52 55.237 18.912 55.283 ;
     RECT  22.752 54.611 22.776 55.379 ;
     RECT  4.656 54.371 5.352 55.669 ;
     RECT  6.528 54.755 8.112 55.669 ;
     RECT  2.4 54.659 3.432 55.813 ;
     RECT  4.656 55.669 8.112 55.813 ;
     RECT  2.4 55.813 8.112 55.907 ;
     RECT  21.168 54.997 21.192 55.907 ;
     RECT  17.52 55.283 17.544 55.955 ;
     RECT  3.936 55.907 8.112 56.101 ;
     RECT  2.4 55.907 2.808 56.581 ;
     RECT  0.144 56.773 0.168 56.963 ;
     RECT  2.304 56.581 2.808 56.965 ;
     RECT  14.928 56.773 14.952 57.299 ;
     RECT  21.648 57.013 21.672 58.115 ;
     RECT  3.936 56.101 8.52 58.163 ;
     RECT  17.136 57.013 17.16 58.163 ;
     RECT  24 53.795 25.56 58.163 ;
     RECT  5.856 58.163 8.112 58.211 ;
     RECT  6.336 58.211 8.112 58.451 ;
     RECT  9.744 57.541 9.768 58.643 ;
     RECT  2.304 56.965 2.856 58.691 ;
     RECT  7.296 58.451 8.112 58.739 ;
     RECT  3.936 58.163 4.872 58.787 ;
     RECT  2.304 58.691 2.712 59.315 ;
     RECT  3.936 58.787 4.68 59.315 ;
     RECT  25.344 58.163 25.368 59.891 ;
     RECT  2.4 59.315 2.712 62.649 ;
     RECT  7.8 58.739 8.112 62.649 ;
     RECT  13.2 43.379 13.512 62.649 ;
     RECT  18.6 55.283 18.912 62.649 ;
     RECT  24 58.163 24.312 62.649 ;
     RECT  2.4 62.649 2.52 62.663 ;
     RECT  7.8 62.649 7.92 62.663 ;
     RECT  13.2 62.649 13.32 62.663 ;
     RECT  18.6 62.649 18.72 62.663 ;
     RECT  24 62.649 24.12 62.663 ;
  END
END ot_qwen_tree_delay4_t
END LIBRARY
